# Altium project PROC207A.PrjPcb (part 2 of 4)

## Sheet PROC207A_Chip_Power.SchDoc: xWRL6888_POWER
size 431 x 279 mm; Date: Not shown in title block; ApprovedBy: Not shown in title block; CheckedBy: Not shown in title block; Author: Not shown in title block; CompanyName: Not shown in title block; DrawnBy: Mistral; Engineer: Not shown in title block; Organization: Not shown in title block; Address1: Not shown in title block; Address2: Not shown in title block; Address3: Not shown in title block; Address4: Not shown in title block; DocumentNumber: 2; Revision: Use project parameter SCH_Rev; SheetNumber: 7; SheetTotal: 18; PageSetup: Record=PageOptions¦CenterHorizontal=True¦CenterVertical=True¦PrintScale=1.00¦XCorrection=1.00¦YCorrection=1.00¦PrintKind=0¦BorderSize=5000000¦LeftOffset=0¦BottomOffset=0¦Orientation=2¦PaperLength=1000¦PaperWidth=1000¦Scale=100¦PaperSource=15¦PrintQuality=600¦MediaType=1¦DitherType=10¦PaperKind=Letter¦PrintScaleMode=1

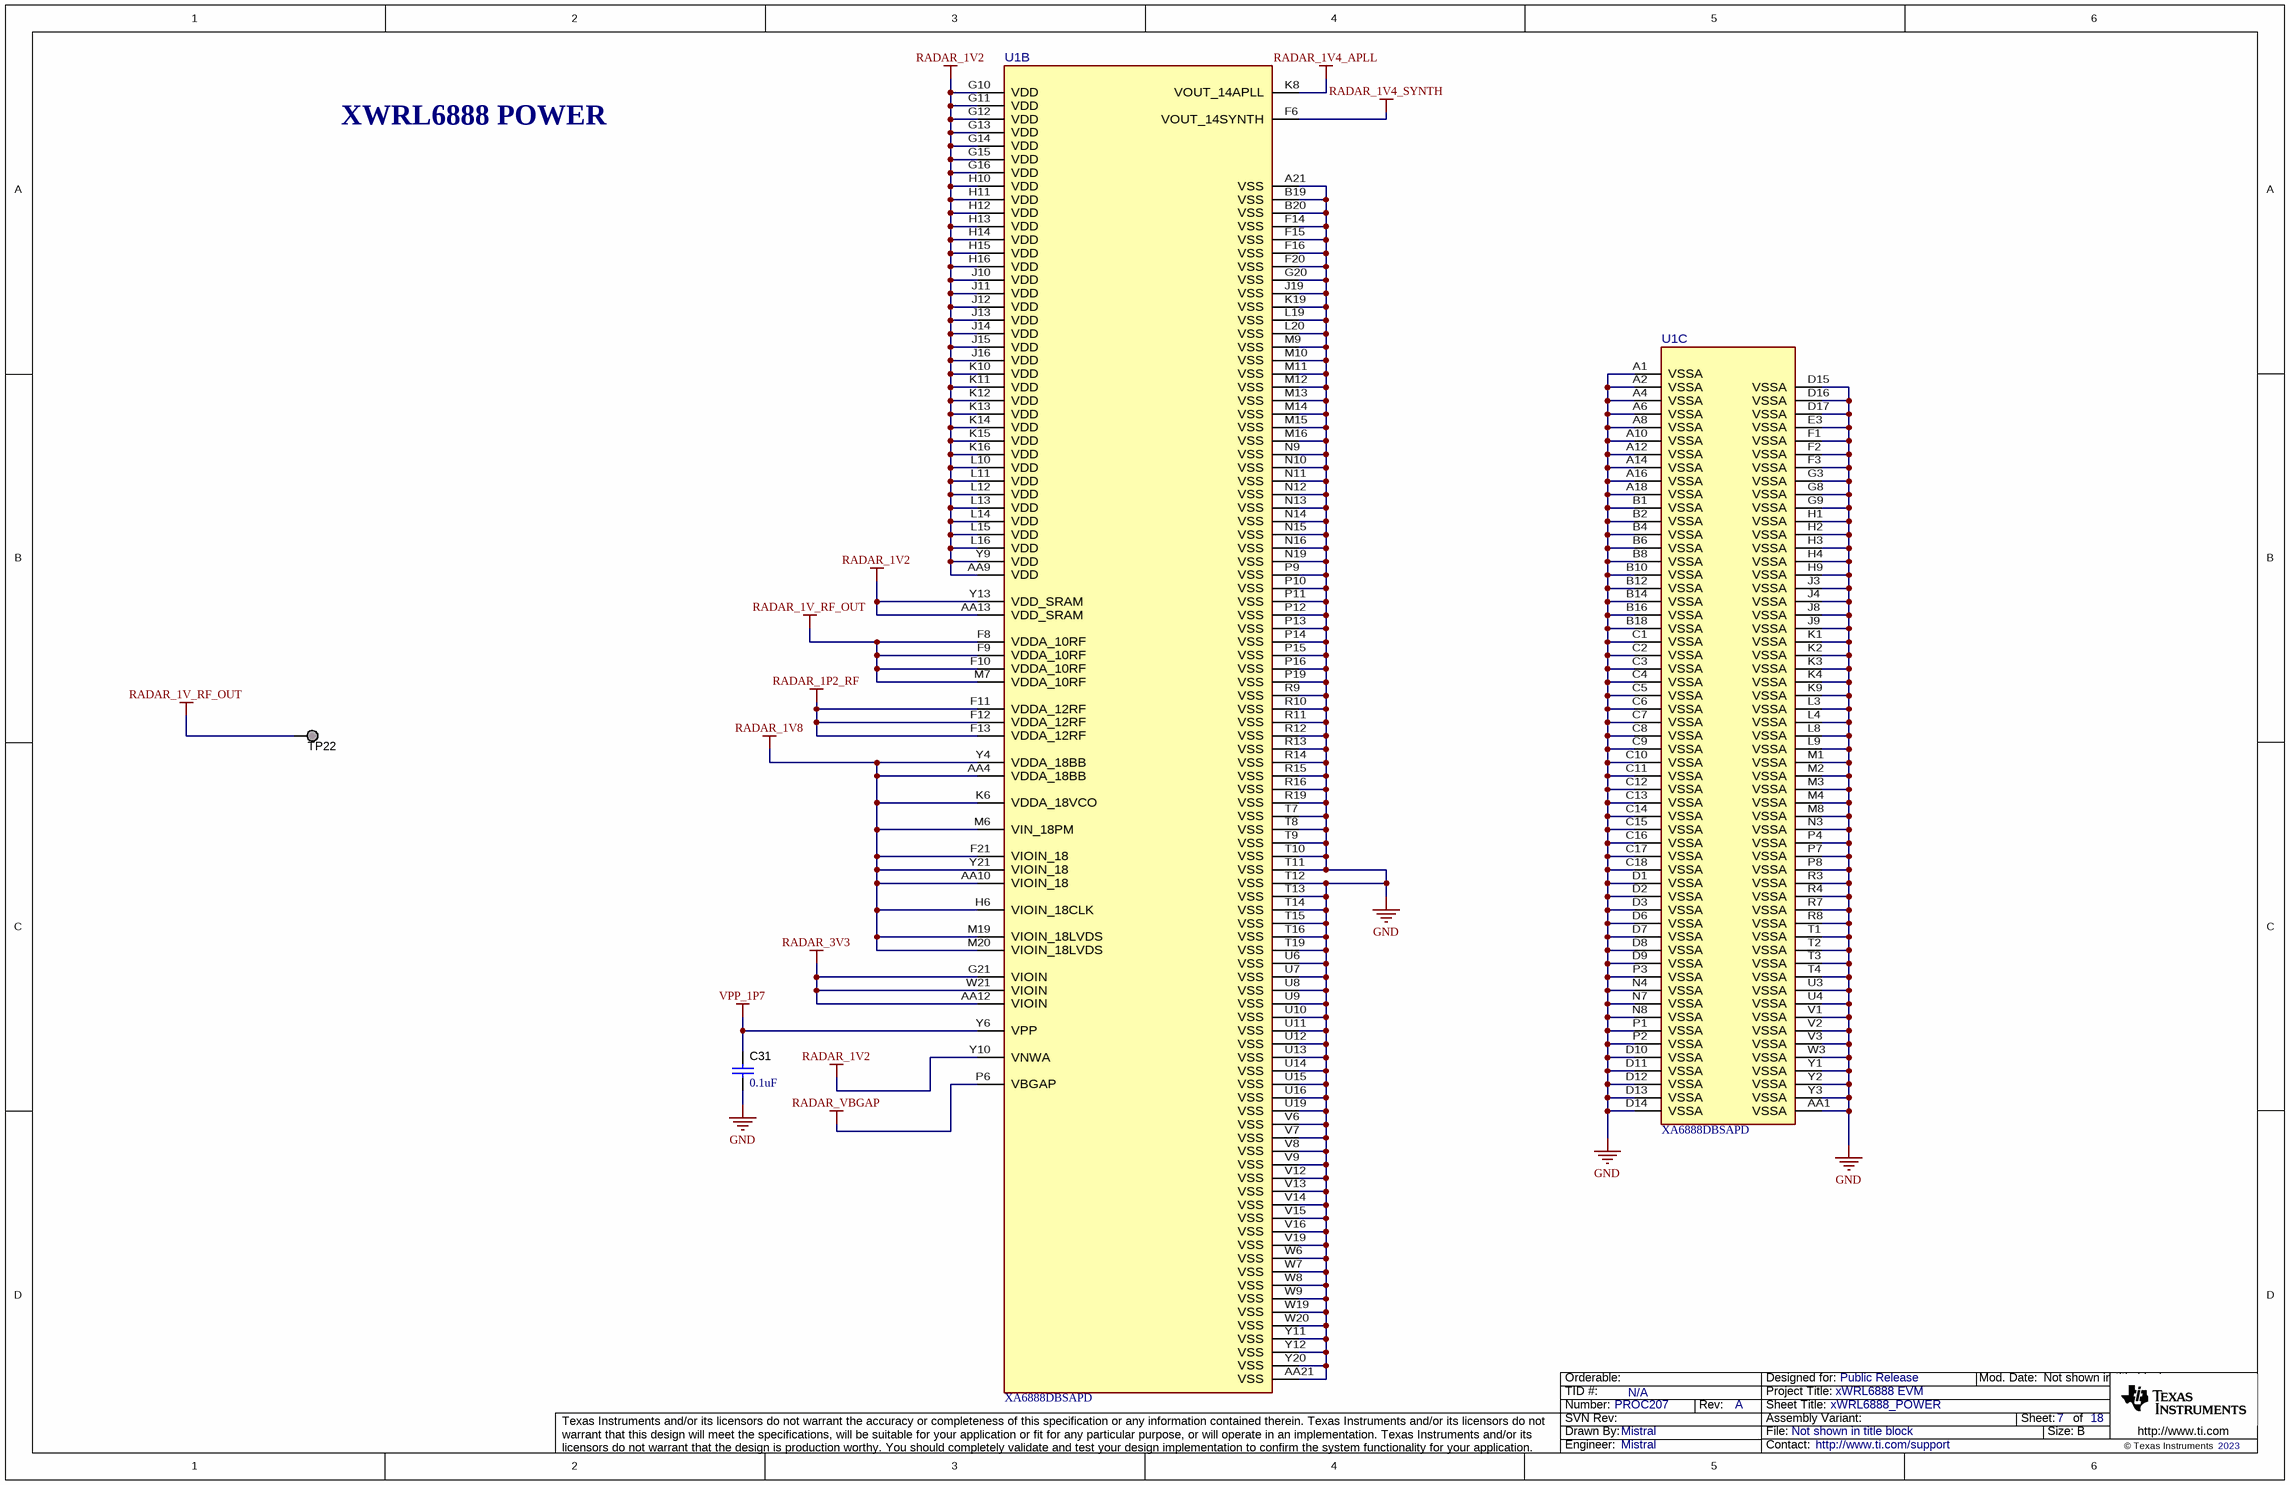
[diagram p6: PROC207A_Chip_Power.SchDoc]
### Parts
C31  ValueDisplayed: 0.1uF  [0402]  (hidden comment: GCM155R71H104KE02D)
TP22  TESTPOINT  [TP_VIA_060RND040]  (value not drawn)  (no BOM)
U1  XA6888DBSAPD  [0-MFG]  (parts B,C of 3)

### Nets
GND: C31.2 U1.A1(VSSA) U1.A2(VSSA) U1.A4(VSSA) U1.A6(VSSA) U1.A8(VSSA) U1.A10(VSSA) U1.A12(VSSA) U1.A14(VSSA) U1.A16(VSSA) U1.A18(VSSA) U1.A21(VSS) U1.AA1(VSSA) U1.AA21(VSS) U1.B1(VSSA) U1.B2(VSSA) U1.B4(VSSA) U1.B6(VSSA) U1.B8(VSSA) U1.B10(VSSA) U1.B12(VSSA) U1.B14(VSSA) U1.B16(VSSA) U1.B18(VSSA) U1.B19(VSS) U1.B20(VSS) U1.C1(VSSA) U1.C2(VSSA) U1.C3(VSSA) U1.C4(VSSA) U1.C5(VSSA) U1.C6(VSSA) U1.C7(VSSA) U1.C8(VSSA) U1.C9(VSSA) U1.C10(VSSA) U1.C11(VSSA) U1.C12(VSSA) U1.C13(VSSA) U1.C14(VSSA) U1.C15(VSSA) U1.C16(VSSA) U1.C17(VSSA) U1.C18(VSSA) U1.D1(VSSA) U1.D2(VSSA) U1.D3(VSSA) U1.D6(VSSA) U1.D7(VSSA) U1.D8(VSSA) U1.D9(VSSA) U1.D10(VSSA) U1.D11(VSSA) U1.D12(VSSA) U1.D13(VSSA) U1.D14(VSSA) U1.D15(VSSA) U1.D16(VSSA) U1.D17(VSSA) U1.E3(VSSA) U1.F1(VSSA) U1.F2(VSSA) U1.F3(VSSA) U1.F14(VSS) U1.F15(VSS) U1.F16(VSS) U1.F20(VSS) U1.G3(VSSA) U1.G8(VSSA) U1.G9(VSSA) U1.G20(VSS) U1.H1(VSSA) U1.H2(VSSA) U1.H3(VSSA) U1.H4(VSSA) U1.H9(VSSA) U1.J3(VSSA) U1.J4(VSSA) U1.J8(VSSA) U1.J9(VSSA) U1.J19(VSS) U1.K1(VSSA) U1.K2(VSSA) U1.K3(VSSA) U1.K4(VSSA) U1.K9(VSSA) U1.K19(VSS) U1.L3(VSSA) U1.L4(VSSA) U1.L8(VSSA) U1.L9(VSSA) U1.L19(VSS) U1.L20(VSS) U1.M1(VSSA) U1.M2(VSSA) U1.M3(VSSA) U1.M4(VSSA) U1.M8(VSSA) U1.M9(VSS) U1.M10(VSS) U1.M11(VSS) U1.M12(VSS) U1.M13(VSS) U1.M14(VSS) U1.M15(VSS) U1.M16(VSS) U1.N3(VSSA) U1.N4(VSSA) U1.N7(VSSA) U1.N8(VSSA) U1.N9(VSS) U1.N10(VSS) U1.N11(VSS) U1.N12(VSS) U1.N13(VSS) U1.N14(VSS) U1.N15(VSS) U1.N16(VSS) U1.N19(VSS) U1.P1(VSSA) U1.P2(VSSA) U1.P3(VSSA) U1.P4(VSSA) U1.P7(VSSA) U1.P8(VSSA) U1.P9(VSS) U1.P10(VSS) U1.P11(VSS) U1.P12(VSS) U1.P13(VSS) U1.P14(VSS) U1.P15(VSS) U1.P16(VSS) U1.P19(VSS) U1.R3(VSSA) U1.R4(VSSA) U1.R7(VSSA) U1.R8(VSSA) U1.R9(VSS) U1.R10(VSS) U1.R11(VSS) U1.R12(VSS) U1.R13(VSS) U1.R14(VSS) U1.R15(VSS) U1.R16(VSS) U1.R19(VSS) U1.T1(VSSA) U1.T2(VSSA) U1.T3(VSSA) U1.T4(VSSA) U1.T7(VSS) U1.T8(VSS) U1.T9(VSS) U1.T10(VSS) U1.T11(VSS) U1.T12(VSS) U1.T13(VSS) U1.T14(VSS) U1.T15(VSS) U1.T16(VSS) U1.T19(VSS) U1.U3(VSSA) U1.U4(VSSA) U1.U6(VSS) U1.U7(VSS) U1.U8(VSS) U1.U9(VSS) U1.U10(VSS) U1.U11(VSS) U1.U12(VSS) U1.U13(VSS) U1.U14(VSS) U1.U15(VSS) U1.U16(VSS) U1.U19(VSS) U1.V1(VSSA) U1.V2(VSSA) U1.V3(VSSA) U1.V6(VSS) U1.V7(VSS) U1.V8(VSS) U1.V9(VSS) U1.V12(VSS) U1.V13(VSS) U1.V14(VSS) U1.V15(VSS) U1.V16(VSS) U1.V19(VSS) U1.W3(VSSA) U1.W6(VSS) U1.W7(VSS) U1.W8(VSS) U1.W9(VSS) U1.W19(VSS) U1.W20(VSS) U1.Y1(VSSA) U1.Y2(VSSA) U1.Y3(VSSA) U1.Y11(VSS) U1.Y12(VSS) U1.Y20(VSS)
RADAR_1P2_RF: U1.F11(VDDA_12RF) U1.F12(VDDA_12RF) U1.F13(VDDA_12RF)
RADAR_1V2: U1.AA9(VDD) U1.AA13(VDD_SRAM) U1.G10(VDD) U1.G11(VDD) U1.G12(VDD) U1.G13(VDD) U1.G14(VDD) U1.G15(VDD) U1.G16(VDD) U1.H10(VDD) U1.H11(VDD) U1.H12(VDD) U1.H13(VDD) U1.H14(VDD) U1.H15(VDD) U1.H16(VDD) U1.J10(VDD) U1.J11(VDD) U1.J12(VDD) U1.J13(VDD) U1.J14(VDD) U1.J15(VDD) U1.J16(VDD) U1.K10(VDD) U1.K11(VDD) U1.K12(VDD) U1.K13(VDD) U1.K14(VDD) U1.K15(VDD) U1.K16(VDD) U1.L10(VDD) U1.L11(VDD) U1.L12(VDD) U1.L13(VDD) U1.L14(VDD) U1.L15(VDD) U1.L16(VDD) U1.Y9(VDD) U1.Y10(VNWA) U1.Y13(VDD_SRAM)
RADAR_1V4_APLL: U1.K8(VOUT_14APLL)
RADAR_1V4_SYNTH: U1.F6(VOUT_14SYNTH)
RADAR_1V8: U1.AA4(VDDA_18BB) U1.AA10(VIOIN_18) U1.F21(VIOIN_18) U1.H6(VIOIN_18CLK) U1.K6(VDDA_18VCO) U1.M6(VIN_18PM) U1.M19(VIOIN_18LVDS) U1.M20(VIOIN_18LVDS) U1.Y4(VDDA_18BB) U1.Y21(VIOIN_18)
RADAR_1V_RF_OUT: TP22.1 U1.F8(VDDA_10RF) U1.F9(VDDA_10RF) U1.F10(VDDA_10RF) U1.M7(VDDA_10RF)
RADAR_3V3: U1.AA12(VIOIN) U1.G21(VIOIN) U1.W21(VIOIN)
RADAR_VBGAP: U1.P6(VBGAP)
VPP_1P7: C31.1 U1.Y6(VPP)

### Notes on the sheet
- XWRL6888 POWER

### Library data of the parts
C31 = CMP-0006356-2: CAP, CERM, 0.1 uF, 50 V, +/- 10%, X7R, AEC-Q200 Grade 1, 0402; Manufacturer: MuRata; TaMin_C: -55°C; Polarized: N; SizeAreaWB_mm2: 3; Value1: Unknown; U/M: EA; Value: 0.1uF; TaMax_C: 125°C; SizeZ_mm: 0.6; SizeX_mm: 1; SizeY_mm: 0.5; Value2: 50V; AEC Qualified: Y; Cap_F: 100nF; AEC Category: Q200
TP22 = CMP-0078143-3: TEST POINT.  No entry in BOM.
U1 = CMP-0122984-4: Manufacturer: Texas Instruments; SizeZ_mm: 1.044mm; AEC Qualified: Unknown; Standoff Height: 0.155mm; AEC Category: Q200; CompType: IC

## Sheet PROC207A_Decoupling_caps- QSPI Flash.SchDoc: DECOUPLING_CAPS_QSPI_FLASH
size 431 x 279 mm; Date: Not shown in title block; ApprovedBy: Not shown in title block; CheckedBy: Not shown in title block; Author: Not shown in title block; CompanyName: Not shown in title block; DrawnBy: Mistral; Engineer: Not shown in title block; Organization: Not shown in title block; Address1: Not shown in title block; Address2: Not shown in title block; Address3: Not shown in title block; Address4: Not shown in title block; DocumentNumber: 2; Revision: Use project parameter SCH_Rev; SheetNumber: 8; SheetTotal: 18; PageSetup: Record=PageOptions¦CenterHorizontal=True¦CenterVertical=True¦PrintScale=1.00¦XCorrection=1.00¦YCorrection=1.00¦PrintKind=0¦BorderSize=5000000¦LeftOffset=0¦BottomOffset=0¦Orientation=2¦PaperLength=1000¦PaperWidth=1000¦Scale=100¦PaperSource=15¦PrintQuality=600¦MediaType=1¦DitherType=10¦PaperKind=Letter¦PrintScaleMode=1

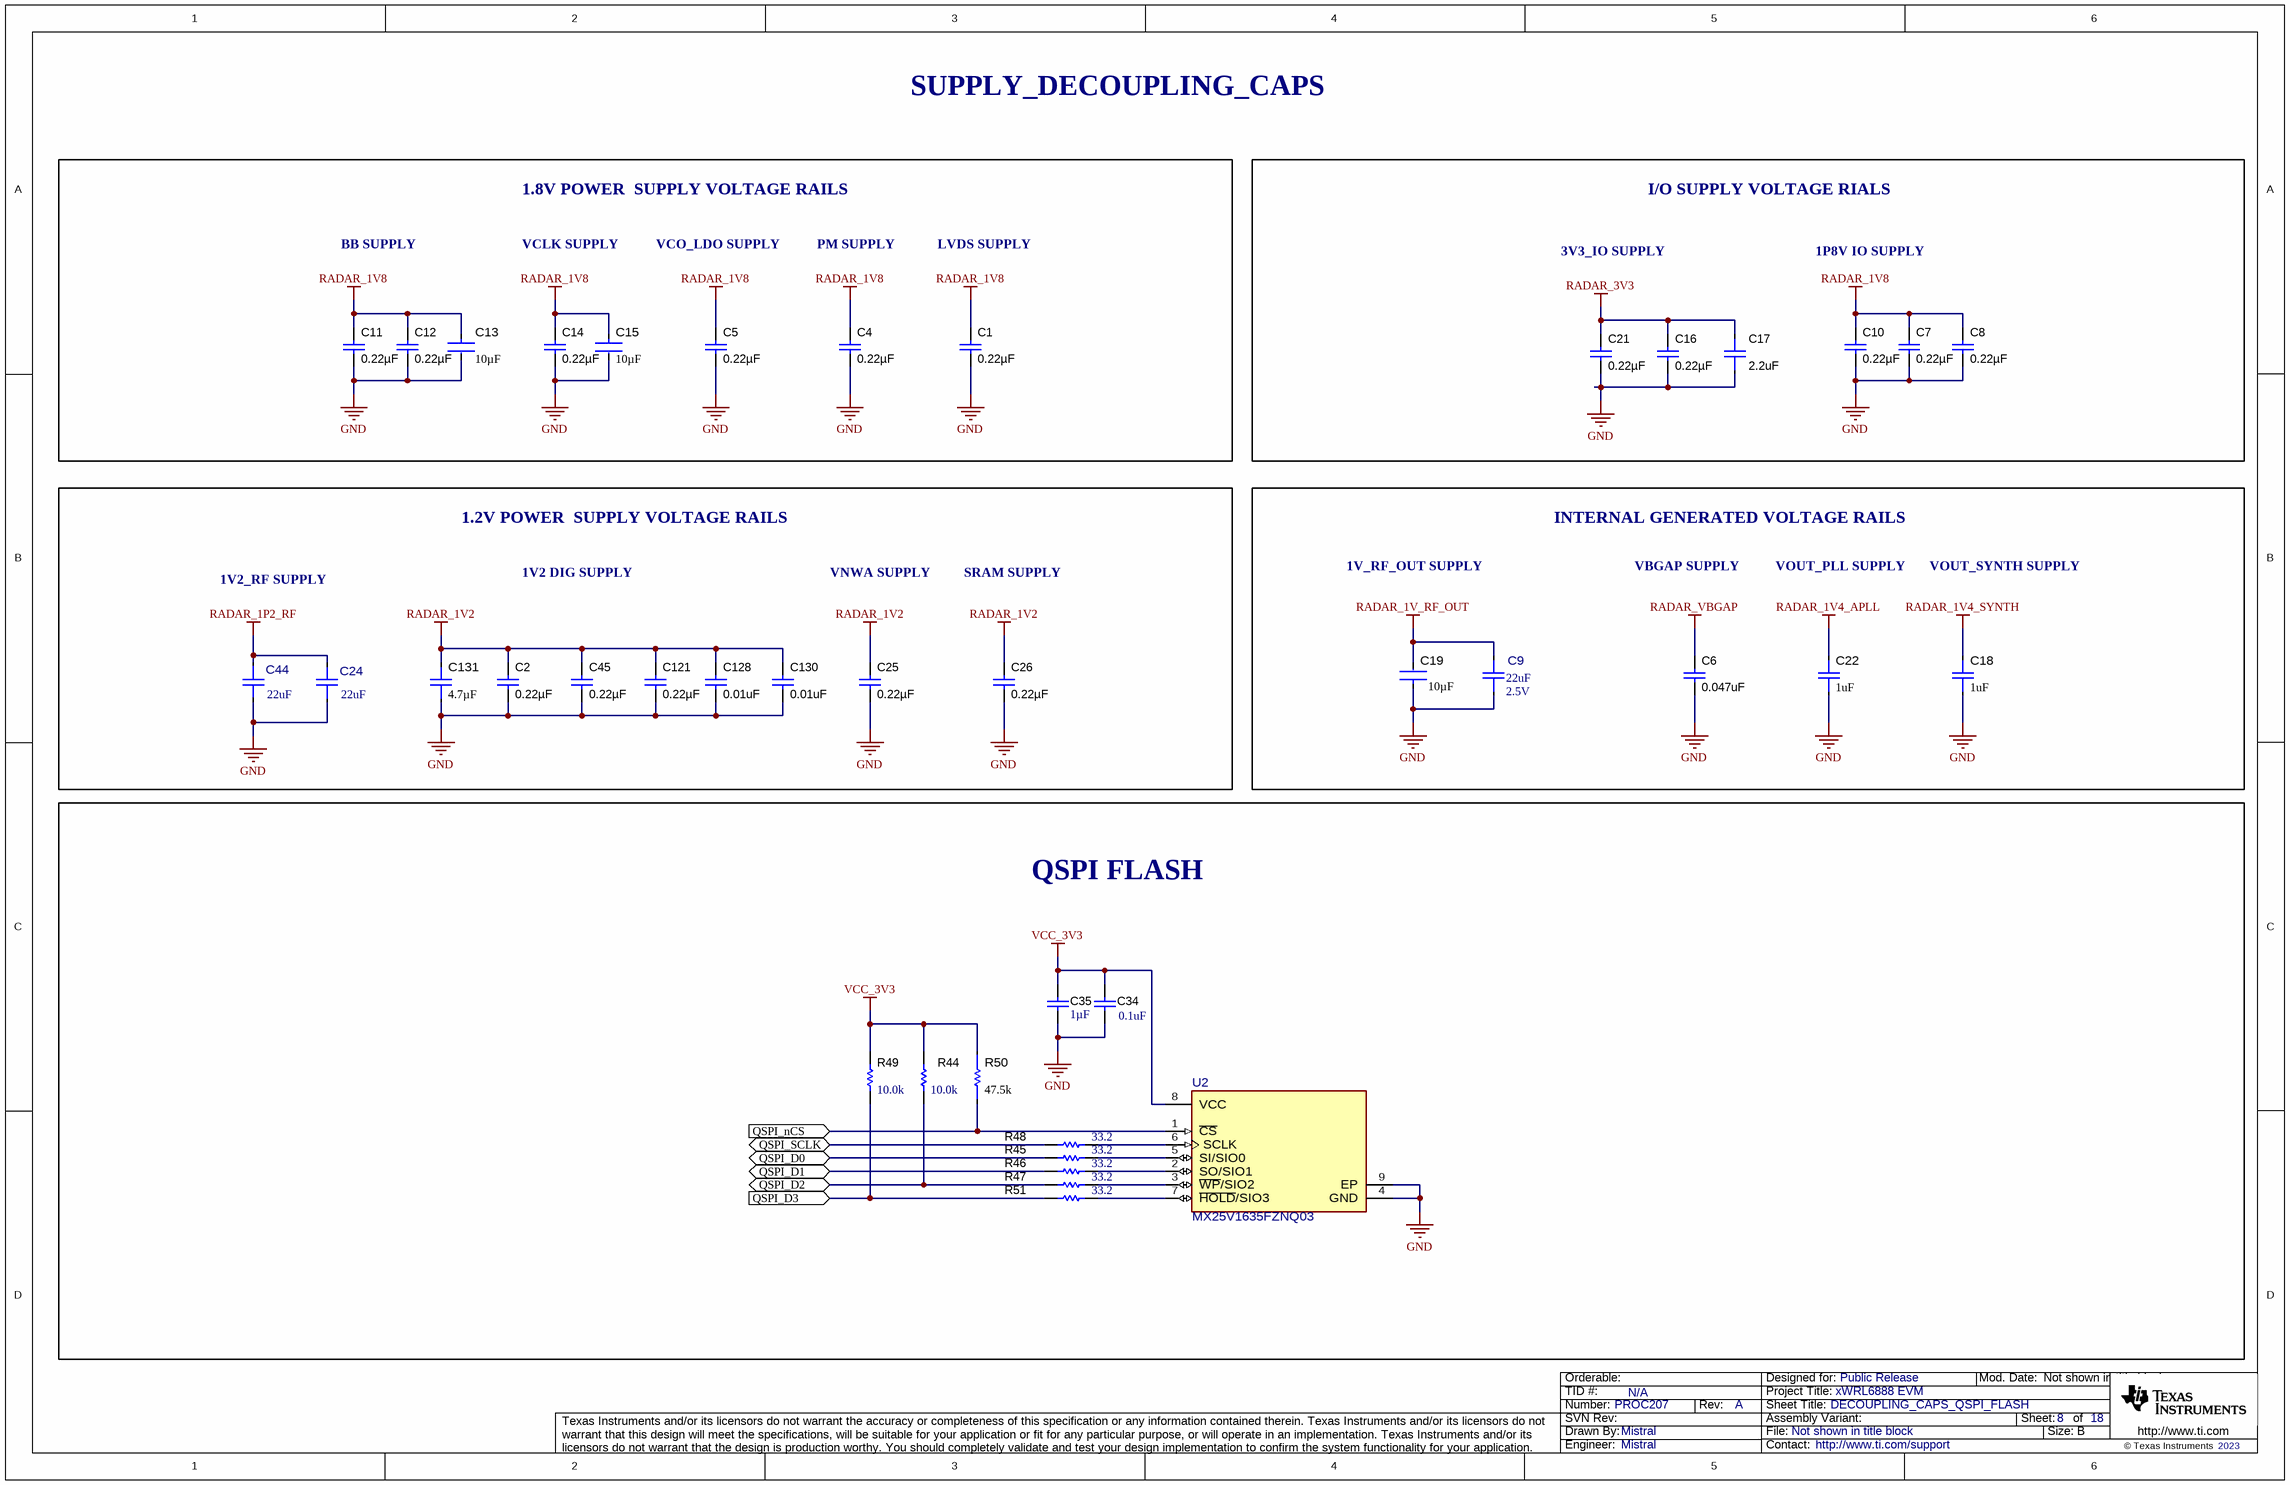
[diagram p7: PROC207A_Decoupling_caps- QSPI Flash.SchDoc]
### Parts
C1  ValueDisplayed: 0.22µF  [0402L]  (hidden comment: GCM155R71C224KE02D)
C2  ValueDisplayed: 0.22µF  [0402L]  (hidden comment: GCM155R71C224KE02D)
C4  ValueDisplayed: 0.22µF  [0402L]  (hidden comment: GCM155R71C224KE02D)
C5  ValueDisplayed: 0.22µF  [0402L]  (hidden comment: GCM155R71C224KE02D)
C6  ValueDisplayed: 0.047uF  [0402L]  (hidden comment: CGA2B3X7R1H473K050BB)
C7  ValueDisplayed: 0.22µF  [0402L]  (hidden comment: GCM155R71C224KE02D)
C8  ValueDisplayed: 0.22µF  [0402L]  (hidden comment: GCM155R71C224KE02D)
C9  ValueDisplayed: 22uF  VDC_V: 2.5V  [FP-GCM188D70E226ME36D_0603-MFG]  (hidden comment: GCM188D70E226ME36D)
C10  ValueDisplayed: 0.22µF  [0402L]  (hidden comment: GCM155R71C224KE02D)
C11  ValueDisplayed: 0.22µF  [0402L]  (hidden comment: GCM155R71C224KE02D)
C12  ValueDisplayed: 0.22µF  [0402L]  (hidden comment: GCM155R71C224KE02D)
C13  Cap_F: 10µF  [FP-GCM188D70J106ME36D_0603-MFG]  (hidden comment: GCM188D70J106ME36D)
C14  ValueDisplayed: 0.22µF  [0402L]  (hidden comment: GCM155R71C224KE02D)
C15  Cap_F: 10µF  [FP-GCM188D70J106ME36D_0603-MFG]  (hidden comment: GCM188D70J106ME36D)
C16  ValueDisplayed: 0.22µF  [0402L]  (hidden comment: GCM155R71C224KE02D)
C17  ValueDisplayed: 2.2uF  [FP-GRT155C71A225KE13D_0402-MFG]  (hidden comment: GRT155C71A225KE13D)
C18  ValueDisplayed: 1uF  [FP-GRT155R70J105KE01D_0402-MFG]  (hidden comment: GRT155R70J105KE01D)
C19  Cap_F: 10µF  [FP-GCM188D70J106ME36D_0603-MFG]  (hidden comment: GCM188D70J106ME36D)
C21  ValueDisplayed: 0.22µF  [0402L]  (hidden comment: GCM155R71C224KE02D)
C22  ValueDisplayed: 1uF  [FP-GRT155R70J105KE01D_0402-MFG]  (hidden comment: GRT155R70J105KE01D)
C24  ValueDisplayed: 22uF  [FP-GCM188D70E226ME36D_0603-MFG]  (hidden comment: GCM188D70E226ME36D)
C25  ValueDisplayed: 0.22µF  [0402L]  (hidden comment: GCM155R71C224KE02D)
C26  ValueDisplayed: 0.22µF  [0402L]  (hidden comment: GCM155R71C224KE02D)
C34  ValueDisplayed: 0.1uF  [0402]  (hidden comment: GCM155R71H104KE02D)
C35  Cap_F: 1µF  [0603]  (hidden comment: CL10B105KA8NNNC)
C44  ValueDisplayed: 22uF  [FP-GCM188D70E226ME36D_0603-MFG]  (hidden comment: GCM188D70E226ME36D)
C45  ValueDisplayed: 0.22µF  [0402L]  (hidden comment: GCM155R71C224KE02D)
C121  ValueDisplayed: 0.22µF  [0402L]  (hidden comment: GCM155R71C224KE02D)
C128  ValueDisplayed: 0.01uF  [0402L]  (hidden comment: GCM155R71E103KA37D)
C130  ValueDisplayed: 0.01uF  [0402L]  (hidden comment: GCM155R71E103KA37D)
C131  Cap_F: 4.7µF  [FP-GCJ21BR71C475KA01L_0805-MFG]  (hidden comment: GCJ21BR71C475KA01L)
R44  value 10.0k  [0402]  (hidden comment: CRCW040210K0FKED)
R45  value 33.2  [0402]  (hidden comment: CRCW040233R2FKED)
R46  value 33.2  [0402]  (hidden comment: CRCW040233R2FKED)
R47  value 33.2  [0402]  (hidden comment: CRCW040233R2FKED)
R48  value 33.2  [0402]  (hidden comment: CRCW040233R2FKED)
R49  value 10.0k  [0402]  (hidden comment: CRCW040210K0FKED)
R50  value 47.5k  [FP-RC0402FR-1047K5L_0402-MFG]  (hidden comment: RC0402FR-1047K5L)
R51  value 33.2  [0402]  (hidden comment: CRCW040233R2FKED)
U2  MX25V1635FZNQ03  [FP-MX25V1635FZNQ03_WSON8-MFG]

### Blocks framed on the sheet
1.8V POWER  SUPPLY VOLTAGE RAILS: C1 C4 C5 C11-C15
I/O SUPPLY VOLTAGE RIALS: C7 C8 C10 C16 C17 C21
1.2V POWER  SUPPLY VOLTAGE RAILS: C2 C24-C26 C44 C45 C121 C128 C130 C131
INTERNAL GENERATED VOLTAGE RAILS: C6 C9 C18 C19 C22
QSPI FLASH: C34 C35 R44-R51 U2

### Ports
QSPI_D0 (bidir), QSPI_D1 (bidir), QSPI_D2 (bidir), QSPI_D3 (in), QSPI_nCS (in), QSPI_SCLK (bidir)

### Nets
GND: C1.1 C2.1 C4.1 C5.1 C6.2 C7.1 C8.1 C9.1 C10.1 C11.1 C12.1 C13.2 C14.1 C15.2 C16.1 C17.1 C18.1 C19.1 C21.1 C22.1 C24.1 C25.1 C26.1 C34.2 C35.1 C44.2 C45.1 C121.1 C128.2 C130.2 C131.1 U2.4(GND) U2.9(EP)
RADAR_1P2_RF: C24.2 C44.1
RADAR_1V2: C2.2 C25.2 C26.2 C45.2 C121.2 C128.1 C130.1 C131.2
RADAR_1V4_APLL: C22.2
RADAR_1V4_SYNTH: C18.2
RADAR_1V8: C1.2 C4.2 C5.2 C7.2 C8.2 C10.2 C11.2 C12.2 C13.1 C14.2 C15.1
RADAR_1V_RF_OUT: C9.2 C19.2
RADAR_3V3: C16.2 C17.2 C21.2
RADAR_VBGAP: C6.1
VCC_3V3: C34.1 C35.2 R44.2 R49.2 R50.1 U2.8(VCC)
QSPI_D0: R45.2 ; port QSPI_D0
QSPI_D1: R46.1 ; port QSPI_D1
QSPI_D2: R44.1 R47.1 ; port QSPI_D2
QSPI_D3: R49.1 R51.2 ; port QSPI_D3
QSPI_nCS: R50.2 U2.1(~{CS}) ; port QSPI_nCS
QSPI_SCLK: R48.2 ; port QSPI_SCLK
NetR45_1: R45.1 U2.5(SI/SIO0)
NetR46_2: R46.2 U2.2(SO/SIO1)
NetR47_2: R47.2 U2.3(~{WP}/SIO2)
NetR48_1: R48.1 U2.6(SCLK)
NetR51_1: R51.1 U2.7(~{HOLD}/SIO3)

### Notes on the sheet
- SUPPLY_DECOUPLING_CAPS
- BB SUPPLY
- VCLK SUPPLY
- VCO_LDO SUPPLY
- PM SUPPLY
- LVDS SUPPLY
- 3V3_IO SUPPLY
- 1P8V IO SUPPLY
- 1V_RF_OUT SUPPLY
- VBGAP SUPPLY
- VOUT_PLL SUPPLY
- VOUT_SYNTH SUPPLY
- 1V2_RF SUPPLY
- 1V2 DIG SUPPLY
- VNWA SUPPLY
- SRAM SUPPLY

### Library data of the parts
C1 C2 C4 C5 C7 C8 C10-C12 C14 C16 C21 C25 C26 C45 C121 = CMP-0078265-1: CAP, CERM, 0.22 µF, 16 V,+/- 10%, X7R, AEC-Q200 Grade 1, 0402; Manufacturer: MuRata; TaMin_C: -55°C; Polarized: N; SizeAreaWB_mm2: 3; U/M: EA; Value: 0.22uF; TaMax_C: 125°C; SizeZ_mm: 0.6; SizeX_mm: 1; SizeY_mm: 0.5; Cap_Case: 0402; Value2: 16V; CompType: Capacitor; AEC Qualified: Y; Cap_F: 220nF; AEC Category: Q200
C6 = CMP-0006330-2: CAP, CERM, 0.047 uF, 50 V, +/- 10%, X7R, AEC-Q200 Grade 1, 0402; Manufacturer: TDK; Polarized: N; U/M: EA; Cap_F: 47nF; ESR_ohm: 0.06407; Value1: 0.06407 ohm; VDC_V: 50V; IRMS_A: 646.122mA; TaMin_C: -55°C; TaMax_C: 125°C; Cap_Case: 0402; SizeArea_mm2: 0.5; SizeAreaWB_mm2: 3; SizeX_mm: 1; SizeZ_mm: 0.6; AEC Category: Q200; AEC Qualified: Y
C9 C24 C44 = CMP-0048366-1: 22 µF ±20% 2.5V Ceramic Capacitor X7T 0603 (1608 Metric); Manufacturer: Murata; AEC Grade: Grade 1; AEC Qualified: Yes; Cap_F: 22µF; SizeZ_mm: 1mm; TempCo: +22/-33%; Value: 22µF
C13 C15 C19 = CMP-0086534-1: Chip Multilayer Ceramic Capacitors for Automotive; Manufacturer: Murata; Tolerance_%: 20%; SizeZ_mm: 1mm; TempCo: -33+22%; Symbol Name: SYM-GCM188D70J106ME36D; VDC_V: 6.3V; AEC Grade: Grade 1; AEC Qualified: Yes
C17 = CMP-0094968-1: Multi-Layer Ceramic Capacitor 2.2uF 10V X7S ±10% 0402 Paper T/R; Manufacturer: Murata; AEC Grade: Grade 1; Cap_F: 2.2µF; SizeZ_mm: 0.7mm; Value: 2.2µF; AEC Qualified: Yes; TempCo: 22%
C18 C22 = CMP-0088425-1: 1µF ±10% 6.3V Ceramic Capacitor X7R 0402 (1005 Metric); Manufacturer: Murata; AEC Grade: Grade 1; SizeZ_mm: 0.55mm; AEC Qualified: Yes; TempCo: 15%
C34 = CMP-0006356-2: as C31 on sheet PROC207A_Chip_Power
C35 = CMP-0086540-3: CAP, 1uF, 25V, ±10%, X7R, 0603; Manufacturer: Samsung; SizeZ_mm: 0.9mm; AEC Qualified: No; TempCo: 15%; Symbol Name: SYM-CL10B105KA8NNNC
C128 C130 = CMP-0006352-2: CAP, CERM, 0.01 uF, 25 V, +/- 10%, X7R, 0402; Manufacturer: MuRata; TaMin_C: -55°C; Polarized: N; SizeAreaWB_mm2: 3; Value1: Unknown; U/M: EA; Value: 0.01uF; TaMax_C: 125°C; SizeZ_mm: 0.6; SizeX_mm: 1; SizeY_mm: 0.5; Cap_Case: 0402; Value2: 25V; CompType: Capacitor; Cap_F: 10nF; AEC Category: Q200
C131 = CMP-0094778-1: Multilayer Ceramic Capacitors MLCC - SMD/SMT 0805 4.7uF 10%, 16VDC,  X7R 15%; Manufacturer: Murata; AEC Qualified: Yes; Value: 4.7µF; AEC Grade: Grade 1; SizeZ_mm: 1.45mm; VDC_V: 16V
R44 R49 = CMP-0025958-3: RES, 10.0 k, 1%, 0.063 W, AEC-Q200 Grade 0, 0402; Manufacturer: Vishay-Dale; AEC Qualified: Y; Power_W: 63mW; Res_ohm: 10k; SizeZ_mm: 0.6; TempCo: 100 ppm/C; VDC_V: 50V; AEC Category: Q200; AEC Grade: 0; EIA_Code: E96; SizeArea_mm2: 0.5; SizeX_mm: 1; Value2: 0.063W; Value_Code: 10k0
R45-R48 R51 = CMP-0026299-2: RES, 33.2, 1%, 0.063 W, AEC-Q200 Grade 0, 0402; Manufacturer: Vishay-Dale; AEC Qualified: Y; Power_W: 63mW; SizeZ_mm: 0.6; TempCo: 100 ppm/C; VDC_V: 50V; AEC Category: Q200; AEC Grade: 0; EIA_Code: E96; SizeArea_mm2: 0.5; SizeX_mm: 1; Value2: 0.063W; Value_Code: 33R2
R50 = CMP-0120015-1: General Purpose Chip Resistor Thick Film 0402 47.5kOhm 1% Paper T/R; Manufacturer: YAGEO; AEC Qualified: No; Power_W: 63mW; SizeZ_mm: 0.4mm; TempCo: 100ppm/°C; VDC_V: 50V
U2 = CMP-0093403-2: NOR Flash 16Mbit 16M x 1/8M x 2/4M x 4 Serial-SPI 3.3V 8-Pin WSON; Manufacturer: Macronix; TaMax_C: +85°C; AEC Qualified: No; Interface: SPI; Max Supply Voltage: 3.6V; TaMin_C: -40°C; Min Supply Voltage: 2.3V; Memory Type: FLASH,NOR; SizeZ_mm: 0.8mm; Memory Size: 16Mbits; Frequency_Fixed: 80MHz

## Sheet PROC207A_Temp_Current_sensors_EPROM.SchDoc: TEMP_CURRENT_SENSORS_EEPROM
size 431 x 279 mm; Date: Not shown in title block; ApprovedBy: Not shown in title block; CheckedBy: Not shown in title block; Author: Not shown in title block; CompanyName: Not shown in title block; DrawnBy: Mistral; Engineer: Not shown in title block; Organization: Not shown in title block; Address1: Not shown in title block; Address2: Not shown in title block; Address3: Not shown in title block; Address4: Not shown in title block; DocumentNumber: 8; Revision: Use project parameter SCH_Rev; SheetNumber: 9; SheetTotal: 18; PageSetup: Record=PageOptions¦CenterHorizontal=True¦CenterVertical=True¦PrintScale=1.00¦XCorrection=1.00¦YCorrection=1.00¦PrintKind=0¦BorderSize=5000000¦LeftOffset=0¦BottomOffset=0¦Orientation=2¦PaperLength=1000¦PaperWidth=1000¦Scale=100¦PaperSource=15¦PrintQuality=600¦MediaType=1¦DitherType=10¦PaperKind=Letter¦PrintScaleMode=1

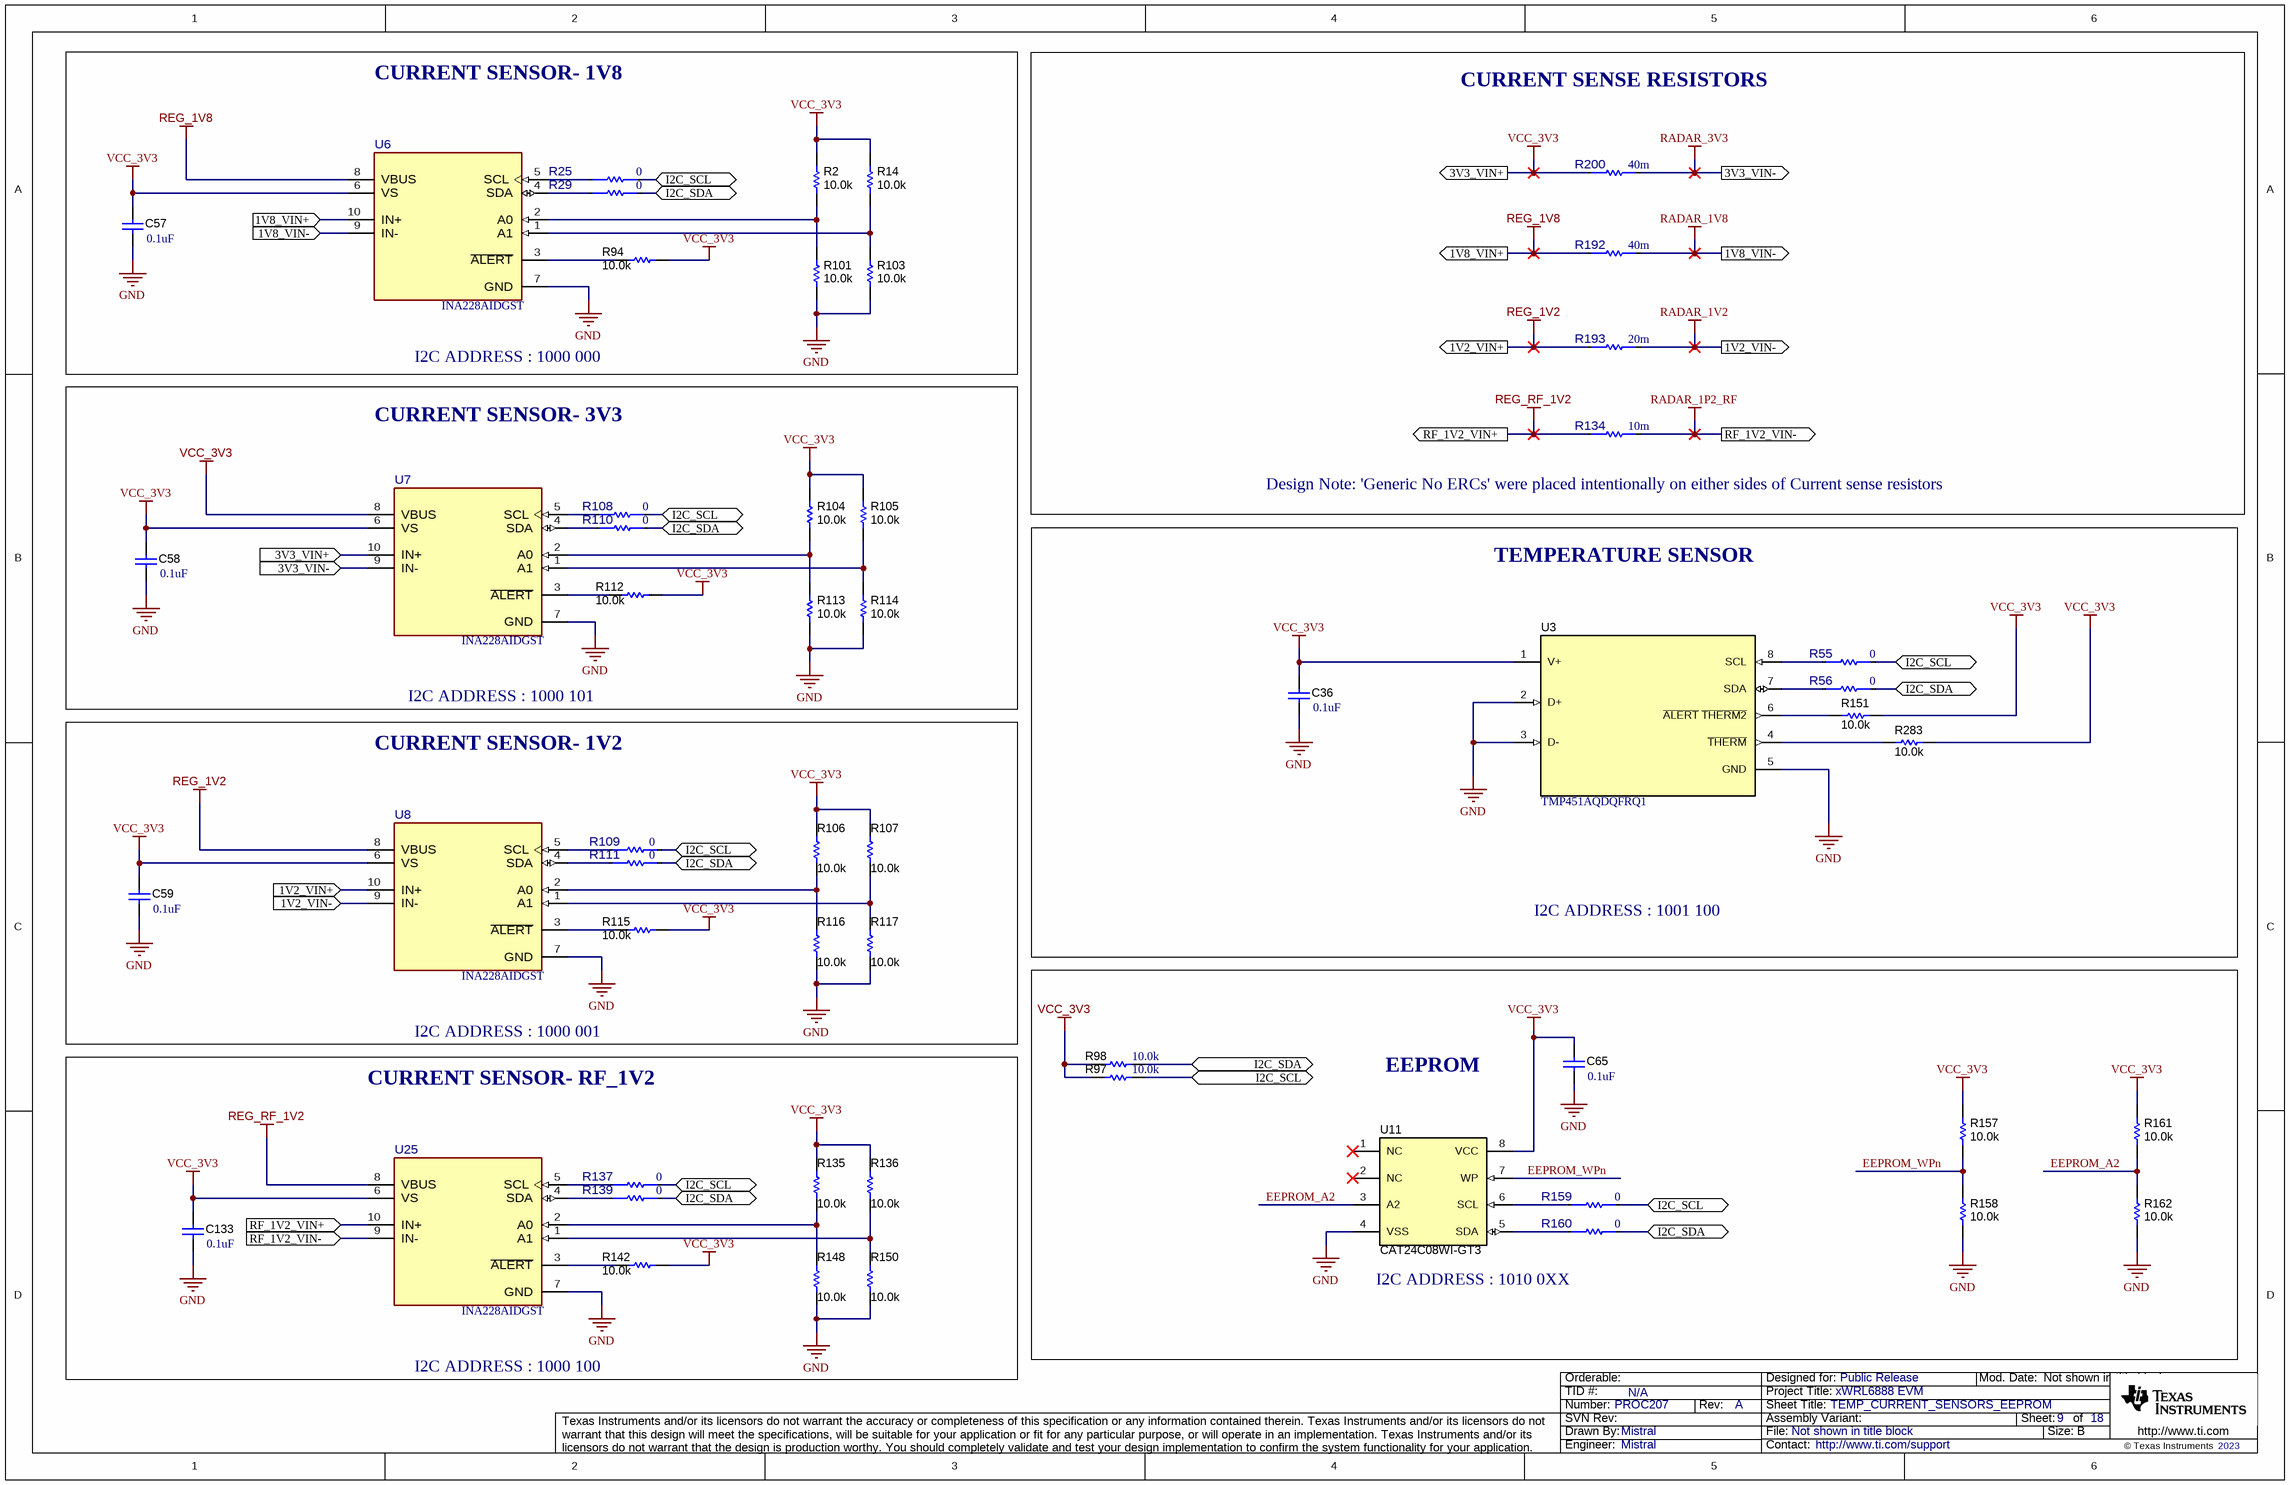
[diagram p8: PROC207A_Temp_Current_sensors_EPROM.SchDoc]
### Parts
C36  ValueDisplayed: 0.1uF  [0402]  (hidden comment: GCM155R71H104KE02D)
C57  ValueDisplayed: 0.1uF  [0402]  (hidden comment: GCM155R71H104KE02D)
C58  ValueDisplayed: 0.1uF  [0402]  (hidden comment: GCM155R71H104KE02D)
C59  ValueDisplayed: 0.1uF  [0402]  (hidden comment: GCM155R71H104KE02D)
C65  ValueDisplayed: 0.1uF  [0402]  (hidden comment: GCM155R71H104KE02D)
C133  ValueDisplayed: 0.1uF  [0402]  (hidden comment: GCM155R71H104KE02D)
R2  ValueDisplayed: 10.0k  [0402L]  (hidden comment: CRCW040210K0FKED)
R14  ValueDisplayed: 10.0k  [0402L]  (hidden comment: CRCW040210K0FKED)
R25  value 0  [FP-ERJ-2GE0R00X_0402-MFG]  (hidden comment: ERJ-2GE0R00X)
R29  value 0  [FP-ERJ-2GE0R00X_0402-MFG]  (hidden comment: ERJ-2GE0R00X)
R55  value 0  [FP-ERJ-2GE0R00X_0402-MFG]  (hidden comment: ERJ-2GE0R00X)
R56  value 0  [FP-ERJ-2GE0R00X_0402-MFG]  (hidden comment: ERJ-2GE0R00X)
R94  ValueDisplayed: 10.0k  [0402L]  (hidden comment: CRCW040210K0FKED)
R97  ValueDisplayed: 10.0k  [0402L]  (hidden comment: CRCW040210K0FKED)
R98  ValueDisplayed: 10.0k  [0402L]  (hidden comment: CRCW040210K0FKED)
R101  ValueDisplayed: 10.0k  [0402L]  (hidden comment: CRCW040210K0FKED)
R103  ValueDisplayed: 10.0k  [0402L]  (hidden comment: CRCW040210K0FKED)
R104  ValueDisplayed: 10.0k  [0402L]  (hidden comment: CRCW040210K0FKED)
R105  ValueDisplayed: 10.0k  [0402L]  (hidden comment: CRCW040210K0FKED)
R106  ValueDisplayed: 10.0k  [0402L]  (hidden comment: CRCW040210K0FKED)
R107  ValueDisplayed: 10.0k  [0402L]  (hidden comment: CRCW040210K0FKED)
R108  value 0  [FP-ERJ-2GE0R00X_0402-MFG]  (hidden comment: ERJ-2GE0R00X)
R109  value 0  [FP-ERJ-2GE0R00X_0402-MFG]  (hidden comment: ERJ-2GE0R00X)
R110  value 0  [FP-ERJ-2GE0R00X_0402-MFG]  (hidden comment: ERJ-2GE0R00X)
R111  value 0  [FP-ERJ-2GE0R00X_0402-MFG]  (hidden comment: ERJ-2GE0R00X)
R112  ValueDisplayed: 10.0k  [0402L]  (hidden comment: CRCW040210K0FKED)
R113  ValueDisplayed: 10.0k  [0402L]  (hidden comment: CRCW040210K0FKED)
R114  ValueDisplayed: 10.0k  [0402L]  (hidden comment: CRCW040210K0FKED)
R115  ValueDisplayed: 10.0k  [0402L]  (hidden comment: CRCW040210K0FKED)
R116  ValueDisplayed: 10.0k  [0402L]  (hidden comment: CRCW040210K0FKED)
R117  ValueDisplayed: 10.0k  [0402L]  (hidden comment: CRCW040210K0FKED)
R134  value 10m  [FP-WSL1206R0100FEB_1206-MFG]  (hidden comment: WSL1206R0100FEB)
R135  ValueDisplayed: 10.0k  [0402L]  (hidden comment: CRCW040210K0FKED)
R136  ValueDisplayed: 10.0k  [0402L]  (hidden comment: CRCW040210K0FKED)
R137  value 0  [FP-ERJ-2GE0R00X_0402-MFG]  (hidden comment: ERJ-2GE0R00X)
R139  value 0  [FP-ERJ-2GE0R00X_0402-MFG]  (hidden comment: ERJ-2GE0R00X)
R142  ValueDisplayed: 10.0k  [0402L]  (hidden comment: CRCW040210K0FKED)
R148  ValueDisplayed: 10.0k  [0402L]  (hidden comment: CRCW040210K0FKED)
R150  ValueDisplayed: 10.0k  [0402L]  (hidden comment: CRCW040210K0FKED)
R151  ValueDisplayed: 10.0k  [0402L]  (hidden comment: CRCW040210K0FKED)
R157  ValueDisplayed: 10.0k  [0402L]  (hidden comment: CRCW040210K0FKED)
R158  ValueDisplayed: 10.0k  [0402L]  (hidden comment: CRCW040210K0FKED)
R159  value 0  [FP-ERJ-2GE0R00X_0402-MFG]  (hidden comment: ERJ-2GE0R00X)
R160  value 0  [FP-ERJ-2GE0R00X_0402-MFG]  (hidden comment: ERJ-2GE0R00X)
R161  ValueDisplayed: 10.0k  [0402L]  (hidden comment: CRCW040210K0FKED)
R162  ValueDisplayed: 10.0k  [0402L]  (hidden comment: CRCW040210K0FKED)
R192  value 40m  [FP-WSL1206R0400FEB_1206-MFG]  (hidden comment: WSL1206R0400FEB)
R193  value 20m  [FP-WSL1206R0200FEB_1206-MFG]  (hidden comment: WSL1206R0200FEB)
R200  value 40m  [FP-WSL1206R0400FEB_1206-MFG]  (hidden comment: WSL1206R0400FEB)
R283  ValueDisplayed: 10.0k  [0402L]  (hidden comment: CRCW040210K0FKED)
U3  TMP451AQDQFRQ1  [DQF0008A]
U6  INA228AIDGST  [DGS0010A-MFG]
U7  INA228AIDGST  [DGS0010A-MFG]
U8  INA228AIDGST  [DGS0010A-MFG]
U11  CAT24C08WI-GT3  [SOIC-8]
U25  INA228AIDGST  [DGS0010A-MFG]

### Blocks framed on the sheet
CURRENT SENSOR- 1V8: C57 R2 R14 R25 R29 R94 R101 R103 U6
CURRENT SENSE RESISTORS: R134 R192 R193 R200
CURRENT SENSOR- 3V3: C58 R104 R105 R108 R110 R112-R114 U7
TEMPERATURE SENSOR: C36 R55 R56 R151 R283 U3
CURRENT SENSOR- 1V2: C59 R106 R107 R109 R111 R115-R117 U8
EEPROM: C65 R97 R98 R157-R162 U11
CURRENT SENSOR- RF_1V2: C133 R135-R137 R139 R142 R148 R150 U25

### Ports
1V2_VIN+ (in), 1V2_VIN+ (out), 1V2_VIN- (in), 1V2_VIN- (out), 1V8_VIN+ (in), 1V8_VIN+ (out), 1V8_VIN- (in), 1V8_VIN- (out), 3V3_VIN+ (in), 3V3_VIN+ (out), 3V3_VIN- (in), 3V3_VIN- (out), I2C_SCL (bidir), I2C_SDA (bidir), RF_1V2_VIN+ (in), RF_1V2_VIN+ (out), RF_1V2_VIN- (in), RF_1V2_VIN- (out)

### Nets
GND: C36.2 C57.2 C58.2 C59.2 C65.2 C133.2 R101.1 R103.1 R113.1 R114.1 R116.1 R117.1 R148.1 R150.1 R158.1 R162.1 U3.2(D+) U3.3(D-) U3.5(GND) U6.7(GND) U7.7(GND) U8.7(GND) U11.4(VSS) U25.7(GND)
RADAR_1P2_RF: R134.2 U25.9(IN-) ; port RF_1V2_VIN-
RADAR_1V2: R193.2 U8.9(IN-) ; port 1V2_VIN-
RADAR_1V8: R192.2 U6.9(IN-) ; port 1V8_VIN-
RADAR_3V3: R200.2 U7.9(IN-) ; port 3V3_VIN-
REG_1V2: R193.1 U8.8(VBUS) U8.10(IN+) ; port 1V2_VIN+
REG_1V8: R192.1 U6.8(VBUS) U6.10(IN+) ; port 1V8_VIN+
REG_RF_1V2: R134.1 U25.8(VBUS) U25.10(IN+) ; port RF_1V2_VIN+
VCC_3V3: C36.1 C57.1 C58.1 C59.1 C65.1 C133.1 R2.2 R14.2 R94.1 R97.2 R98.2 R104.2 R105.2 R106.2 R107.2 R112.1 R115.1 R135.2 R136.2 R142.1 R151.1 R157.2 R161.2 R200.1 R283.1 U3.1(V+) U6.6(VS) U7.6(VS) U7.8(VBUS) U7.10(IN+) U8.6(VS) U11.8(VCC) U25.6(VS) ; port 3V3_VIN+
EEPROM_A2: R161.1 R162.2 U11.3(A2)
EEPROM_WPn: R157.1 R158.2 U11.7(WP)
I2C_SCL: R25.2 R55.2 R97.1 R108.2 R109.2 R137.2 R159.2 ; port I2C_SCL
I2C_SDA: R29.2 R56.2 R98.1 R110.2 R111.2 R139.2 R160.2 ; port I2C_SDA
NetR2_1: R2.1 R101.2 U6.2(A0)
NetR14_1: R14.1 R103.2 U6.1(A1)
NetR25_1: R25.1 U6.5(SCL)
NetR29_1: R29.1 U6.4(SDA)
NetR55_1: R55.1 U3.8(SCL)
NetR56_1: R56.1 U3.7(SDA)
NetR94_2: R94.2 U6.3(~{ALERT})
NetR104_1: R104.1 R113.2 U7.2(A0)
NetR105_1: R105.1 R114.2 U7.1(A1)
NetR106_1: R106.1 R116.2 U8.2(A0)
NetR107_1: R107.1 R117.2 U8.1(A1)
NetR108_1: R108.1 U7.5(SCL)
NetR109_1: R109.1 U8.5(SCL)
NetR110_1: R110.1 U7.4(SDA)
NetR111_1: R111.1 U8.4(SDA)
NetR112_2: R112.2 U7.3(~{ALERT})
NetR115_2: R115.2 U8.3(~{ALERT})
NetR135_1: R135.1 R148.2 U25.2(A0)
NetR136_1: R136.1 R150.2 U25.1(A1)
NetR137_1: R137.1 U25.5(SCL)
NetR139_1: R139.1 U25.4(SDA)
NetR142_2: R142.2 U25.3(~{ALERT})
NetR151_2: R151.2 U3.6(~{ALERT}_~{THERM2})
NetR159_1: R159.1 U11.6(SCL)
NetR160_1: R160.1 U11.5(SDA)
NetR283_2: R283.2 U3.4(~{THERM})

Not connected (* = marked no-connect by the designer): U11 1(NC)* 2(NC)*

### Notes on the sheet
- I2C ADDRESS : 1000 000
- (near R134) Design Note: 'Generic No ERCs' were placed intentionally on either sides of Current sense resistors
- I2C ADDRESS : 1000 101
- I2C ADDRESS : 1001 100
- I2C ADDRESS : 1000 001
- I2C ADDRESS : 1010 0XX
- I2C ADDRESS : 1000 100

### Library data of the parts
C36 C57-C59 C65 C133 = CMP-0006356-2: as C31 on sheet PROC207A_Chip_Power
R2 R14 R94 R97 R98 R101 R103-R107 R112-R117 R135 R136 R142 R148 R150 R151 R157 R158 R161 R162 R283 = CMP-0025958-3: RES, 10.0 k, 1%, 0.063 W, AEC-Q200 Grade 0, 0402; Manufacturer: Vishay-Dale; Power_W: 63mW; TempCo: 100 ppm/C; Value_Code: 10k0; Value: 10.0k; EIA_Code: E96; Res_ohm: 10k; SizeX_mm: 1; SizeY_mm: 0.5; SizeZ_mm: 0.6; Value2: 0.063W; AEC Qualified: Y; VDC_V: 50V; AEC Category: Q200; AEC Grade: 0
R25 R29 R55 R56 R108-R111 R137 R139 R159 R160 = CMP-0002710-1: 0 Ohms Jumper Chip Resistor 0402 (1005 Metric) Automotive AEC-Q200 Thick Film; Manufacturer: Panasonic; SizeZ_mm: 0.4mm; AEC Qualified: Yes; AEC Grade: Grade 0; Power: 100mW
R134 = CMP-0121430-1: 10 mOhms ±1% 0.25W, 1/4W Chip Resistor Automotive AEC-Q200, Current Sense, Moisture Resistant, Pulse Withstanding Metal Element; Manufacturer: Vishay Dale; AEC Grade: Grade 0; AEC Qualified: Yes; Power_W: 250mW; SizeZ_mm: 0.889mm; TempCo: 75ppm/°C; Category 5A00970A6D5C81C7: Uncategorized; Category 5C6A91606D4187Ad: Resistors; Category 7542B8484461Ae85: Passive Components; Category Cd01000Bfc2916C6: Single Components; Voltage: 50mV
R192 R200 = CMP-0098431-1: 40 mOhms ±1% 0.25W, 1/4W Chip Resistor Automotive AEC-Q200, Current Sense, Moisture Resistant, Pulse Withstanding Metal Element; Manufacturer: Vishay; AEC Grade: Grade 0; AEC Qualified: Yes; Power_W: 250mW; SizeZ_mm: 0.889mm; TempCo: 75ppm/°C
R193 = CMP-0098430-1: Res Metal Strip 1206 0.02 Ohm 1% 1/4W ±75ppm/°C Molded SMD SMD T/R; Manufacturer: Vishay Dale; AEC Grade: Grade 0; AEC Qualified: Yes; Power_W: 250mW; SizeZ_mm: 0.889mm; Category 5C6A91606D4187Ad: Resistors; Category 7542B8484461Ae85: Passive Components; Category Cd01000Bfc2916C6: Single Components
U3 = CMP-0074317-1: Automotive Grade, 1.7V Remote and Local Temp Sensor with N-Factor, Filtering and Series-R Correction, DQF0008A (WSON-8); Alternate Manufacturer: Texas Instruments; SizeAreaWB_mm2: 9.0; U/M: EA; SizeZ_mm: 0.8; SizeX_mm: 2.0; SizeArea_mm2: 4.0; CompType: IC
U6-U8 U25 = CMP-0098432-1: Current Sense Amplifier 1 Circuit 10-VSSOP; Manufacturer: Texas Instruments; SizeZ_mm: 1.1mm; AEC Qualified: No; Input Bias Current: 0.01uA; Input Offset Voltage: 1mV; Max Supply Voltage: 5.5V; Min Supply Voltage: 2.7V; Nominal Supply Current: 640uA; Number Of Channels: 1; Standoff Height: 0.05mm; TaMax_C: +125°C; TaMin_C: -40°C; TJmax_C: +150°C
U11 = CMP-0005309-2: IC, EEPROM, 8KBIT, 400KHZ, 8SOIC; Manufacturer: ON Semiconductor; SizeAreaWB_mm2: 55.131; SizeZ_mm: 1.75; SizeX_mm: 5.99; SizeY_mm: 4.9; SizeArea_mm2: 29.351

## Sheet PROC207A_Analog_Mux_SOP_Ctrl.SchDoc: ANALOG_MUX_SOP_CTRL
size 431 x 279 mm; Date: Not shown in title block; ApprovedBy: Not shown in title block; CheckedBy: Not shown in title block; Author: Not shown in title block; CompanyName: Not shown in title block; DrawnBy: Mistral; Engineer: Not shown in title block; Organization: Not shown in title block; Address1: Not shown in title block; Address2: Not shown in title block; Address3: Not shown in title block; Address4: Not shown in title block; DocumentNumber: 9; Revision: Use project parameter SCH_Rev; SheetNumber: 9; SheetTotal: 17; PageSetup: Record=PageOptions¦CenterHorizontal=True¦CenterVertical=True¦PrintScale=1.00¦XCorrection=1.00¦YCorrection=1.00¦PrintKind=0¦BorderSize=5000000¦LeftOffset=0¦BottomOffset=0¦Orientation=2¦PaperLength=1000¦PaperWidth=1000¦Scale=100¦PaperSource=15¦PrintQuality=600¦MediaType=1¦DitherType=10¦PaperKind=Letter¦PrintScaleMode=1

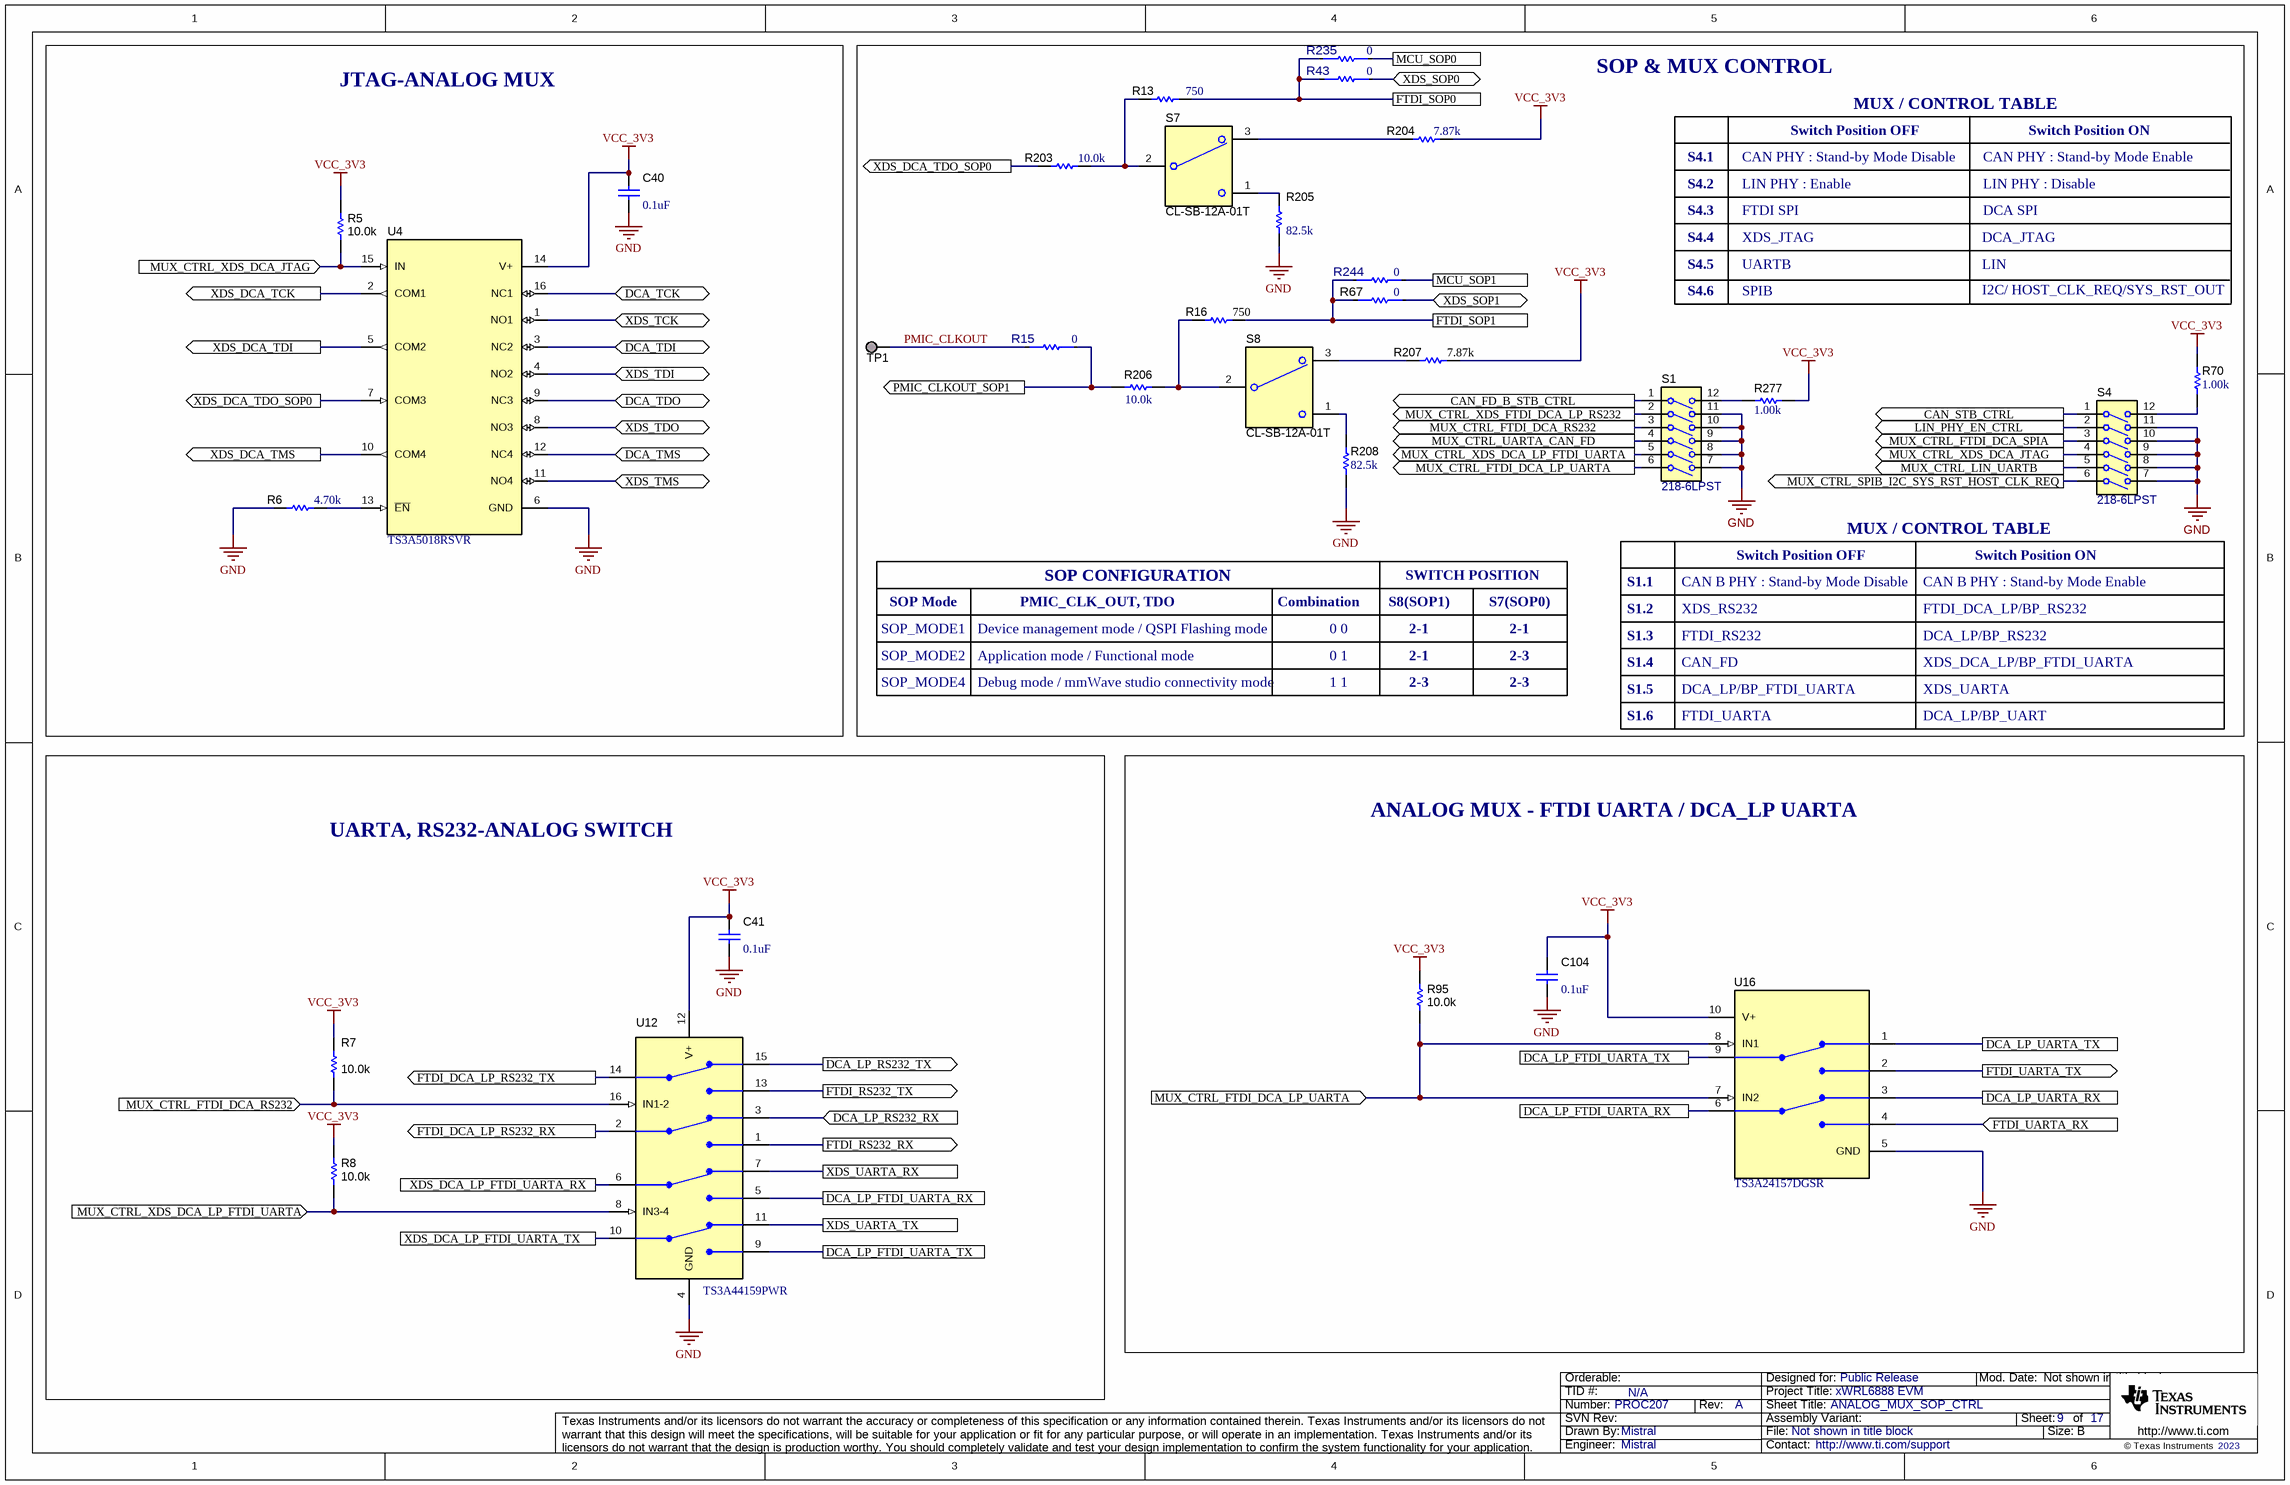
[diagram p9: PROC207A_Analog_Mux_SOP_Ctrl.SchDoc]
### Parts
C40  ValueDisplayed: 0.1uF  [0402]  (hidden comment: GCM155R71H104KE02D)
C41  ValueDisplayed: 0.1uF  [0402]  (hidden comment: GCM155R71H104KE02D)
C104  ValueDisplayed: 0.1uF  [0402]  (hidden comment: GCM155R71H104KE02D)
R5  ValueDisplayed: 10.0k  [0402L]  (hidden comment: CRCW040210K0FKED)
R6  ValueDisplayed: 4.70k  [0402]  (hidden comment: RC0402FR-074K7L)
R7  ValueDisplayed: 10.0k  [0402L]  (hidden comment: CRCW040210K0FKED)
R8  ValueDisplayed: 10.0k  [0402L]  (hidden comment: CRCW040210K0FKED)
R13  ValueDisplayed: 750  [0402L]  (hidden comment: CRCW0402750RFKED)
R15  value 0  [FP-ERJ-2GE0R00X_0402-MFG]  (hidden comment: ERJ-2GE0R00X)
R16  ValueDisplayed: 750  [0402L]  (hidden comment: CRCW0402750RFKED)
R43  value 0  [FP-ERJ-2GE0R00X_0402-MFG]  (hidden comment: ERJ-2GE0R00X)
R67  value 0  [FP-ERJ-2GE0R00X_0402-MFG]  (hidden comment: ERJ-2GE0R00X)
R70  ValueDisplayed: 1.00k  [0402]  (hidden comment: ERJ-2RKF1001X)
R95  ValueDisplayed: 10.0k  [0402L]  (hidden comment: CRCW040210K0FKED)
R203  ValueDisplayed: 10.0k  [0402L]  (hidden comment: CRCW040210K0FKED)
R204  ValueDisplayed: 7.87k  [0402L]  (hidden comment: CRCW04027K87FKED)
R205  ValueDisplayed: 82.5k  [0402L]  (hidden comment: CRCW040282K5FKED)
R206  ValueDisplayed: 10.0k  [0402L]  (hidden comment: CRCW040210K0FKED)
R207  ValueDisplayed: 7.87k  [0402L]  (hidden comment: CRCW04027K87FKED)
R208  ValueDisplayed: 82.5k  [0402L]  (hidden comment: CRCW040282K5FKED)
R235  value 0  [FP-ERJ-2GE0R00X_0402-MFG]  (hidden comment: ERJ-2GE0R00X)
R244  value 0  [FP-ERJ-2GE0R00X_0402-MFG]  (hidden comment: ERJ-2GE0R00X)
R277  ValueDisplayed: 1.00k  [0402]  (hidden comment: ERJ-2RKF1001X)
S1  218-6LPST  [SW_218-6LPST]
S4  218-6LPST  [SW_218-6LPST]
S7  CL-SB-12A-01T  [SW_CL-SB-12A-01]
S8  CL-SB-12A-01T  [SW_CL-SB-12A-01]
TP1  TESTPOINT  [TP_25MIL-SMT]  (value not drawn)  (no BOM)
U4  TS3A5018RSVR  [RSV0016A]
U12  TS3A44159PWR  [PW0016A_N]
U16  TS3A24157DGSR  [DGS0010A_N]

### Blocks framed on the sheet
JTAG-ANALOG MUX: C40 R5 R6 U4
SOP & MUX CONTROL: R13 R15 R16 R43 R67 R70 R203-R208 R235 R244 R277 S1 S4 S7 S8 TP1
UARTA, RS232-ANALOG SWITCH: C41 R7 R8 U12
ANALOG MUX - FTDI UARTA / DCA_LP UARTA: C104 R95 U16

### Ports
CAN_FD_B_STB_CTRL (out), CAN_STB_CTRL (out), DCA_LP_FTDI_UARTA_RX, DCA_LP_FTDI_UARTA_TX, DCA_LP_RS232_RX (in), DCA_LP_RS232_TX (out), DCA_LP_UARTA_RX, DCA_LP_UARTA_TX, DCA_TCK (bidir), DCA_TDI (bidir), DCA_TDO (bidir), DCA_TMS (bidir), FTDI_DCA_LP_RS232_RX (out), FTDI_DCA_LP_RS232_TX (out), FTDI_RS232_RX (out), FTDI_RS232_TX (out), FTDI_SOP0, FTDI_SOP1, FTDI_UARTA_RX (in), FTDI_UARTA_TX (out), LIN_PHY_EN_CTRL (out), MCU_SOP0, MCU_SOP1, MUX_CTRL_FTDI_DCA_LP_UARTA (in), MUX_CTRL_FTDI_DCA_LP_UARTA (out), MUX_CTRL_FTDI_DCA_RS232 (in), MUX_CTRL_FTDI_DCA_RS232 (out), MUX_CTRL_FTDI_DCA_SPIA (out), MUX_CTRL_LIN_UARTB (out), MUX_CTRL_SPIB_I2C_SYS_RST_HOST_CLK_REQ (out), MUX_CTRL_UARTA_CAN_FD (out), MUX_CTRL_XDS_DCA_JTAG (in), MUX_CTRL_XDS_DCA_JTAG (out), MUX_CTRL_XDS_DCA_LP_FTDI_UARTA (in), MUX_CTRL_XDS_DCA_LP_FTDI_UARTA (out), MUX_CTRL_XDS_FTDI_DCA_LP_RS232 (out), PMIC_CLKOUT_SOP1 (out), XDS_DCA_LP_FTDI_UARTA_RX, XDS_DCA_LP_FTDI_UARTA_TX, XDS_DCA_TCK (out), XDS_DCA_TDI (out), XDS_DCA_TDO_SOP0 (out), XDS_DCA_TMS (out), XDS_SOP0 (bidir), XDS_SOP1 (bidir), XDS_TCK (bidir), XDS_TDI (bidir), XDS_TDO (bidir), XDS_TMS (bidir), XDS_UARTA_RX, XDS_UARTA_TX

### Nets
GND: C40.2 C41.2 C104.2 R6.1 R205.1 R208.1 S1.7(6A) S1.8(5A) S1.9(4A) S1.10(3A) S1.11(2A) S4.7(6A) S4.8(5A) S4.9(4A) S4.10(3A) S4.11(2A) U4.6(GND) U12.4(GND) U16.5(GND)
VCC_3V3: C40.1 C41.1 C104.1 R5.2 R7.2 R8.2 R70.2 R95.2 R204.2 R207.2 R277.2 U4.14(V+) U12.12(V+) U16.10(V+)
CAN_FD_B_STB_CTRL: S1.1 ; port CAN_FD_B_STB_CTRL
CAN_STB_CTRL: S4.1 ; port CAN_STB_CTRL
DCA_LP_FTDI_UARTA_RX: U12.5(NO3) U16.6(COM2) ; port DCA_LP_FTDI_UARTA_RX
DCA_LP_FTDI_UARTA_TX: U12.9(NO4) U16.9(COM1) ; port DCA_LP_FTDI_UARTA_TX
DCA_LP_RS232_RX: U12.3(NC2) ; port DCA_LP_RS232_RX
DCA_LP_RS232_TX: U12.15(NC1) ; port DCA_LP_RS232_TX
DCA_LP_UARTA_RX: U16.3(NC2) ; port DCA_LP_UARTA_RX
DCA_LP_UARTA_TX: U16.1(NC1) ; port DCA_LP_UARTA_TX
DCA_TCK: U4.16(NC1) ; port DCA_TCK
DCA_TDI: U4.3(NC2) ; port DCA_TDI
DCA_TDO: U4.9(NC3) ; port DCA_TDO
DCA_TMS: U4.12(NC4) ; port DCA_TMS
FTDI_DCA_LP_RS232_RX: U12.2(COM2) ; port FTDI_DCA_LP_RS232_RX
FTDI_DCA_LP_RS232_TX: U12.14(COM1) ; port FTDI_DCA_LP_RS232_TX
FTDI_RS232_RX: U12.1(NO2) ; port FTDI_RS232_RX
FTDI_RS232_TX: U12.13(NO1) ; port FTDI_RS232_TX
FTDI_SOP0: R13.1 R43.2 R235.1 ; port FTDI_SOP0
FTDI_SOP1: R16.1 R67.2 R244.1 ; port FTDI_SOP1
FTDI_UARTA_RX: U16.4(NO2) ; port FTDI_UARTA_RX
FTDI_UARTA_TX: U16.2(NO1) ; port FTDI_UARTA_TX
LIN_PHY_EN_CTRL: S4.2 ; port LIN_PHY_EN_CTRL
MCU_SOP0: R235.2 ; port MCU_SOP0
MCU_SOP1: R244.2 ; port MCU_SOP1
MUX_CTRL_FTDI_DCA_LP_UARTA: R95.1 S1.6 U16.7(IN2) U16.8(IN1) ; port MUX_CTRL_FTDI_DCA_LP_UARTA
MUX_CTRL_FTDI_DCA_RS232: R7.1 S1.3 U12.16(IN1-2) ; port MUX_CTRL_FTDI_DCA_RS232
MUX_CTRL_FTDI_DCA_SPIA: S4.3 ; port MUX_CTRL_FTDI_DCA_SPIA
MUX_CTRL_LIN_UARTB: S4.5 ; port MUX_CTRL_LIN_UARTB
MUX_CTRL_SPIB_I2C_SYS_RST_HOST_CLK_REQ: S4.6 ; port MUX_CTRL_SPIB_I2C_SYS_RST_HOST_CLK_REQ
MUX_CTRL_UARTA_CAN_FD: S1.4 ; port MUX_CTRL_UARTA_CAN_FD
MUX_CTRL_XDS_DCA_JTAG: R5.1 S4.4 U4.15(IN) ; port MUX_CTRL_XDS_DCA_JTAG
MUX_CTRL_XDS_DCA_LP_FTDI_UARTA: R8.1 S1.5 U12.8(IN3-4) ; port MUX_CTRL_XDS_DCA_LP_FTDI_UARTA
MUX_CTRL_XDS_FTDI_DCA_LP_RS232: S1.2 ; port MUX_CTRL_XDS_FTDI_DCA_LP_RS232
PMIC_CLKOUT: R15.2 TP1.1
PMIC_CLKOUT_SOP1: R15.1 R206.1 ; port PMIC_CLKOUT_SOP1
XDS_DCA_LP_FTDI_UARTA_RX: U12.6(COM3) ; port XDS_DCA_LP_FTDI_UARTA_RX
XDS_DCA_LP_FTDI_UARTA_TX: U12.10(COM4) ; port XDS_DCA_LP_FTDI_UARTA_TX
XDS_DCA_TCK: U4.2(COM1) ; port XDS_DCA_TCK
XDS_DCA_TDI: U4.5(COM2) ; port XDS_DCA_TDI
XDS_DCA_TDO_SOP0: R203.1 U4.7(COM3) ; port XDS_DCA_TDO_SOP0
XDS_DCA_TMS: U4.10(COM4) ; port XDS_DCA_TMS
XDS_SOP0: R43.1 ; port XDS_SOP0
XDS_SOP1: R67.1 ; port XDS_SOP1
XDS_TCK: U4.1(NO1) ; port XDS_TCK
XDS_TDI: U4.4(NO2) ; port XDS_TDI
XDS_TDO: U4.8(NO3) ; port XDS_TDO
XDS_TMS: U4.11(NO4) ; port XDS_TMS
XDS_UARTA_RX: U12.7(NC3) ; port XDS_UARTA_RX
XDS_UARTA_TX: U12.11(NC4) ; port XDS_UARTA_TX
NetR6_2: R6.2 U4.13(~{EN})
NetR13_2: R13.2 R203.2 S7.2(COM)
NetR16_2: R16.2 R206.2 S8.2(COM)
NetR70_1: R70.1 S4.12(1A)
NetR204_1: R204.1 S7.3
NetR205_2: R205.2 S7.1
NetR207_1: R207.1 S8.3
NetR208_2: R208.2 S8.1
NetR277_1: R277.1 S1.12(1A)

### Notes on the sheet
- MUX / CONTROL TABLE
- S4.1
- CAN PHY : Stand-by Mode Disable
- Switch Position OFF
- CAN PHY : Stand-by Mode Enable
- Switch Position ON
- S4.2
- S4.3
- S4.4
- LIN PHY : Enable
- FTDI SPI
- XDS_JTAG
- DCA_JTAG
- LIN PHY : Disable
- DCA SPI
- S4.5
- S4.6
- UARTB
- SPIB
- LIN
- I2C/ HOST_CLK_REQ/SYS_RST_OUT
- SOP CONFIGURATION
- SWITCH POSITION
- SOP_MODE1
- SOP Mode
- Device management mode / QSPI Flashing mode
- PMIC_CLK_OUT, TDO
- Combination
- 0 0
- S8(SOP1)
- 2-1
- S7(SOP0)
- S1.3
- S1.2
- S1.1
- FTDI_RS232
- XDS_RS232
- CAN B PHY : Stand-by Mode Disable
- DCA_LP/BP_RS232
- FTDI_DCA_LP/BP_RS232
- CAN B PHY : Stand-by Mode Enable
- SOP_MODE2
- SOP_MODE4
- Application mode / Functional mode
- Debug mode / mmWave studio connectivity mode
- 0 1
- 1 1
- 2-3
- S1.4
- S1.5
- DCA_LP/BP_FTDI_UARTA
- CAN_FD
- XDS_UARTA
- XDS_DCA_LP/BP_FTDI_UARTA
- S1.6
- FTDI_UARTA
- DCA_LP/BP_UART

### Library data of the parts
C40 C41 C104 = CMP-0006356-2: CAP, CERM, 0.1 uF, 50 V, +/- 10%, X7R, AEC-Q200 Grade 1, 0402; Manufacturer: MuRata; TaMin_C: -55°C; Polarized: N; SizeAreaWB_mm2: 3; U/M: EA; Value: 0.1uF; TaMax_C: 125°C; SizeZ_mm: 0.6; SizeX_mm: 1; SizeY_mm: 0.5; Value2: 50V; AEC Qualified: Y; Cap_F: 100nF; AEC Category: Q200; Value1: Unknown
R5 R7 R8 R95 R203 R206 = CMP-0025958-3: as R2 on sheet PROC207A_Temp_Current_sensors_EPROM
R6 = CMP-0026739-1: RES, 4.70 k, 1%, 0.0625 W, 0402; Manufacturer: Yageo America; Power_W: 62.5mW; TempCo: 100 ppm/C; Value_Code: 4k70; Value: 4.70k; Res_ohm: 4.7k; SizeX_mm: 1; SizeY_mm: 0.5; SizeZ_mm: 0.6; AEC Qualified: N; VDC_V: 50V; AEC Category: Q200; U/M: EA
R13 R16 = CMP-0026542-2: RES, 750, 1%, 0.063 W, AEC-Q200 Grade 0, 0402; Manufacturer: Vishay-Dale; Power_W: 63mW; TempCo: 100 ppm/C; Value_Code: 750R; Value: 750; EIA_Code: E96; SizeX_mm: 1; SizeY_mm: 0.5; SizeZ_mm: 0.6; Value2: 0.063W; AEC Qualified: Y; VDC_V: 50V; AEC Grade: 0; AEC Category: Q200
R15 R43 R67 R235 R244 = CMP-0002710-1: as R25 on sheet PROC207A_Temp_Current_sensors_EPROM
R70 R277 = CMP-0026657-1: RES, 1.00 k, 1%, 0.1 W, 0402; Manufacturer: Panasonic; Power_W: 100mW; TempCo: 100 ppm/C; Value_Code: 1k00; Value: 1.00k; EIA_Code: E96; Res_ohm: 1k; SizeX_mm: 1; SizeY_mm: 0.5; SizeZ_mm: 0.6; Value2: 0.1W; VDC_V: 50V; AEC Category: Q200; U/M: EA
R204 R207 = CMP-0026557-2: RES, 7.87 k, 1%, 0.063 W, AEC-Q200 Grade 0, 0402; Manufacturer: Vishay-Dale; Power_W: 63mW; TempCo: 100 ppm/C; Value_Code: 7k87; Value: 7.87k; EIA_Code: E96; SizeX_mm: 1; SizeY_mm: 0.5; SizeZ_mm: 0.6; Value2: 0.063W; AEC Qualified: Y; VDC_V: 50V; AEC Grade: 0; AEC Category: Q200
R205 R208 = CMP-0026574-2: RES, 82.5 k, 1%, 0.063 W, AEC-Q200 Grade 0, 0402; Manufacturer: Vishay-Dale; Power_W: 63mW; TempCo: 100 ppm/C; Value_Code: 82k5; Value: 82.5k; EIA_Code: E96; SizeX_mm: 1; SizeY_mm: 0.5; SizeZ_mm: 0.6; Value2: 0.063W; AEC Qualified: Y; VDC_V: 50V; AEC Grade: 0; AEC Category: Q200
S1 S4 = CMP-0002304-1: Switch, SPST, Slide, Off-On, 6 Pos, 0.025A, 24V, SMD; Manufacturer: CTS Electrocomponents; CurrentRating_mA: 25A; PositionCount: 6; SizeX_mm: 8.44; SizeY_mm: 8.79; SizeZ_mm: 2.65; SizeArea_mm2: 74.1876; SizeAreaWB_mm2: 112.6476
S7 S8 = CMP-0002183-2: Switch, Slide, SPDT, 0.2A, J Lead, SMD; Manufacturer: Copal Electronics; CurrentRating_mA: 200A; SwitchFunction: On-On; VDC_V: 12V; PositionCount: 2
TP1 = CMP-0078143-3: TEST POINT.  No entry in BOM.
U4 = CMP-0067415-1: 10-Ohm Quad SPDT Analog Switch, RSV0016A (UQFN-16); Alternate Manufacturer: Texas Instruments; SizeAreaWB_mm2: 10.08; U/M: EA; SizeZ_mm: 0.55; SizeX_mm: 1.8; SizeY_mm: 2.6; SizeArea_mm2: 4.68; CompType: IC
U12 = CMP-0067412-1: 0.45-Ohm Quad SPDT Analog Switch Quad-Channel 2:1 Multiplexer/Demultiplexer with Two Controls, PW0016A (TSSOP-16); Alternate Manufacturer: Texas Instruments; SizeAreaWB_mm2: 58.8; U/M: EA; SizeZ_mm: 1.2; SizeX_mm: 6.4; SizeY_mm: 5.0; SizeArea_mm2: 32.0; CompType: IC
U16 = CMP-0067410-1: 0.65 Ohm Dual SPDT Analog Switch Dual-Channel 2:1 Multiplexer/Demultiplexer, DGS0010A (VSSOP-10); Alternate Manufacturer: Texas Instruments; SizeAreaWB_mm2: 23.6; U/M: EA; SizeZ_mm: 1.1; SizeX_mm: 4.9; SizeY_mm: 3.0; SizeArea_mm2: 14.7; CompType: IC

## Sheet PROC207A_Analog_MUX_SPI.SchDoc: Analog Mux SPI and UART B
size 431 x 279 mm; Date: Not shown in title block; ApprovedBy: Not shown in title block; CheckedBy: Not shown in title block; Author: Not shown in title block; CompanyName: Not shown in title block; DrawnBy: Mistral; Engineer: Not shown in title block; Organization: Not shown in title block; Address1: Not shown in title block; Address2: Not shown in title block; Address3: Not shown in title block; Address4: Not shown in title block; DocumentNumber: 3; Revision: Use project parameter SCH_Rev; SheetNumber: 10; SheetTotal: 17; PageSetup: Record=PageOptions¦CenterHorizontal=True¦CenterVertical=True¦PrintScale=1.00¦XCorrection=1.00¦YCorrection=1.00¦PrintKind=0¦BorderSize=5000000¦LeftOffset=0¦BottomOffset=0¦Orientation=2¦PaperLength=1000¦PaperWidth=1000¦Scale=100¦PaperSource=15¦PrintQuality=600¦MediaType=1¦DitherType=10¦PaperKind=Letter¦PrintScaleMode=1

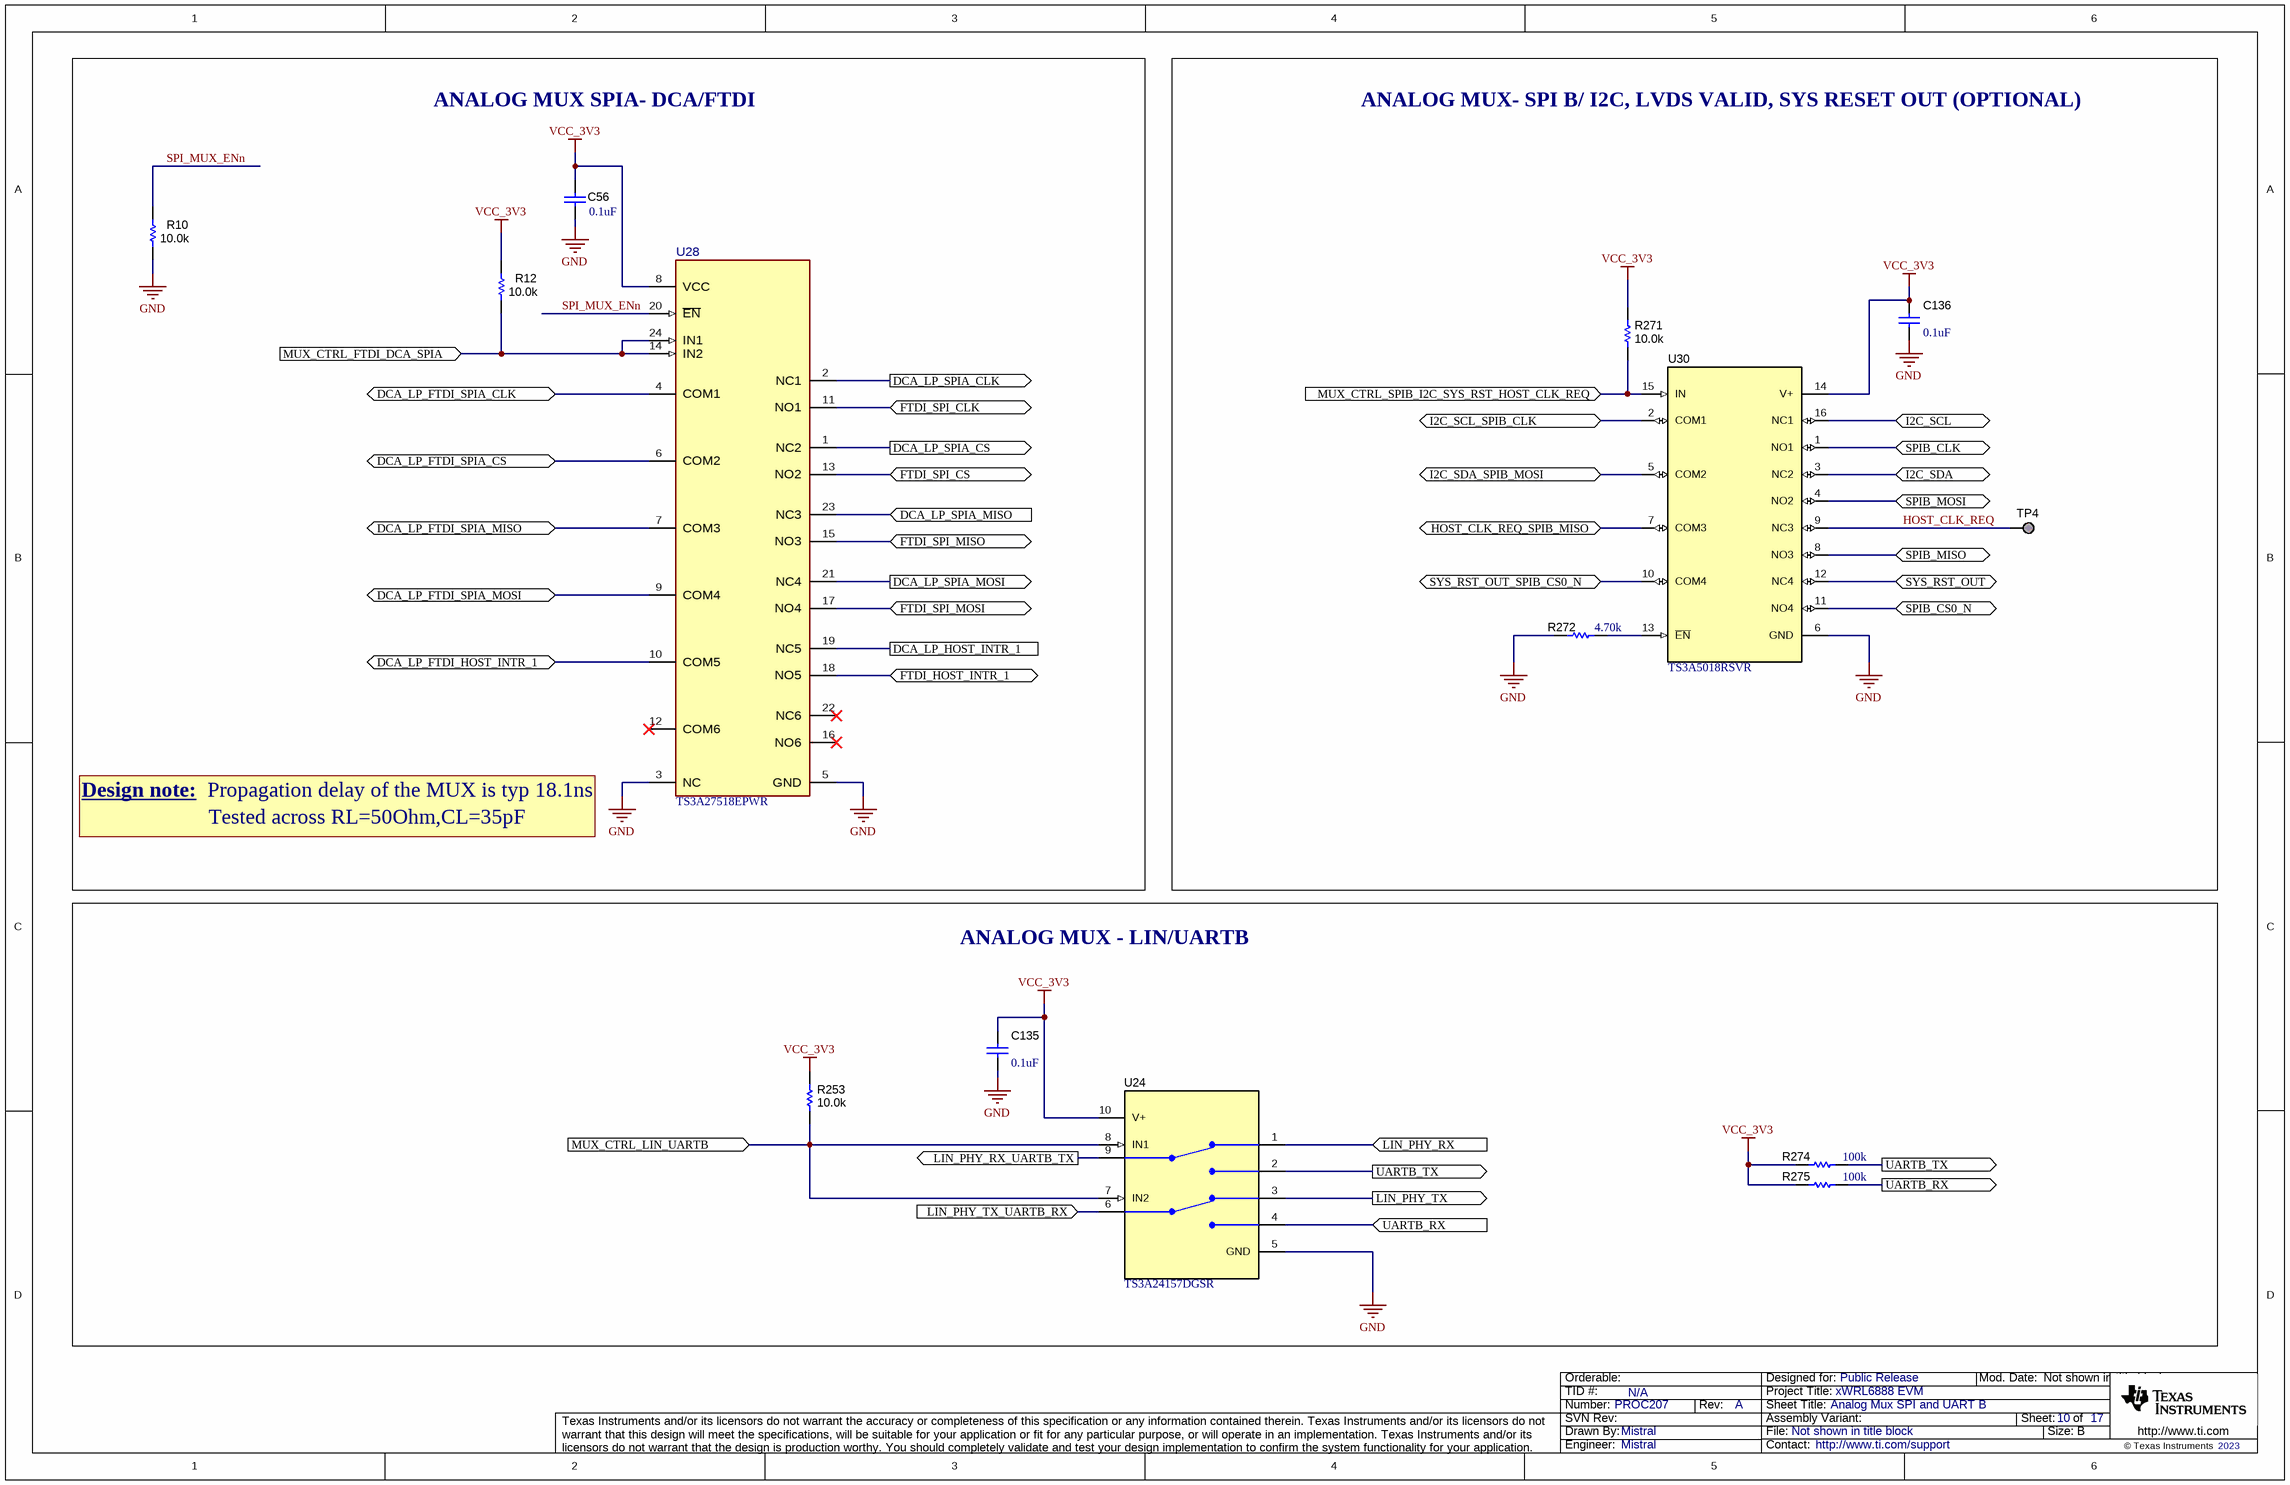
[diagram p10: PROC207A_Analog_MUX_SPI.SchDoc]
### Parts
C56  ValueDisplayed: 0.1uF  [0402]  (hidden comment: GCM155R71H104KE02D)
C135  ValueDisplayed: 0.1uF  [0402]  (hidden comment: GCM155R71H104KE02D)
C136  ValueDisplayed: 0.1uF  [0402]  (hidden comment: GCM155R71H104KE02D)
R10  ValueDisplayed: 10.0k  [0402L]  (hidden comment: CRCW040210K0FKED)
R12  ValueDisplayed: 10.0k  [0402L]  (hidden comment: CRCW040210K0FKED)
R253  ValueDisplayed: 10.0k  [0402L]  (hidden comment: CRCW040210K0FKED)
R271  ValueDisplayed: 10.0k  [0402L]  (hidden comment: CRCW040210K0FKED)
R272  ValueDisplayed: 4.70k  [0402]  (hidden comment: RC0402FR-074K7L)
R274  ValueDisplayed: 100k  [0402L]  (hidden comment: CRCW0402100KFKED)
R275  ValueDisplayed: 100k  [0402L]  (hidden comment: CRCW0402100KFKED)
TP4  TESTPOINT  [TP_25MIL-SMT]  (value not drawn)  (no BOM)
U24  TS3A24157DGSR  [DGS0010A_N]
U28  TS3A27518EPWR  [PW0024A-MFG]
U30  TS3A5018RSVR  [RSV0016A]

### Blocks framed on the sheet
ANALOG MUX- SPI B/ I2C, LVDS VALID, SYS RESET OUT (OPTIONAL): C136 R271 R272 TP4 U30
ANALOG MUX - LIN/UARTB: C135 R253 R274 R275 U24

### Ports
DCA_LP_FTDI_HOST_INTR_1 (bidir), DCA_LP_FTDI_SPIA_CLK (bidir), DCA_LP_FTDI_SPIA_CS (bidir), DCA_LP_FTDI_SPIA_MISO (bidir), DCA_LP_FTDI_SPIA_MOSI (bidir), DCA_LP_HOST_INTR_1, DCA_LP_SPIA_CLK (out), DCA_LP_SPIA_CS (out), DCA_LP_SPIA_MISO (in), DCA_LP_SPIA_MOSI (out), FTDI_HOST_INTR_1 (bidir), FTDI_SPI_CLK (bidir), FTDI_SPI_CS (bidir), FTDI_SPI_MISO (bidir), FTDI_SPI_MOSI (bidir), HOST_CLK_REQ_SPIB_MISO (bidir), I2C_SCL (bidir), I2C_SCL_SPIB_CLK (bidir), I2C_SDA (bidir), I2C_SDA_SPIB_MOSI (bidir), LIN_PHY_RX (in), LIN_PHY_RX_UARTB_TX (out), LIN_PHY_TX (out), LIN_PHY_TX_UARTB_RX (in), MUX_CTRL_FTDI_DCA_SPIA (in), MUX_CTRL_LIN_UARTB (in), MUX_CTRL_SPIB_I2C_SYS_RST_HOST_CLK_REQ (in), SPIB_CLK (bidir), SPIB_CS0_N (bidir), SPIB_MISO (bidir), SPIB_MOSI (bidir), SYS_RST_OUT (bidir), SYS_RST_OUT_SPIB_CS0_N (bidir), UARTB_RX (in), UARTB_RX (out), UARTB_TX (out)

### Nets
GND: C56.2 C135.2 C136.2 R10.2 R272.1 U24.5(GND) U28.3(NC) U28.5(GND) U30.6(GND)
VCC_3V3: C56.1 C135.1 C136.1 R12.1 R253.2 R271.2 R274.2 R275.2 U24.10(V+) U28.8(VCC) U30.14(V+)
DCA_LP_FTDI_HOST_INTR_1: U28.10(COM5) ; port DCA_LP_FTDI_HOST_INTR_1
DCA_LP_FTDI_SPIA_CLK: U28.4(COM1) ; port DCA_LP_FTDI_SPIA_CLK
DCA_LP_FTDI_SPIA_CS: U28.6(COM2) ; port DCA_LP_FTDI_SPIA_CS
DCA_LP_FTDI_SPIA_MISO: U28.7(COM3) ; port DCA_LP_FTDI_SPIA_MISO
DCA_LP_FTDI_SPIA_MOSI: U28.9(COM4) ; port DCA_LP_FTDI_SPIA_MOSI
DCA_LP_HOST_INTR_1: U28.19(NC5) ; port DCA_LP_HOST_INTR_1
DCA_LP_SPIA_CLK: U28.2(NC1) ; port DCA_LP_SPIA_CLK
DCA_LP_SPIA_CS: U28.1(NC2) ; port DCA_LP_SPIA_CS
DCA_LP_SPIA_MISO: U28.23(NC3) ; port DCA_LP_SPIA_MISO
DCA_LP_SPIA_MOSI: U28.21(NC4) ; port DCA_LP_SPIA_MOSI
FTDI_HOST_INTR_1: U28.18(NO5) ; port FTDI_HOST_INTR_1
FTDI_SPI_CLK: U28.11(NO1) ; port FTDI_SPI_CLK
FTDI_SPI_CS: U28.13(NO2) ; port FTDI_SPI_CS
FTDI_SPI_MISO: U28.15(NO3) ; port FTDI_SPI_MISO
FTDI_SPI_MOSI: U28.17(NO4) ; port FTDI_SPI_MOSI
HOST_CLK_REQ: TP4.1 U30.9(NC3)
HOST_CLK_REQ_SPIB_MISO: U30.7(COM3) ; port HOST_CLK_REQ_SPIB_MISO
I2C_SCL: U30.16(NC1) ; port I2C_SCL
I2C_SCL_SPIB_CLK: U30.2(COM1) ; port I2C_SCL_SPIB_CLK
I2C_SDA: U30.3(NC2) ; port I2C_SDA
I2C_SDA_SPIB_MOSI: U30.5(COM2) ; port I2C_SDA_SPIB_MOSI
LIN_PHY_RX: U24.1(NC1) ; port LIN_PHY_RX
LIN_PHY_RX_UARTB_TX: U24.9(COM1) ; port LIN_PHY_RX_UARTB_TX
LIN_PHY_TX: U24.3(NC2) ; port LIN_PHY_TX
LIN_PHY_TX_UARTB_RX: U24.6(COM2) ; port LIN_PHY_TX_UARTB_RX
MUX_CTRL_FTDI_DCA_SPIA: R12.2 U28.14(IN2) U28.24(IN1) ; port MUX_CTRL_FTDI_DCA_SPIA
MUX_CTRL_LIN_UARTB: R253.1 U24.7(IN2) U24.8(IN1) ; port MUX_CTRL_LIN_UARTB
MUX_CTRL_SPIB_I2C_SYS_RST_HOST_CLK_REQ: R271.1 U30.15(IN) ; port MUX_CTRL_SPIB_I2C_SYS_RST_HOST_CLK_REQ
SPI_MUX_ENn: R10.1 U28.20(~{EN})
SPIB_CLK: U30.1(NO1) ; port SPIB_CLK
SPIB_CS0_N: U30.11(NO4) ; port SPIB_CS0_N
SPIB_MISO: U30.8(NO3) ; port SPIB_MISO
SPIB_MOSI: U30.4(NO2) ; port SPIB_MOSI
SYS_RST_OUT: U30.12(NC4) ; port SYS_RST_OUT
SYS_RST_OUT_SPIB_CS0_N: U30.10(COM4) ; port SYS_RST_OUT_SPIB_CS0_N
UARTB_RX: R275.1 U24.4(NO2) ; port UARTB_RX
UARTB_TX: R274.1 U24.2(NO1) ; port UARTB_TX
NetR272_2: R272.2 U30.13(~{EN})

Not connected (* = marked no-connect by the designer): U28 12(COM6)* 16(NO6)* 22(NC6)*

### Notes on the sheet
- ANALOG MUX SPIA- DCA/FTDI
- Design note:
- Tested across RL=50Ohm,CL=35pF
- (near U28) Propagation delay of the MUX is typ 18.1ns

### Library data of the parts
C56 = CMP-0006356-2: as C31 on sheet PROC207A_Chip_Power
C135 C136 = CMP-0006356-2: as C40 on sheet PROC207A_Analog_Mux_SOP_Ctrl
R10 R12 R253 R271 = CMP-0025958-3: as R2 on sheet PROC207A_Temp_Current_sensors_EPROM
R272 = CMP-0026739-1: as R6 on sheet PROC207A_Analog_Mux_SOP_Ctrl
R274 R275 = CMP-0025950-3: RES, 100 k, 1%, 0.063 W, AEC-Q200 Grade 0, 0402; Manufacturer: Vishay-Dale; Power_W: 63mW; TempCo: 100 ppm/C; Value: 100k; EIA_Code: E96; SizeX_mm: 1; SizeY_mm: 0.5; SizeZ_mm: 0.6; Value2: 0.063W; AEC Qualified: Y; VDC_V: 50V; AEC Category: Q200; AEC Grade: 0
TP4 = CMP-0078143-3: TEST POINT.  No entry in BOM.
U24 = CMP-0067410-1: as U16 on sheet PROC207A_Analog_Mux_SOP_Ctrl
U28 = CMP-0092155-1: 3.3-V, 2:1 (SPDT), 6-channel analog multiplexer with 1.8-V compatible control inputs 24-TSSOP -40 to 85; Manufacturer: Texas Instruments; Max Supply Voltage: 3.6V; -3Db Bandwith: 240MHz; Standoff Height: 0.05mm; Category 9E37533Dafe045F0: Logic, Standard; SizeZ_mm: 1.2mm; On State Resistance: 4.4Ω; Category Aef863F29A99753F: Switches; AEC Qualified: No; Category 9E07530Daf1645C0: Semiconductors and Actives; Min Supply Voltage: 1.65V; Nominal Supply Current: 0.01-0.04uA; PositionCount: 6
U30 = CMP-0067415-1: as U4 on sheet PROC207A_Analog_Mux_SOP_Ctrl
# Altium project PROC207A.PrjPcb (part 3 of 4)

## Sheet PROC207A_XDS110_Interface.SchDoc: XDS110_INTERFACE
size 431 x 279 mm; Date: Not shown in title block; ApprovedBy: Not shown in title block; CheckedBy: Not shown in title block; Author: Not shown in title block; CompanyName: Not shown in title block; DrawnBy: Mistral; Engineer: Not shown in title block; Organization: Not shown in title block; Address1: Not shown in title block; Address2: Not shown in title block; Address3: Not shown in title block; Address4: Not shown in title block; DocumentNumber: 12; Revision: Use project parameter SCH_Rev; SheetNumber: 12; SheetTotal: 18; PageSetup: Record=PageOptions¦CenterHorizontal=True¦CenterVertical=True¦PrintScale=1.00¦XCorrection=1.00¦YCorrection=1.00¦PrintKind=0¦BorderSize=5000000¦LeftOffset=0¦BottomOffset=0¦Orientation=2¦PaperLength=1000¦PaperWidth=1000¦Scale=100¦PaperSource=15¦PrintQuality=600¦MediaType=1¦DitherType=10¦PaperKind=Letter¦PrintScaleMode=1

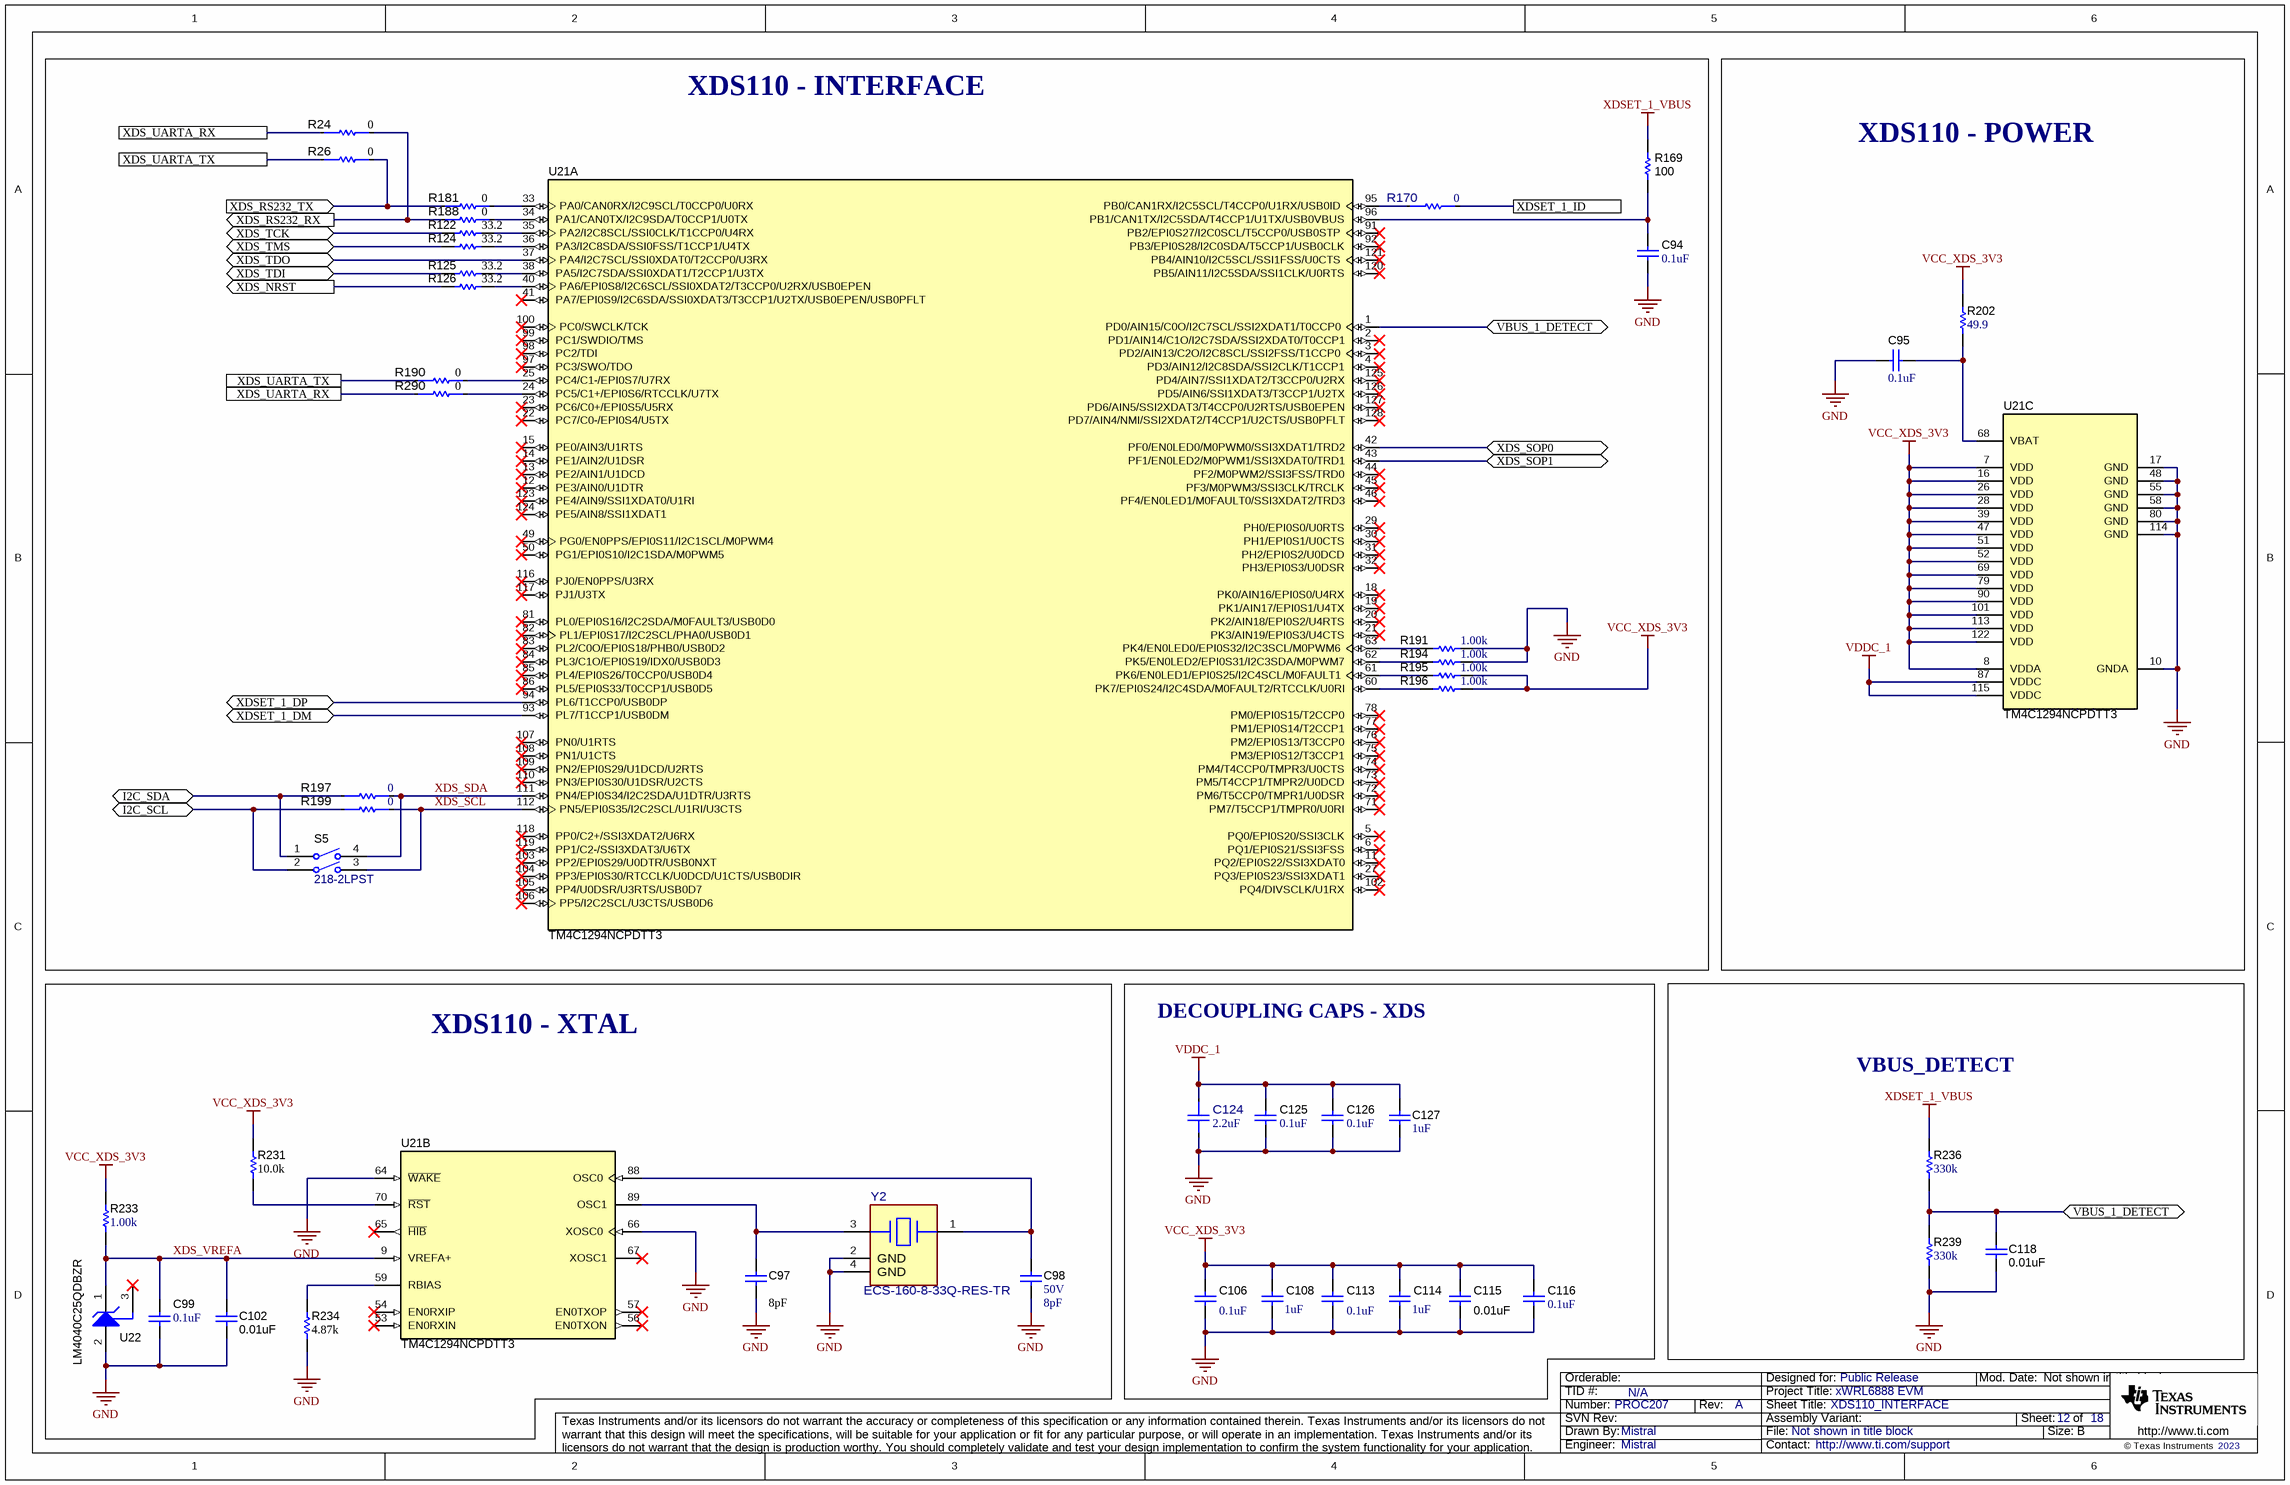
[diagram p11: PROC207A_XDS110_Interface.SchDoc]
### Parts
C94  ValueDisplayed: 0.1uF  [0402]  (hidden comment: GCM155R71H104KE02D)
C95  ValueDisplayed: 0.1uF  [0402]  (hidden comment: GCM155R71H104KE02D)
C97  ValueDisplayed: 8pF  [0402L]  (hidden comment: CC0402DRNPO9BN8R0)
C98  VDC_V: 50V  ValueDisplayed: 8pF  [0402L]  (hidden comment: CC0402DRNPO9BN8R0)
C99  ValueDisplayed: 0.1uF  [0402]  (hidden comment: GCM155R71H104KE02D)
C102  ValueDisplayed: 0.01uF  [0402L]  (hidden comment: GCM155R71E103KA37D)
C106  ValueDisplayed: 0.1uF  [0402]  (hidden comment: GCM155R71H104KE02D)
C108  ValueDisplayed: 1uF  [0402_070]  (hidden comment: GCM155C71A105KE38D)
C113  ValueDisplayed: 0.1uF  [0402]  (hidden comment: GCM155R71H104KE02D)
C114  ValueDisplayed: 1uF  [0402_070]  (hidden comment: GCM155C71A105KE38D)
C115  ValueDisplayed: 0.01uF  [0402L]  (hidden comment: GCM155R71E103KA37D)
C116  ValueDisplayed: 0.1uF  [0402]  (hidden comment: GCM155R71H104KE02D)
C118  ValueDisplayed: 0.01uF  [0402L]  (hidden comment: GCM155R71E103KA37D)
C124  ValueDisplayed: 2.2uF  [FP-GRT155C71A225KE13D_0402-MFG]  (hidden comment: GRT155C71A225KE13D)
C125  ValueDisplayed: 0.1uF  [0402]  (hidden comment: GCM155R71H104KE02D)
C126  ValueDisplayed: 0.1uF  [0402]  (hidden comment: GCM155R71H104KE02D)
C127  ValueDisplayed: 1uF  [0402_070]  (hidden comment: GCM155C71A105KE38D)
R24  value 0  [FP-ERJ-2GE0R00X_0402-MFG]  (hidden comment: ERJ-2GE0R00X)
R26  value 0  [FP-ERJ-2GE0R00X_0402-MFG]  (hidden comment: ERJ-2GE0R00X)
R122  ValueDisplayed: 33.2  [0402]  (hidden comment: CRCW040233R2FKED)
R124  ValueDisplayed: 33.2  [0402]  (hidden comment: CRCW040233R2FKED)
R125  ValueDisplayed: 33.2  [0402]  (hidden comment: CRCW040233R2FKED)
R126  ValueDisplayed: 33.2  [0402]  (hidden comment: CRCW040233R2FKED)
R169  ValueDisplayed: 100  [0402L]  (hidden comment: ERJ-2GEJ101X)
R170  value 0  [FP-ERJ-2GE0R00X_0402-MFG]  (hidden comment: ERJ-2GE0R00X)
R181  value 0  [FP-ERJ-2GE0R00X_0402-MFG]  (hidden comment: ERJ-2GE0R00X)
R188  value 0  [FP-ERJ-2GE0R00X_0402-MFG]  (hidden comment: ERJ-2GE0R00X)
R190  value 0  [FP-ERJ-2GE0R00X_0402-MFG]  (hidden comment: ERJ-2GE0R00X)
R191  ValueDisplayed: 1.00k  [0402]  (hidden comment: ERJ-2RKF1001X)
R194  ValueDisplayed: 1.00k  [0402]  (hidden comment: ERJ-2RKF1001X)
R195  ValueDisplayed: 1.00k  [0402]  (hidden comment: ERJ-2RKF1001X)
R196  ValueDisplayed: 1.00k  [0402]  (hidden comment: ERJ-2RKF1001X)
R197  value 0  [FP-ERJ-2GE0R00X_0402-MFG]  (hidden comment: ERJ-2GE0R00X)
R199  value 0  [FP-ERJ-2GE0R00X_0402-MFG]  (hidden comment: ERJ-2GE0R00X)
R202  ValueDisplayed: 49.9  [0402L]  (hidden comment: CRCW040249R9FKED)
R231  ValueDisplayed: 10.0k  [0402L]  (hidden comment: CRCW040210K0FKED)
R233  ValueDisplayed: 1.00k  [0402]  (hidden comment: ERJ-2RKF1001X)
R234  ValueDisplayed: 4.87k  [0402L]  (hidden comment: CRCW04024K87FKED)
R236  ValueDisplayed: 330k  [0402L]  (hidden comment: CRCW0402330KFKED)
R239  ValueDisplayed: 330k  [0402L]  (hidden comment: CRCW0402330KFKED)
R290  value 0  [FP-ERJ-2GE0R00X_0402-MFG]  (hidden comment: ERJ-2GE0R00X)
S5  218-2LPST  [SW_218-2LP]
U21  TM4C1294NCPDTT3  [PDT0128A]  (parts A,B,C of 3)
U22  LM4040C25QDBZR  [DBZ0003A_N]
Y2  ECS-160-8-33Q-RES-TR  [FP-ECS-160-8-33Q-RES-TR_SMT4_3MM2_2MM5-MFG]

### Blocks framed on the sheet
XDS110 - INTERFACE: C94 R24 R26 R122 R124-R126 R169 R170 R181 R188 R190 R191 R194-R197 R199 R290 S5 U21
XDS110 - POWER: C95 R202 U21
XDS110 - XTAL: C97-C99 C102 R231 R233 R234 U21 U22 Y2
DECOUPLING CAPS - XDS: C106 C108 C113-C116 C124-C127
VBUS_DETECT: C118 R236 R239

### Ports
I2C_SCL (bidir), I2C_SDA (bidir), VBUS_1_DETECT (bidir), XDS_NRST (out), XDS_RS232_RX (out), XDS_RS232_TX (in), XDS_SOP0 (bidir), XDS_SOP1 (bidir), XDS_TCK (bidir), XDS_TDI (bidir), XDS_TDO (bidir), XDS_TMS (bidir), XDS_UARTA_RX, XDS_UARTA_TX, XDSET_1_DM (bidir), XDSET_1_DP (bidir), XDSET_1_ID

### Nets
GND: C94.2 C95.1 C97.1 C98.1 C99.1 C102.1 C106.1 C108.2 C113.1 C114.2 C115.2 C116.1 C118.1 C124.2 C125.1 C126.1 C127.2 R191.2 R194.2 R234.1 R239.1 U21.10(GNDA) U21.17(GND) U21.48(GND) U21.55(GND) U21.58(GND) U21.64(~{WAKE}) U21.66(XOSC0) U21.80(GND) U21.114(GND) U22.2(ANODE) Y2.2(GND) Y2.4(GND)
VCC_XDS_3V3: C106.2 C108.1 C113.2 C114.1 C115.1 C116.2 R195.2 R196.2 R202.1 R231.2 R233.2 U21.7(VDD) U21.8(VDDA) U21.16(VDD) U21.26(VDD) U21.28(VDD) U21.39(VDD) U21.47(VDD) U21.51(VDD) U21.52(VDD) U21.69(VDD) U21.79(VDD) U21.90(VDD) U21.101(VDD) U21.113(VDD) U21.122(VDD)
VDDC_1: C124.1 C125.2 C126.2 C127.1 U21.87(VDDC) U21.115(VDDC)
XDSET_1_VBUS: R169.2 R236.2
I2C_SCL: R199.1 S5.2 ; port I2C_SCL
I2C_SDA: R197.1 S5.1 ; port I2C_SDA
VBUS_1_DETECT: C118.2 R236.1 R239.2 U21.1(PD0/AIN15/C0O/I2C7SCL/SSI2XDAT1/T0CCP0) ; port VBUS_1_DETECT
XDS_NRST: R126.2 ; port XDS_NRST
XDS_RS232_RX: R24.2 R188.1 ; port XDS_RS232_RX
XDS_RS232_TX: R26.2 R181.1 ; port XDS_RS232_TX
XDS_SCL: R199.2 S5.3 U21.112(PN5/EPI0S35/I2C2SCL/U1RI/U3CTS)
XDS_SDA: R197.2 S5.4 U21.111(PN4/EPI0S34/I2C2SDA/U1DTR/U3RTS)
XDS_SOP0: U21.42(PF0/EN0LED0/M0PWM0/SSI3XDAT1/TRD2) ; port XDS_SOP0
XDS_SOP1: U21.43(PF1/EN0LED2/M0PWM1/SSI3XDAT0/TRD1) ; port XDS_SOP1
XDS_TCK: R122.2 ; port XDS_TCK
XDS_TDI: R125.2 ; port XDS_TDI
XDS_TDO: U21.37(PA4/I2C7SCL/SSI0XDAT0/T2CCP0/U3RX) ; port XDS_TDO
XDS_TMS: R124.2 ; port XDS_TMS
XDS_UARTA_RX: R24.1 R290.1 ; port XDS_UARTA_RX
XDS_UARTA_TX: R26.1 R190.1 ; port XDS_UARTA_TX
XDS_VREFA: C99.2 C102.2 R233.1 U21.9(VREFA+) U22.1(CATHODE)
XDSET_1_DM: U21.93(PL7/T1CCP1/USB0DM) ; port XDSET_1_DM
XDSET_1_DP: U21.94(PL6/T1CCP0/USB0DP) ; port XDSET_1_DP
XDSET_1_ID: R170.2 ; port XDSET_1_ID
NetC94_1: C94.1 R169.1 U21.96(PB1/CAN1TX/I2C5SDA/T4CCP1/U1TX/USB0VBUS)
NetC95_2: C95.2 R202.2 U21.68(VBAT)
NetC97_2: C97.2 U21.89(OSC1) Y2.3(OUT/IN)
NetC98_2: C98.2 U21.88(OSC0) Y2.1(IN/OUT)
NetR122_1: R122.1 U21.35(PA2/I2C8SCL/SSI0CLK/T1CCP0/U4RX)
NetR124_1: R124.1 U21.36(PA3/I2C8SDA/SSI0FSS/T1CCP1/U4TX)
NetR125_1: R125.1 U21.38(PA5/I2C7SDA/SSI0XDAT1/T2CCP1/U3TX)
NetR126_1: R126.1 U21.40(PA6/EPI0S8/I2C6SCL/SSI0XDAT2/T3CCP0/U2RX/USB0EPEN)
NetR170_1: R170.1 U21.95(PB0/CAN1RX/I2C5SCL/T4CCP0/U1RX/USB0ID)
NetR181_2: R181.2 U21.33(PA0/CAN0RX/I2C9SCL/T0CCP0/U0RX)
NetR188_2: R188.2 U21.34(PA1/CAN0TX/I2C9SDA/T0CCP1/U0TX)
NetR190_2: R190.2 U21.25(PC4/C1-/EPI0S7/U7RX)
NetR191_1: R191.1 U21.63(PK4/EN0LED0/EPI0S32/I2C3SCL/M0PWM6)
NetR194_1: R194.1 U21.62(PK5/EN0LED2/EPI0S31/I2C3SDA/M0PWM7)
NetR195_1: R195.1 U21.61(PK6/EN0LED1/EPI0S25/I2C4SCL/M0FAULT1)
NetR196_1: R196.1 U21.60(PK7/EPI0S24/I2C4SDA/M0FAULT2/RTCCLK/U0RI)
NetR231_1: R231.1 U21.70(~{RST})
NetR234_2: R234.2 U21.59(RBIAS)
NetR290_2: R290.2 U21.24(PC5/C1+/EPI0S6/RTCCLK/U7TX)

Not connected (* = marked no-connect by the designer): U21 2(PD1/AIN14/C1O/I2C7SDA/SSI2XDAT0/T0CCP1)* 3(PD2/AIN13/C2O/I2C8SCL/SSI2FSS/T1CCP0)* 4(PD3/AIN12/I2C8SDA/SSI2CLK/T1CCP1)* 5(PQ0/EPI0S20/SSI3CLK)* 6(PQ1/EPI0S21/SSI3FSS)* 11(PQ2/EPI0S22/SSI3XDAT0)* 12(PE3/AIN0/U1DTR)* 13(PE2/AIN1/U1DCD)* 14(PE1/AIN2/U1DSR)* 15(PE0/AIN3/U1RTS)* 18(PK0/AIN16/EPI0S0/U4RX)* 19(PK1/AIN17/EPI0S1/U4TX)* 20(PK2/AIN18/EPI0S2/U4RTS)* 21(PK3/AIN19/EPI0S3/U4CTS)* 22(PC7/C0-/EPI0S4/U5TX)* 23(PC6/C0+/EPI0S5/U5RX)* 27(PQ3/EPI0S23/SSI3XDAT1)* 29(PH0/EPI0S0/U0RTS)* 30(PH1/EPI0S1/U0CTS)* 31(PH2/EPI0S2/U0DCD)* 32(PH3/EPI0S3/U0DSR)* 41(PA7/EPI0S9/I2C6SDA/SSI0XDAT3/T3CCP1/U2TX/USB0EPEN/USB0PFLT)* 44(PF2/M0PWM2/SSI3FSS/TRD0)* 45(PF3/M0PWM3/SSI3CLK/TRCLK)* 46(PF4/EN0LED1/M0FAULT0/SSI3XDAT2/TRD3)* 49(PG0/EN0PPS/EPI0S11/I2C1SCL/M0PWM4)* 50(PG1/EPI0S10/I2C1SDA/M0PWM5)* 53(EN0RXIN)* 54(EN0RXIP)* 56(EN0TXON)* 57(EN0TXOP)* 65(~{HIB})* 67(XOSC1)* 71(PM7/T5CCP1/TMPR0/U0RI)* 72(PM6/T5CCP0/TMPR1/U0DSR)* 73(PM5/T4CCP1/TMPR2/U0DCD)* 74(PM4/T4CCP0/TMPR3/U0CTS)* 75(PM3/EPI0S12/T3CCP1)* 76(PM2/EPI0S13/T3CCP0)* 77(PM1/EPI0S14/T2CCP1)* 78(PM0/EPI0S15/T2CCP0)* 81(PL0/EPI0S16/I2C2SDA/M0FAULT3/USB0D0)* 82(PL1/EPI0S17/I2C2SCL/PHA0/USB0D1)* 83(PL2/C0O/EPI0S18/PHB0/USB0D2)* 84(PL3/C1O/EPI0S19/IDX0/USB0D3)* 85(PL4/EPI0S26/T0CCP0/USB0D4)* 86(PL5/EPI0S33/T0CCP1/USB0D5)* 91(PB2/EPI0S27/I2C0SCL/T5CCP0/USB0STP)* 92(PB3/EPI0S28/I2C0SDA/T5CCP1/USB0CLK)* 97(PC3/SWO/TDO)* 98(PC2/TDI)* 99(PC1/SWDIO/TMS)* 100(PC0/SWCLK/TCK)* 102(PQ4/DIVSCLK/U1RX)* 103(PP2/EPI0S29/U0DTR/USB0NXT)* 104(PP3/EPI0S30/RTCCLK/U0DCD/U1CTS/USB0DIR)* 105(PP4/U0DSR/U3RTS/USB0D7)* 106(PP5/I2C2SCL/U3CTS/USB0D6)* 107(PN0/U1RTS)* 108(PN1/U1CTS)* 109(PN2/EPI0S29/U1DCD/U2RTS)* 110(PN3/EPI0S30/U1DSR/U2CTS)* 116(PJ0/EN0PPS/U3RX)* 117(PJ1/U3TX)* 118(PP0/C2+/SSI3XDAT2/U6RX)* 119(PP1/C2-/SSI3XDAT3/U6TX)* 120(PB5/AIN11/I2C5SDA/SSI1CLK/U0RTS)* 121(PB4/AIN10/I2C5SCL/SSI1FSS/U0CTS)* 123(PE4/AIN9/SSI1XDAT0/U1RI)* 124(PE5/AIN8/SSI1XDAT1)* 125(PD4/AIN7/SSI1XDAT2/T3CCP0/U2RX)* 126(PD5/AIN6/SSI1XDAT3/T3CCP1/U2TX)* 127(PD6/AIN5/SSI2XDAT3/T4CCP0/U2RTS/USB0EPEN)* 128(PD7/AIN4/NMI/SSI2XDAT2/T4CCP1/U2CTS/USB0PFLT)*; U22 3(NC)*

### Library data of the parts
C94 C95 C99 C106 C113 C116 C125 C126 = CMP-0006356-2: CAP, CERM, 0.1 uF, 50 V, +/- 10%, X7R, AEC-Q200 Grade 1, 0402; Manufacturer: MuRata; TaMin_C: -55°C; Polarized: N; SizeAreaWB_mm2: 3; U/M: EA; Value: 0.1uF; TaMax_C: 125°C; SizeZ_mm: 0.6; SizeX_mm: 1; SizeY_mm: 0.5; Value2: 50V; AEC Qualified: Y; Cap_F: 100nF; AEC Category: Q200; Value1: Unknown
C97 = CMP-0860185-1: CAP, CERM, 8 pF, 50 V,+/- 6.25%, C0G/NP0, 0402; Manufacturer: Yageo; Cap_Case: 0402; Polarized: N; TaMax_C: 125°C; Value2: 50V; SizeY_mm: 0.5; SizeX_mm: 1; Value: 8pF; AEC Category: Q200; U/M: EA; SizeAreaWB_mm2: 3; TaMin_C: -55°C; SizeZ_mm: 0.6
C98 = CMP-0860185-1: CAP, CERM, 8 pF, 50 V,+/- 6.25%, C0G/NP0, 0402; Manufacturer: Yageo; Cap_Case: 0402; Polarized: N; TaMax_C: 125°C; SizeY_mm: 0.5; SizeX_mm: 1; Value: 8pF; AEC Category: Q200; U/M: EA; SizeAreaWB_mm2: 3; TaMin_C: -55°C; SizeZ_mm: 0.6
C102 C115 C118 = CMP-0006352-2: CAP, CERM, 0.01 uF, 25 V, +/- 10%, X7R, 0402; Manufacturer: MuRata; TaMin_C: -55°C; Polarized: N; SizeAreaWB_mm2: 3; Value1: Unknown; U/M: EA; Value: 0.01uF; TaMax_C: 125°C; SizeZ_mm: 0.6; SizeX_mm: 1; SizeY_mm: 0.5; Cap_Case: 0402; Value2: 25V; CompType: Capacitor; Cap_F: 10nF; AEC Category: Q200
C108 C114 C127 = CMP-0006349-2: CAP, CERM, 1 uF, 10 V, +/- 10%, X7S, AEC-Q200 Grade 1, 0402; Manufacturer: MuRata; Polarized: N; Value: 1uF; U/M: EA; Cap_F: 1µF; Value1: Unknown; VDC_V: 10V; TaMin_C: -55°C; TaMax_C: 125°C; Cap_Case: 0402; SizeArea_mm2: 0.5; SizeAreaWB_mm2: 3; SizeX_mm: 1; SizeZ_mm: 0.7; AEC Category: Q200; AEC Qualified: Y
C124 = CMP-0094968-1: Multi-Layer Ceramic Capacitor 2.2uF 10V X7S ±10% 0402 Paper T/R; Manufacturer: Murata; TempCo: 22%; Value: 2.2µF; SizeZ_mm: 0.7mm; AEC Qualified: Yes; AEC Grade: Grade 1
R24 R26 R170 R181 R188 R190 R197 R199 R290 = CMP-0002710-1: 0 Ohms Jumper Chip Resistor 0402 (1005 Metric) Automotive AEC-Q200 Thick Film; Manufacturer: Panasonic; SizeZ_mm: 0.4mm; AEC Qualified: Yes; AEC Grade: Grade 0; Power: 100mW
R122 R124-R126 = CMP-0026299-2: RES, 33.2, 1%, 0.063 W, AEC-Q200 Grade 0, 0402; Manufacturer: Vishay-Dale; Power_W: 63mW; TempCo: 100 ppm/C; Value_Code: 33R2; Value: 33.2; EIA_Code: E96; SizeX_mm: 1; SizeY_mm: 0.5; SizeZ_mm: 0.6; Value2: 0.063W; AEC Qualified: Y; AEC Grade: 0; AEC Category: Q200; VDC_V: 50V
R169 = CMP-0026993-2: RES, 100, 5%, 0.1 W, AEC-Q200 Grade 0, 0402; Manufacturer: Panasonic; Power_W: 100mW; TempCo: 200 ppm/C; Value_Code: 100R; U/M: EA; Value: 100; EIA_Code: E24; SizeX_mm: 1; SizeY_mm: 0.5; SizeZ_mm: 0.6; Value2: 0.1W; AEC Qualified: Y; AEC Grade: 0; AEC Category: Q200
R191 R194-R196 R233 = CMP-0026657-1: RES, 1.00 k, 1%, 0.1 W, 0402; Manufacturer: Panasonic; Power_W: 100mW; TempCo: 100 ppm/C; Value_Code: 1k00; Value: 1.00k; EIA_Code: E96; Res_ohm: 1k; SizeX_mm: 1; SizeY_mm: 0.5; SizeZ_mm: 0.6; Value2: 0.1W; VDC_V: 50V; AEC Category: Q200; U/M: EA
R202 = CMP-0026404-2: RES, 49.9, 1%, 0.063 W, AEC-Q200 Grade 0, 0402; Manufacturer: Vishay-Dale; Power_W: 63mW; TempCo: 100 ppm/C; Value_Code: 49R9; Value: 49.9; EIA_Code: E96; SizeX_mm: 1; SizeY_mm: 0.5; SizeZ_mm: 0.6; Value2: 0.063W; AEC Qualified: Y; VDC_V: 50V; AEC Category: Q200; AEC Grade: 0
R231 = CMP-0025958-3: RES, 10.0 k, 1%, 0.063 W, AEC-Q200 Grade 0, 0402; Manufacturer: Vishay-Dale; Power_W: 63mW; TempCo: 100 ppm/C; Value_Code: 10k0; Value: 10.0k; EIA_Code: E96; Res_ohm: 10k; SizeX_mm: 1; SizeY_mm: 0.5; SizeZ_mm: 0.6; Value2: 0.063W; AEC Qualified: Y; VDC_V: 50V; AEC Category: Q200; AEC Grade: 0
R234 = CMP-0026413-2: RES, 4.87 k, 1%, 0.063 W, AEC-Q200 Grade 0, 0402; Manufacturer: Vishay-Dale; Power_W: 63mW; TempCo: 100 ppm/C; Value_Code: 4k87; Value: 4.87k; EIA_Code: E96; SizeX_mm: 1; SizeY_mm: 0.5; SizeZ_mm: 0.6; Value2: 0.063W; AEC Qualified: Y; VDC_V: 50V; AEC Category: Q200; AEC Grade: 0
R236 R239 = CMP-0078210-2: RES, 330 k, 1%, 0.063 W, AEC-Q200 Grade 0, 0402; Manufacturer: Vishay-Dale; SizeArea_mm2: 0.5; AEC Qualified: Y; AEC Category: Q200; Value: 330k; SizeZ_mm: 0.6; TempCo: 100 ppm/C; AEC Grade: 0; Power_W: 63mW; VDC_V: 50V; Value2: 0.063W; SizeX_mm: 1
S5 = CMP-0002230-1: Switch, SPST, 2 Pos, 25mA, 24VDC, SMD; Manufacturer: CTS Electrocomponents; CurrentRating_mA: 25A; PositionCount: 2; VDC_V: 24V; SwitchFunction: Off-On
U21 = CMP-0029856-2: Tiva C Series Microcontroller, 1024 KB Flash, 256 KB SRAM, 12 Bit, 20 Channels, -40 to 105 degC, 128-Pin TQFP (PDT), Green (RoHS & no Sb/Br), Tray; Manufacturer: Texas Instruments; ADC Channels: 20; CPU: ARM Cortex-M4; Flash: 1024 KB; ADC Resolution: 12 Bits; Max Speed: 120 MHz; SRAM: 256 KB; SizeAreaWB_mm2: 324.0; SizeArea_mm2: 256.0; SizeX_mm: 16.0; SizeZ_mm: 1.2; CompType: IC
U22 = CMP-0033001-1: Precision Micropower Shunt Voltage Reference, 0.5% accuracy, 2.5 V, 15 ppm / degC, 15 mA, -40 to 125 degC, 3-pin SOT-23 (DBZ), Green (RoHS & no Sb/Br); Manufacturer: Texas Instruments; Initial Accuracy @ 25/deg C(%): 0.5; Temp Coeff(Typ)(ppm/ degree C): 15; Temp Coeff(Max)(ppm/ degree C): 100; Rating: Catalog; Min Iz for Regulation(uA): 75; VO(V): 2.5
Y2 = CMP-0095014-1: 16 MHz ±15ppm Crystal 8pF 80 Ohms 4-SMD, No Lead; Manufacturer: ECS; Frequency Stability: 50ppm; SizeZ_mm: 0.8mm; Frequency_Fixed: 16MHz; AEC Qualified: Yes; Esr: 80; AEC Grade: Grade 1

## Sheet PROC207A_MUX_CAN_FD.SchDoc: ANALOG MUX AND CAN FD_B
size 431 x 279 mm; Date: Not shown in title block; ApprovedBy: Not shown in title block; CheckedBy: Not shown in title block; Author: Not shown in title block; CompanyName: Not shown in title block; DrawnBy: Mistral; Engineer: Not shown in title block; Organization: Not shown in title block; Address1: Not shown in title block; Address2: Not shown in title block; Address3: Not shown in title block; Address4: Not shown in title block; DocumentNumber: 10; Revision: Use project parameter SCH_Rev; SheetNumber: 12; SheetTotal: 17; PageSetup: Record=PageOptions¦CenterHorizontal=True¦CenterVertical=True¦PrintScale=1.00¦XCorrection=1.00¦YCorrection=1.00¦PrintKind=0¦BorderSize=5000000¦LeftOffset=0¦BottomOffset=0¦Orientation=2¦PaperLength=1000¦PaperWidth=1000¦Scale=100¦PaperSource=15¦PrintQuality=600¦MediaType=1¦DitherType=10¦PaperKind=Letter¦PrintScaleMode=1

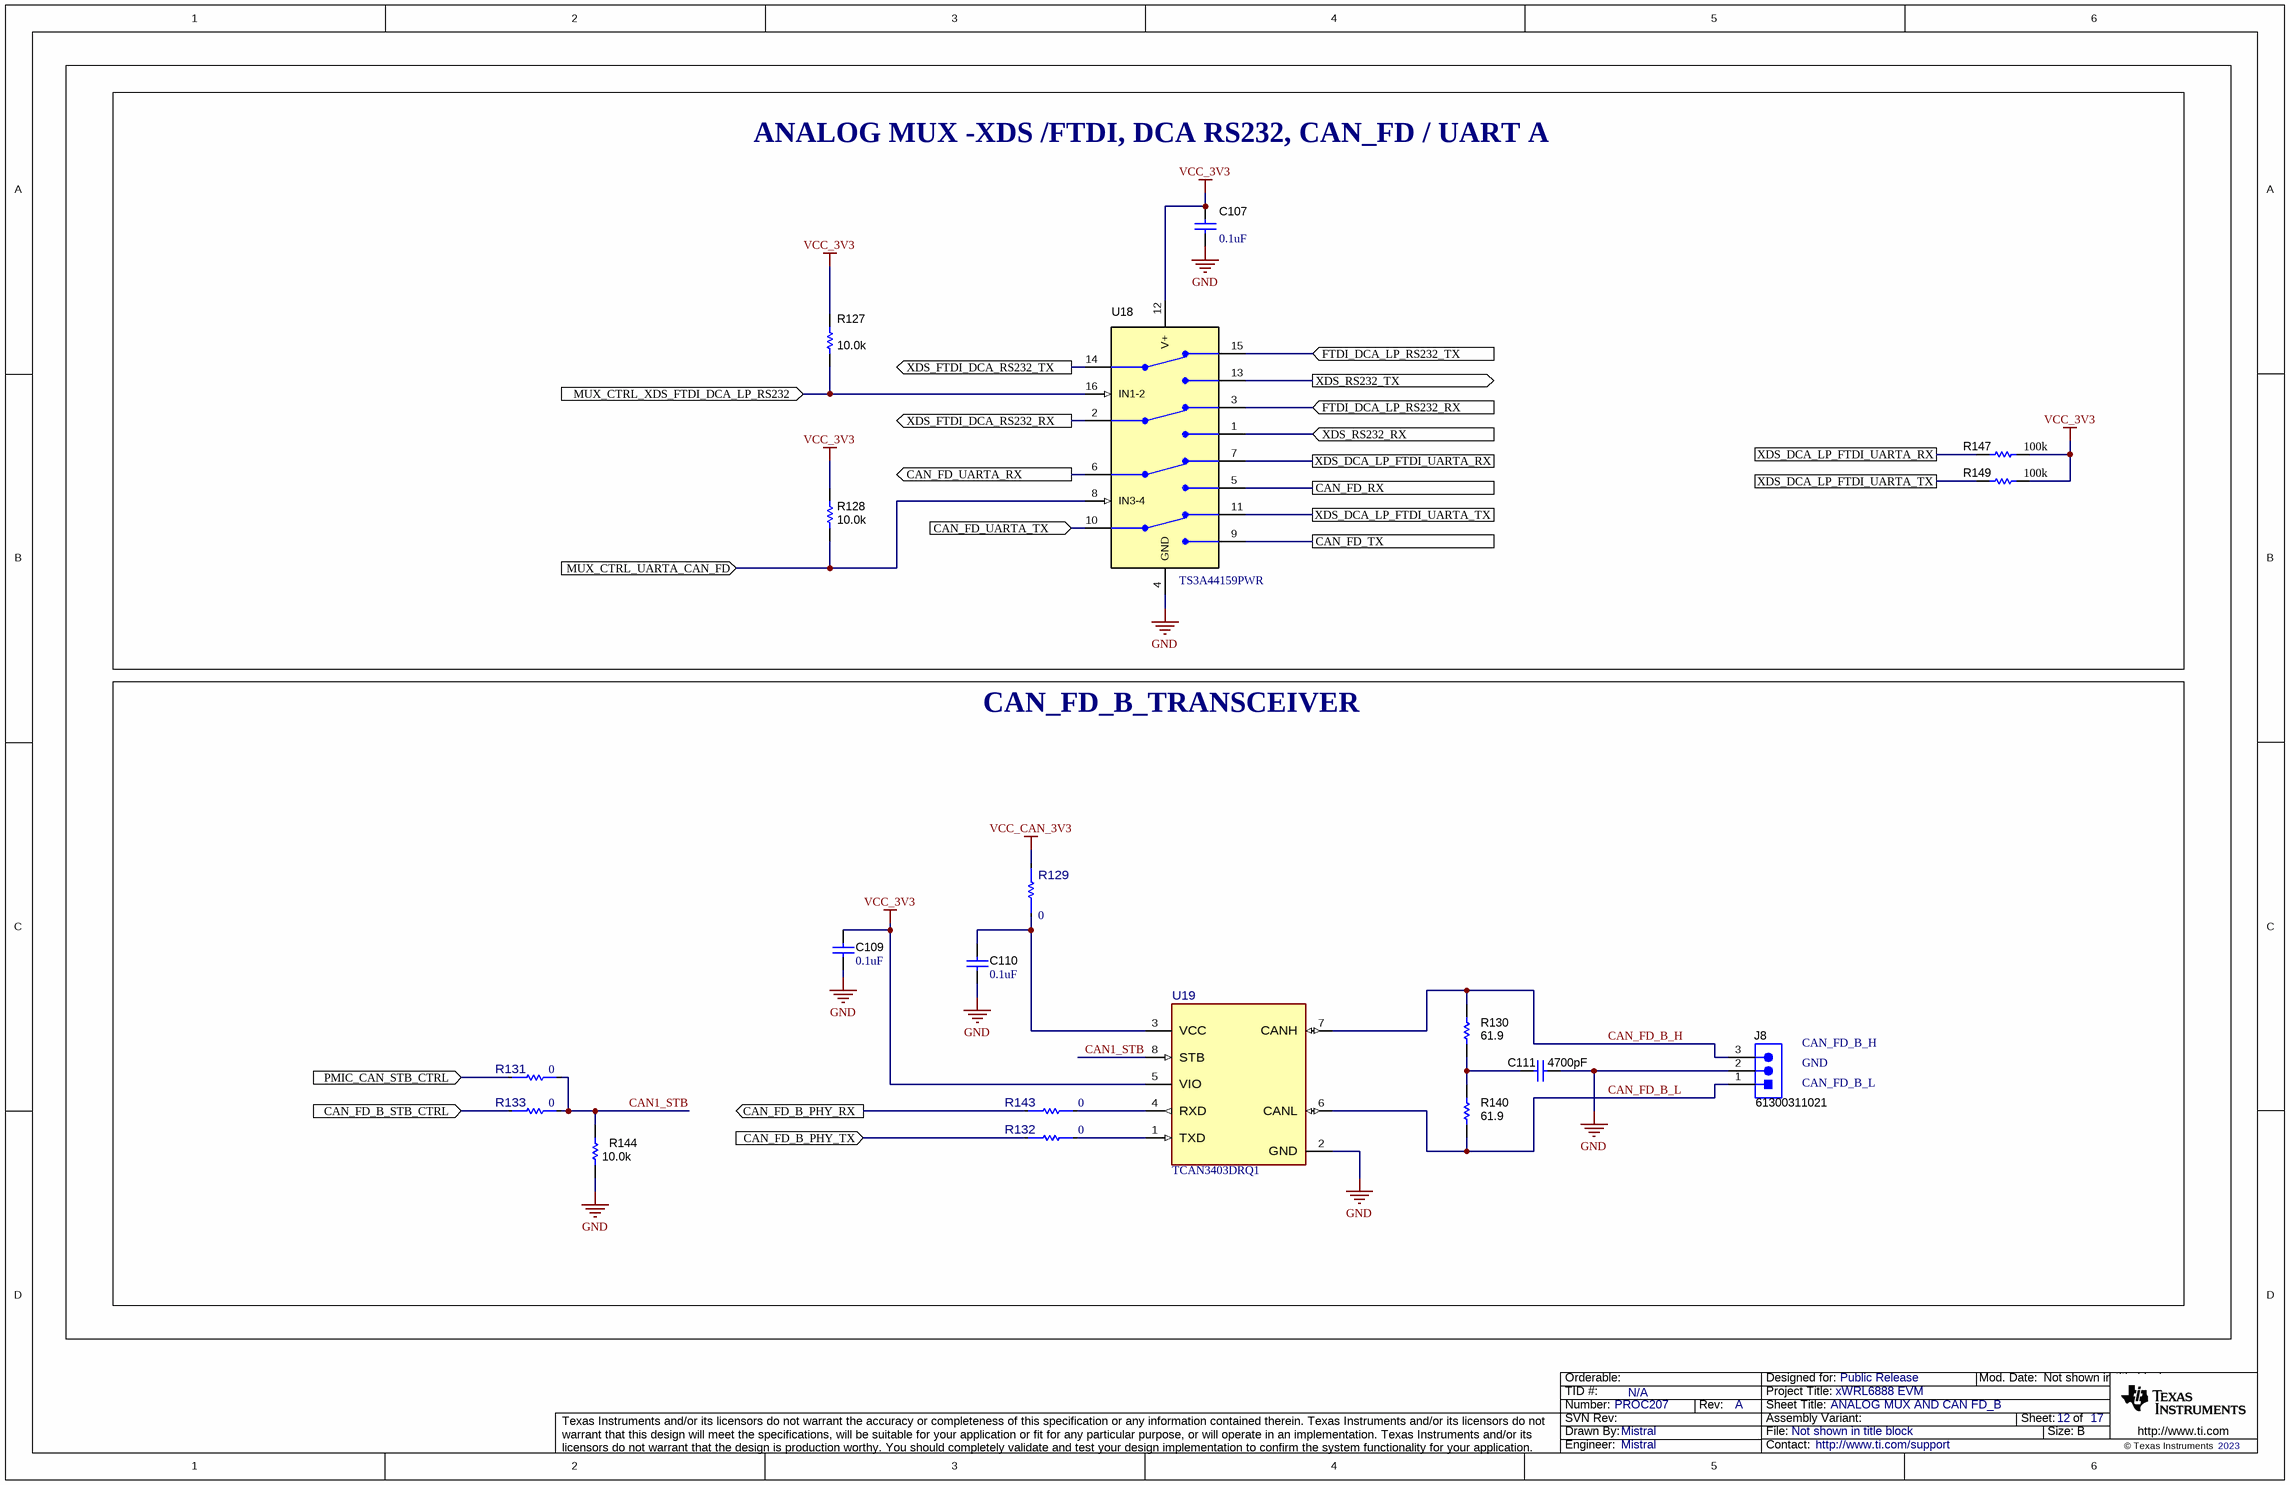
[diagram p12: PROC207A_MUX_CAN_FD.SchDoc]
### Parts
C107  ValueDisplayed: 0.1uF  [0402]  (hidden comment: GCM155R71H104KE02D)
C109  ValueDisplayed: 0.1uF  [0402]  (hidden comment: GCM155R71H104KE02D)
C110  ValueDisplayed: 0.1uF  [0402]  (hidden comment: GCM155R71H104KE02D)
C111  ValueDisplayed: 4700pF  [0402L]  (hidden comment: GCM155R71H472KA37D)
J8  61300311021  [Wurth_61300311021]
R127  ValueDisplayed: 10.0k  [0402L]  (hidden comment: CRCW040210K0FKED)
R128  ValueDisplayed: 10.0k  [0402L]  (hidden comment: CRCW040210K0FKED)
R129  value 0  [FP-ERJ-2GE0R00X_0402-MFG]  (hidden comment: ERJ-2GE0R00X)
R130  ValueDisplayed: 61.9  [0402L]  (hidden comment: CRCW040261R9FKED)
R131  value 0  [FP-ERJ-2GE0R00X_0402-MFG]  (hidden comment: ERJ-2GE0R00X)
R132  value 0  [FP-ERJ-2GE0R00X_0402-MFG]  (hidden comment: ERJ-2GE0R00X)
R133  value 0  [FP-ERJ-2GE0R00X_0402-MFG]  (hidden comment: ERJ-2GE0R00X)
R140  ValueDisplayed: 61.9  [0402L]  (hidden comment: CRCW040261R9FKED)
R143  value 0  [FP-ERJ-2GE0R00X_0402-MFG]  (hidden comment: ERJ-2GE0R00X)
R144  ValueDisplayed: 10.0k  [0402L]  (hidden comment: CRCW040210K0FKED)
R147  ValueDisplayed: 100k  [0402L]  (hidden comment: CRCW0402100KFKED)
R149  ValueDisplayed: 100k  [0402L]  (hidden comment: CRCW0402100KFKED)
U18  TS3A44159PWR  [PW0016A_N]
U19  TCAN3403DRQ1  [D0008B-MFG]

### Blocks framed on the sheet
ANALOG MUX -XDS /FTDI, DCA RS232, CAN_FD / UART A: C107 R127 R128 R147 R149 U18
CAN_FD_B_TRANSCEIVER: C109-C111 J8 R129-R133 R140 R143 R144 U19

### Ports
CAN_FD_B_PHY_RX (out), CAN_FD_B_PHY_TX (in), CAN_FD_B_STB_CTRL (in), CAN_FD_RX, CAN_FD_TX, CAN_FD_UARTA_RX (out), CAN_FD_UARTA_TX (in), FTDI_DCA_LP_RS232_RX (in), FTDI_DCA_LP_RS232_TX (in), MUX_CTRL_UARTA_CAN_FD (in), MUX_CTRL_XDS_FTDI_DCA_LP_RS232 (in), PMIC_CAN_STB_CTRL (in), XDS_DCA_LP_FTDI_UARTA_RX, XDS_DCA_LP_FTDI_UARTA_TX, XDS_FTDI_DCA_RS232_RX (out), XDS_FTDI_DCA_RS232_TX (out), XDS_RS232_RX (in), XDS_RS232_TX (out)

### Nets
GND: C107.2 C109.1 C110.1 C111.1 J8.2 R144.1 U18.4(GND) U19.2(GND)
VCC_3V3: C107.1 C109.2 R127.2 R128.2 R147.1 R149.1 U18.12(V+) U19.5(VIO)
VCC_CAN_3V3: R129.2
CAN1_STB: R131.2 R133.2 R144.2 U19.8(STB)
CAN_FD_B_H: J8.3 R130.2 U19.7(CANH)
CAN_FD_B_L: J8.1 R140.1 U19.6(CANL)
CAN_FD_B_PHY_RX: R143.1 ; port CAN_FD_B_PHY_RX
CAN_FD_B_PHY_TX: R132.1 ; port CAN_FD_B_PHY_TX
CAN_FD_B_STB_CTRL: R133.1 ; port CAN_FD_B_STB_CTRL
CAN_FD_RX: U18.5(NO3) ; port CAN_FD_RX
CAN_FD_TX: U18.9(NO4) ; port CAN_FD_TX
CAN_FD_UARTA_RX: U18.6(COM3) ; port CAN_FD_UARTA_RX
CAN_FD_UARTA_TX: U18.10(COM4) ; port CAN_FD_UARTA_TX
FTDI_DCA_LP_RS232_RX: U18.3(NC2) ; port FTDI_DCA_LP_RS232_RX
FTDI_DCA_LP_RS232_TX: U18.15(NC1) ; port FTDI_DCA_LP_RS232_TX
MUX_CTRL_UARTA_CAN_FD: R128.1 U18.8(IN3-4) ; port MUX_CTRL_UARTA_CAN_FD
MUX_CTRL_XDS_FTDI_DCA_LP_RS232: R127.1 U18.16(IN1-2) ; port MUX_CTRL_XDS_FTDI_DCA_LP_RS232
PMIC_CAN_STB_CTRL: R131.1 ; port PMIC_CAN_STB_CTRL
XDS_DCA_LP_FTDI_UARTA_RX: R147.2 U18.7(NC3) ; port XDS_DCA_LP_FTDI_UARTA_RX
XDS_DCA_LP_FTDI_UARTA_TX: R149.2 U18.11(NC4) ; port XDS_DCA_LP_FTDI_UARTA_TX
XDS_FTDI_DCA_RS232_RX: U18.2(COM2) ; port XDS_FTDI_DCA_RS232_RX
XDS_FTDI_DCA_RS232_TX: U18.14(COM1) ; port XDS_FTDI_DCA_RS232_TX
XDS_RS232_RX: U18.1(NO2) ; port XDS_RS232_RX
XDS_RS232_TX: U18.13(NO1) ; port XDS_RS232_TX
NetC110_2: C110.2 R129.1 U19.3(VCC)
NetC111_2: C111.2 R130.1 R140.2
NetR132_2: R132.2 U19.1(TXD)
NetR143_2: R143.2 U19.4(RXD)

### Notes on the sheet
- (near J8) CAN_FD_B_H
- (near J8) GND
- (near J8) CAN_FD_B_L

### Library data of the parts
C107 C109 C110 = CMP-0006356-2: as C94 on sheet PROC207A_XDS110_Interface
C111 = CMP-0006361-2: CAP, CERM, 4700 pF, 50 V, +/- 10%, X7R, AEC-Q200 Grade 1, 0402; Manufacturer: MuRata; TaMin_C: -55°C; Polarized: N; SizeAreaWB_mm2: 3; Value1: Unknown; U/M: EA; Value: 4700pF; TaMax_C: 125°C; SizeZ_mm: 0.6; SizeX_mm: 1; SizeY_mm: 0.5; Cap_Case: 0402; Value2: 50V; AEC Qualified: Y; Cap_F: 4.7nF; AEC Category: Q200
J8 = CMP-0054795-1: Header, 2.54 mm, 3x1, Gold, R/A, TH; Manufacturer: Wurth Elektronik; CNHeader: TRUE; Shrouded: N; Gender: Male; Row_Count: 1; Pitch_mm: 2.54; CT: FALSE
R127 R128 R144 = CMP-0025958-3: as R231 on sheet PROC207A_XDS110_Interface
R129 R131-R133 R143 = CMP-0002710-1: as R24 on sheet PROC207A_XDS110_Interface
R130 R140 = CMP-0026491-2: RES, 61.9, 1%, 0.063 W, AEC-Q200 Grade 0, 0402; Manufacturer: Vishay-Dale; Power_W: 63mW; TempCo: 100 ppm/C; Value_Code: 61R9; Value: 61.9; EIA_Code: E96; SizeX_mm: 1; SizeY_mm: 0.5; SizeZ_mm: 0.6; Value2: 0.063W; AEC Qualified: Y; VDC_V: 50V; AEC Category: Q200; AEC Grade: 0
R147 R149 = CMP-0025950-3: RES, 100 k, 1%, 0.063 W, AEC-Q200 Grade 0, 0402; Manufacturer: Vishay-Dale; Power_W: 63mW; TempCo: 100 ppm/C; Value: 100k; EIA_Code: E96; SizeX_mm: 1; SizeY_mm: 0.5; SizeZ_mm: 0.6; Value2: 0.063W; AEC Qualified: Y; VDC_V: 50V; AEC Category: Q200; AEC Grade: 0
U18 = CMP-0067412-1: 0.45-Ohm Quad SPDT Analog Switch Quad-Channel 2:1 Multiplexer/Demultiplexer with Two Controls, PW0016A (TSSOP-16); Alternate Manufacturer: Texas Instruments; SizeAreaWB_mm2: 58.8; U/M: EA; SizeZ_mm: 1.2; SizeX_mm: 6.4; SizeY_mm: 5.0; SizeArea_mm2: 32.0; CompType: IC
U19 = CMP-0121020-1: Dual, Simultaneous-Sampling, 16-Bit, 5 MSPS SAR ADCs; Manufacturer: Texas Instruments; SizeZ_mm: 1.75mm; AEC Qualified: Yes; AEC Grade: Grade 1; Interface: CAN; Max Supply Voltage: 3.6V; Min Supply Voltage: 1.7V; Standoff Height: 0.11mm

## Sheet PROC207A_CAN_LIN_PHY_Interface.SchDoc: CAN_LIN_PHY_INTERFACE
size 431 x 279 mm; Date: Not shown in title block; ApprovedBy: Not shown in title block; CheckedBy: Not shown in title block; Author: Not shown in title block; CompanyName: Not shown in title block; DrawnBy: Mistral; Engineer: Not shown in title block; Organization: Not shown in title block; Address1: Not shown in title block; Address2: Not shown in title block; Address3: Not shown in title block; Address4: Not shown in title block; DocumentNumber: 13; Revision: Use project parameter SCH_Rev; SheetNumber: 14; SheetTotal: 18; PageSetup: Record=PageOptions¦CenterHorizontal=True¦CenterVertical=True¦PrintScale=1.00¦XCorrection=1.00¦YCorrection=1.00¦PrintKind=0¦BorderSize=5000000¦LeftOffset=0¦BottomOffset=0¦Orientation=2¦PaperLength=1000¦PaperWidth=1000¦Scale=100¦PaperSource=15¦PrintQuality=600¦MediaType=1¦DitherType=10¦PaperKind=Letter¦PrintScaleMode=1

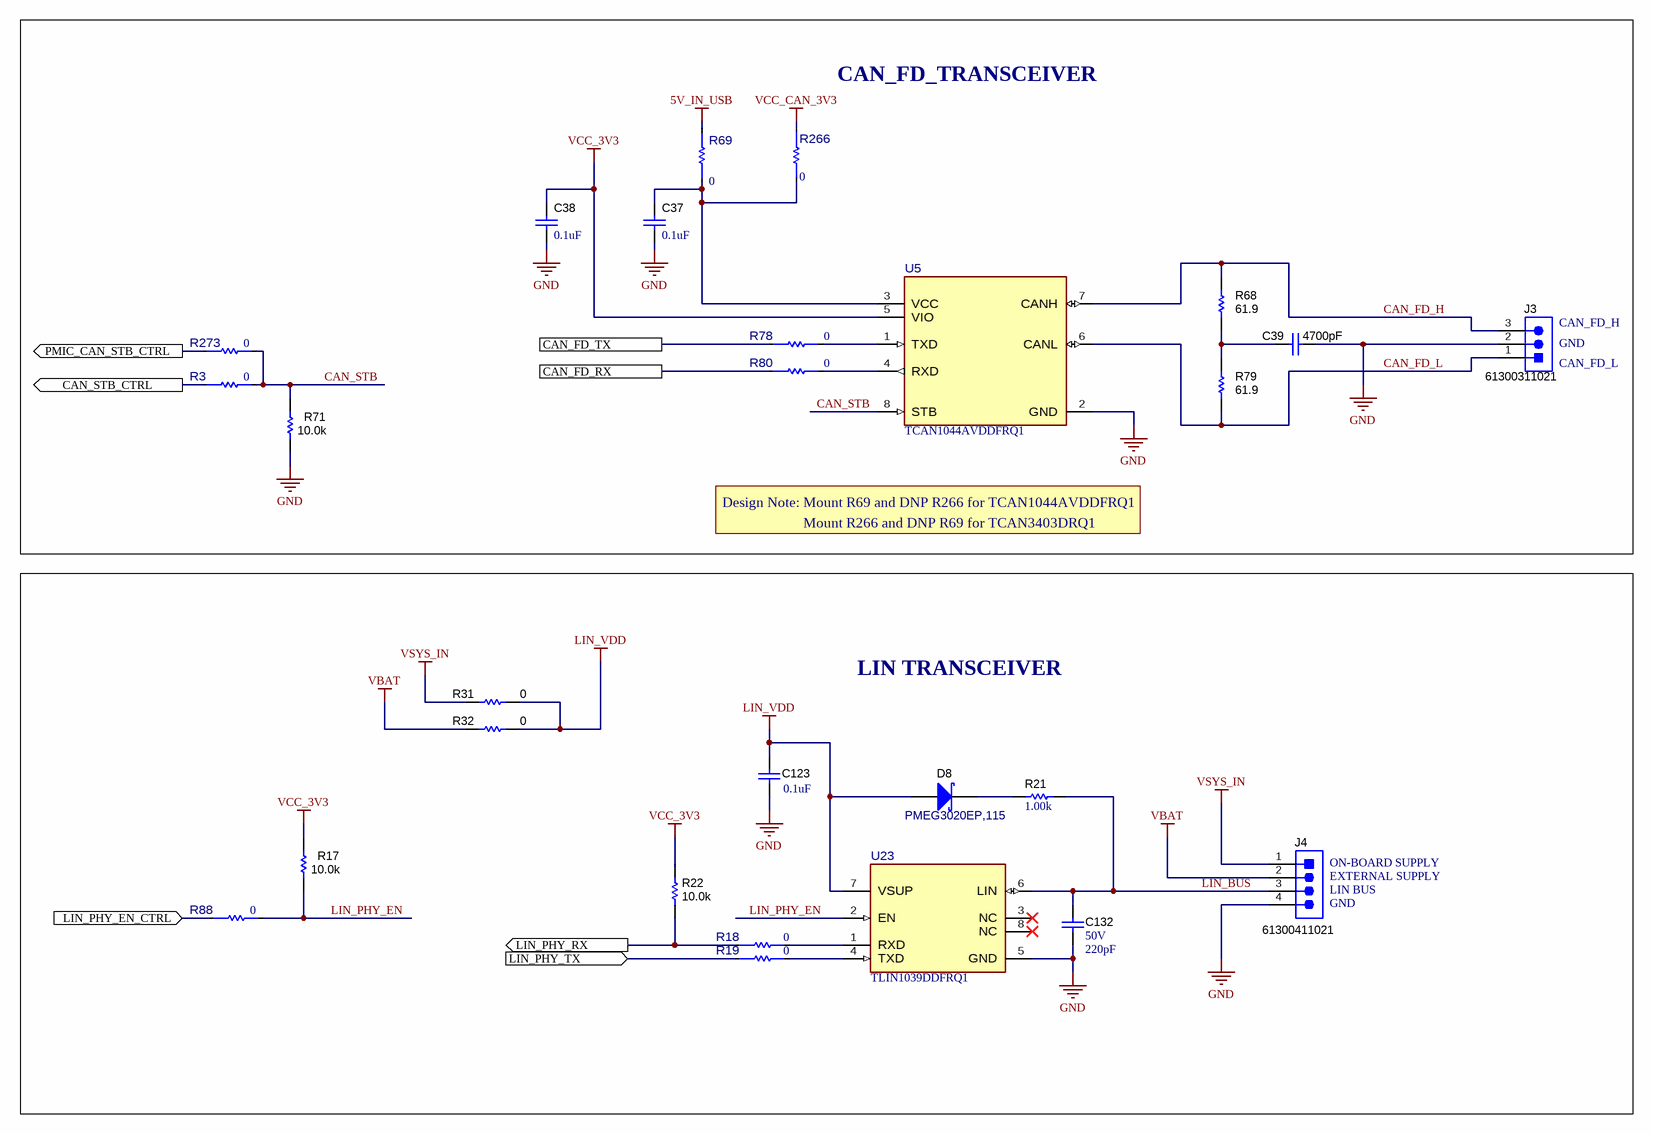
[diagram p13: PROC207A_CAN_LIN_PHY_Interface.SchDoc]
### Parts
C37  ValueDisplayed: 0.1uF  [0402]  (hidden comment: GCM155R71H104KE02D)
C38  ValueDisplayed: 0.1uF  [0402]  (hidden comment: GCM155R71H104KE02D)
C39  ValueDisplayed: 4700pF  [0402L]  (hidden comment: GCM155R71H472KA37D)
C123  ValueDisplayed: 0.1uF  [0402]  (hidden comment: GCM155R71H104KE02D)
C132  VDC_V: 50V  ValueDisplayed: 220pF  [0402]  (hidden comment: 885012005063)
D8  PMEG3020EP,115  [SOD-128]
J3  61300311021  [Wurth_61300311021]
J4  61300411021  [Wurth_61300411021]
R3  value 0  [FP-ERJ-2GE0R00X_0402-MFG]  (hidden comment: ERJ-2GE0R00X)
R17  ValueDisplayed: 10.0k  [0402L]  (hidden comment: CRCW040210K0FKED)
R18  value 0  [FP-ERJ-2GE0R00X_0402-MFG]  (hidden comment: ERJ-2GE0R00X)
R19  value 0  [FP-ERJ-2GE0R00X_0402-MFG]  (hidden comment: ERJ-2GE0R00X)
R21  ValueDisplayed: 1.00k  [0402]  (hidden comment: ERJ-2RKF1001X)
R22  ValueDisplayed: 10.0k  [0402L]  (hidden comment: CRCW040210K0FKED)
R31  ValueDisplayed: 0  [0603]  (hidden comment: MCT06030Z0000ZP500)
R32  ValueDisplayed: 0  [0603]  (hidden comment: MCT06030Z0000ZP500)
R68  ValueDisplayed: 61.9  [0402L]  (hidden comment: CRCW040261R9FKED)
R69  value 0  [FP-ERJ-2GE0R00X_0402-MFG]  (hidden comment: ERJ-2GE0R00X)
R71  ValueDisplayed: 10.0k  [0402L]  (hidden comment: CRCW040210K0FKED)
R78  value 0  [FP-ERJ-2GE0R00X_0402-MFG]  (hidden comment: ERJ-2GE0R00X)
R79  ValueDisplayed: 61.9  [0402L]  (hidden comment: CRCW040261R9FKED)
R80  value 0  [FP-ERJ-2GE0R00X_0402-MFG]  (hidden comment: ERJ-2GE0R00X)
R88  value 0  [FP-ERJ-2GE0R00X_0402-MFG]  (hidden comment: ERJ-2GE0R00X)
R266  value 0  [FP-ERJ-2GE0R00X_0402-MFG]  (hidden comment: ERJ-2GE0R00X)
R273  value 0  [FP-ERJ-2GE0R00X_0402-MFG]  (hidden comment: ERJ-2GE0R00X)
U5  TCAN1044AVDDFRQ1  [DDF0008A-MFG]
U23  TLIN1039DDFRQ1  [DDF0008A-MFG]

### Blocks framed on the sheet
CAN_FD_TRANSCEIVER: C37-C39 J3 R3 R68 R69 R71 R78-R80 R266 R273 U5
LIN TRANSCEIVER: C123 C132 D8 J4 R17-R19 R21 R22 R31 R32 R88 U23

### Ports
CAN_FD_RX, CAN_FD_TX, CAN_STB_CTRL (out), LIN_PHY_EN_CTRL (in), LIN_PHY_RX (out), LIN_PHY_TX (in), PMIC_CAN_STB_CTRL (out)

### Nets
5V_IN_USB: R69.2
GND: C37.1 C38.1 C39.1 C123.2 C132.2 J3.2 J4.4 R71.1 U5.2(GND) U23.5(GND)
LIN_VDD: C123.1 D8.2(A) R31.2 R32.2 U23.7(VSUP)
VBAT: J4.2 R32.1
VCC_3V3: C38.2 R17.2 R22.2 U5.5(VIO)
VCC_CAN_3V3: R266.1
VSYS_IN: J4.1 R31.1
CAN_FD_H: J3.3 R68.2 U5.7(CANH)
CAN_FD_L: J3.1 R79.1 U5.6(CANL)
CAN_FD_RX: R80.1 ; port CAN_FD_RX
CAN_FD_TX: R78.1 ; port CAN_FD_TX
CAN_STB: R3.2 R71.2 R273.2 U5.8(STB)
CAN_STB_CTRL: R3.1 ; port CAN_STB_CTRL
LIN_BUS: C132.1 J4.3 R21.1 U23.6(LIN)
LIN_PHY_EN: R17.1 R88.2 U23.2(EN)
LIN_PHY_EN_CTRL: R88.1 ; port LIN_PHY_EN_CTRL
LIN_PHY_RX: R18.1 R22.1 ; port LIN_PHY_RX
LIN_PHY_TX: R19.1 ; port LIN_PHY_TX
PMIC_CAN_STB_CTRL: R273.1 ; port PMIC_CAN_STB_CTRL
NetC37_2: C37.2 R69.1 R266.2 U5.3(VCC)
NetC39_2: C39.2 R68.1 R79.2
NetD8_1: D8.1(K) R21.2
NetR18_2: R18.2 U23.1(RXD)
NetR19_2: R19.2 U23.4(TXD)
NetR78_2: R78.2 U5.1(TXD)
NetR80_2: R80.2 U5.4(RXD)

Not connected (* = marked no-connect by the designer): U23 3(NC)* 8(NC)*

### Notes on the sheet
- (near J3) CAN_FD_H
- (near J3) GND
- (near J3) CAN_FD_L
- Design Note: Mount R69 and DNP R266 for TCAN1044AVDDFRQ1
- Mount R266 and DNP R69 for TCAN3403DRQ1
- (near J4) ON-BOARD SUPPLY
- (near J4) EXTERNAL SUPPLY
- (near J4) LIN BUS
- (near J4) GND

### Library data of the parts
C37 C38 = CMP-0006356-2: as C94 on sheet PROC207A_XDS110_Interface
C39 = CMP-0006361-2: as C111 on sheet PROC207A_MUX_CAN_FD
C123 = CMP-0006356-2: CAP, CERM, 0.1 uF, 50 V, +/- 10%, X7R, AEC-Q200 Grade 1, 0402; Manufacturer: MuRata; TaMin_C: -55°C; Polarized: N; SizeAreaWB_mm2: 3; Value1: Unknown; U/M: EA; Value: 0.1uF; TaMax_C: 125°C; SizeZ_mm: 0.6; SizeX_mm: 1; SizeY_mm: 0.5; Value2: 50V; AEC Qualified: Y; Cap_F: 100nF; AEC Category: Q200
C132 = CMP-0006218-2: CAP, CERM, 220 pF, 50 V, +/- 5%, C0G/NP0, 0402; Manufacturer: Wurth Elektronik; TaMin_C: -55°C; Polarized: N; SizeAreaWB_mm2: 3; Value1: Unknown; U/M: EA; Value: 220pF; TaMax_C: 125°C; SizeZ_mm: 0.6; SizeX_mm: 1; SizeY_mm: 0.5; AEC Category: Q200
D8 = CMP-0078758-2: Diode, Schottky, 30 V, 2 A, AEC-Q101, SOD-128; Manufacturer: Nexperia; Value2: 0.36V; SizeAreaWB_mm2: 19.6; Io_A: 2A; Value: 30V; AEC Qualified: Y; TJmax_C: 150°C; SizeX_mm: 4.6; AEC Category: Q101; SizeY_mm: 2.5; SizeArea_mm2: 11.5; Vf_V: 3.6dV; SizeZ_mm: 1.1
J3 = CMP-0054795-1: as J8 on sheet PROC207A_MUX_CAN_FD
J4 = CMP-0054797-1: Header, 2.54 mm, 4x1, Gold, R/A, TH; Manufacturer: Wurth Elektronik; CNHeader: TRUE; Shrouded: N; Gender: Male; Row_Count: 1; Pitch_mm: 2.54; CT: FALSE
R3 R18 R19 R69 R78 R80 R88 R266 R273 = CMP-0002710-1: as R24 on sheet PROC207A_XDS110_Interface
R17 R22 R71 = CMP-0025958-3: as R231 on sheet PROC207A_XDS110_Interface
R21 = CMP-0026657-1: as R191 on sheet PROC207A_XDS110_Interface
R31 R32 = CMP-0025884-3: RES, 0, 5%, 0.125 W, 0603; Manufacturer: Vishay/Beyschlag; Power_W: 125mW; TempCo: ppm/C; Value_Code: 0000; U/M: EA; Value: 0; EIA_Code: E24; SizeX_mm: 1.6; SizeY_mm: 0.8; SizeZ_mm: 1; Value2: 0.125W; SizeArea_mm2: 1.28; CompType: Resistor; AEC Qualified: N; AEC Category: Q200; INSTALATION: DNP
R68 R79 = CMP-0026491-2: as R130 on sheet PROC207A_MUX_CAN_FD
U5 = CMP-0122870-1: Enhanced automotive CAN transceiver with standby and 1.8-V I/O support 8-SOT-23-THIN -40 to 150; Manufacturer: Texas Instruments; SizeZ_mm: 1.1mm; AEC Qualified: Yes; AEC Grade: Grade 1; Max Supply Voltage: 5.5V; Min Supply Voltage: 1.7V; Standoff Height: 0mm; TJmax_C: +150°C
U23 = CMP-0090433-1: Local Interconnect Network (LIN) Transceiver with Dominant State Timeout; Manufacturer: Texas Instruments; Max Supply Voltage: 36V; SizeZ_mm: 1.1mm; Min Supply Voltage: 4.5V; Standoff Height: 0mm; Nominal Supply Current: 0.3-1.2mA; AEC Grade: Grade 0; TJmax_C: +150°C; Interface: UART,LIN,SCI; AEC Qualified: Yes

## Sheet PROC207A_FTDI.SchDoc: FTDI_USB to SPI/12C/UART_Converter
size 431 x 279 mm; Date: Not shown in title block; ApprovedBy: Not shown in title block; CheckedBy: Not shown in title block; Author: Not shown in title block; CompanyName: Not shown in title block; DrawnBy: Mistral; Engineer: Not shown in title block; Organization: Not shown in title block; Address1: Not shown in title block; Address2: Not shown in title block; Address3: Not shown in title block; Address4: Not shown in title block; DocumentNumber: 14; Revision: Use project parameter SCH_Rev; SheetNumber: 15; SheetTotal: 18; PageSetup: Record=PageOptions¦CenterHorizontal=True¦CenterVertical=True¦PrintScale=1.00¦XCorrection=1.00¦YCorrection=1.00¦PrintKind=0¦BorderSize=5000000¦LeftOffset=0¦BottomOffset=0¦Orientation=2¦PaperLength=1000¦PaperWidth=1000¦Scale=100¦PaperSource=15¦PrintQuality=600¦MediaType=1¦DitherType=10¦PaperKind=Letter¦PrintScaleMode=1

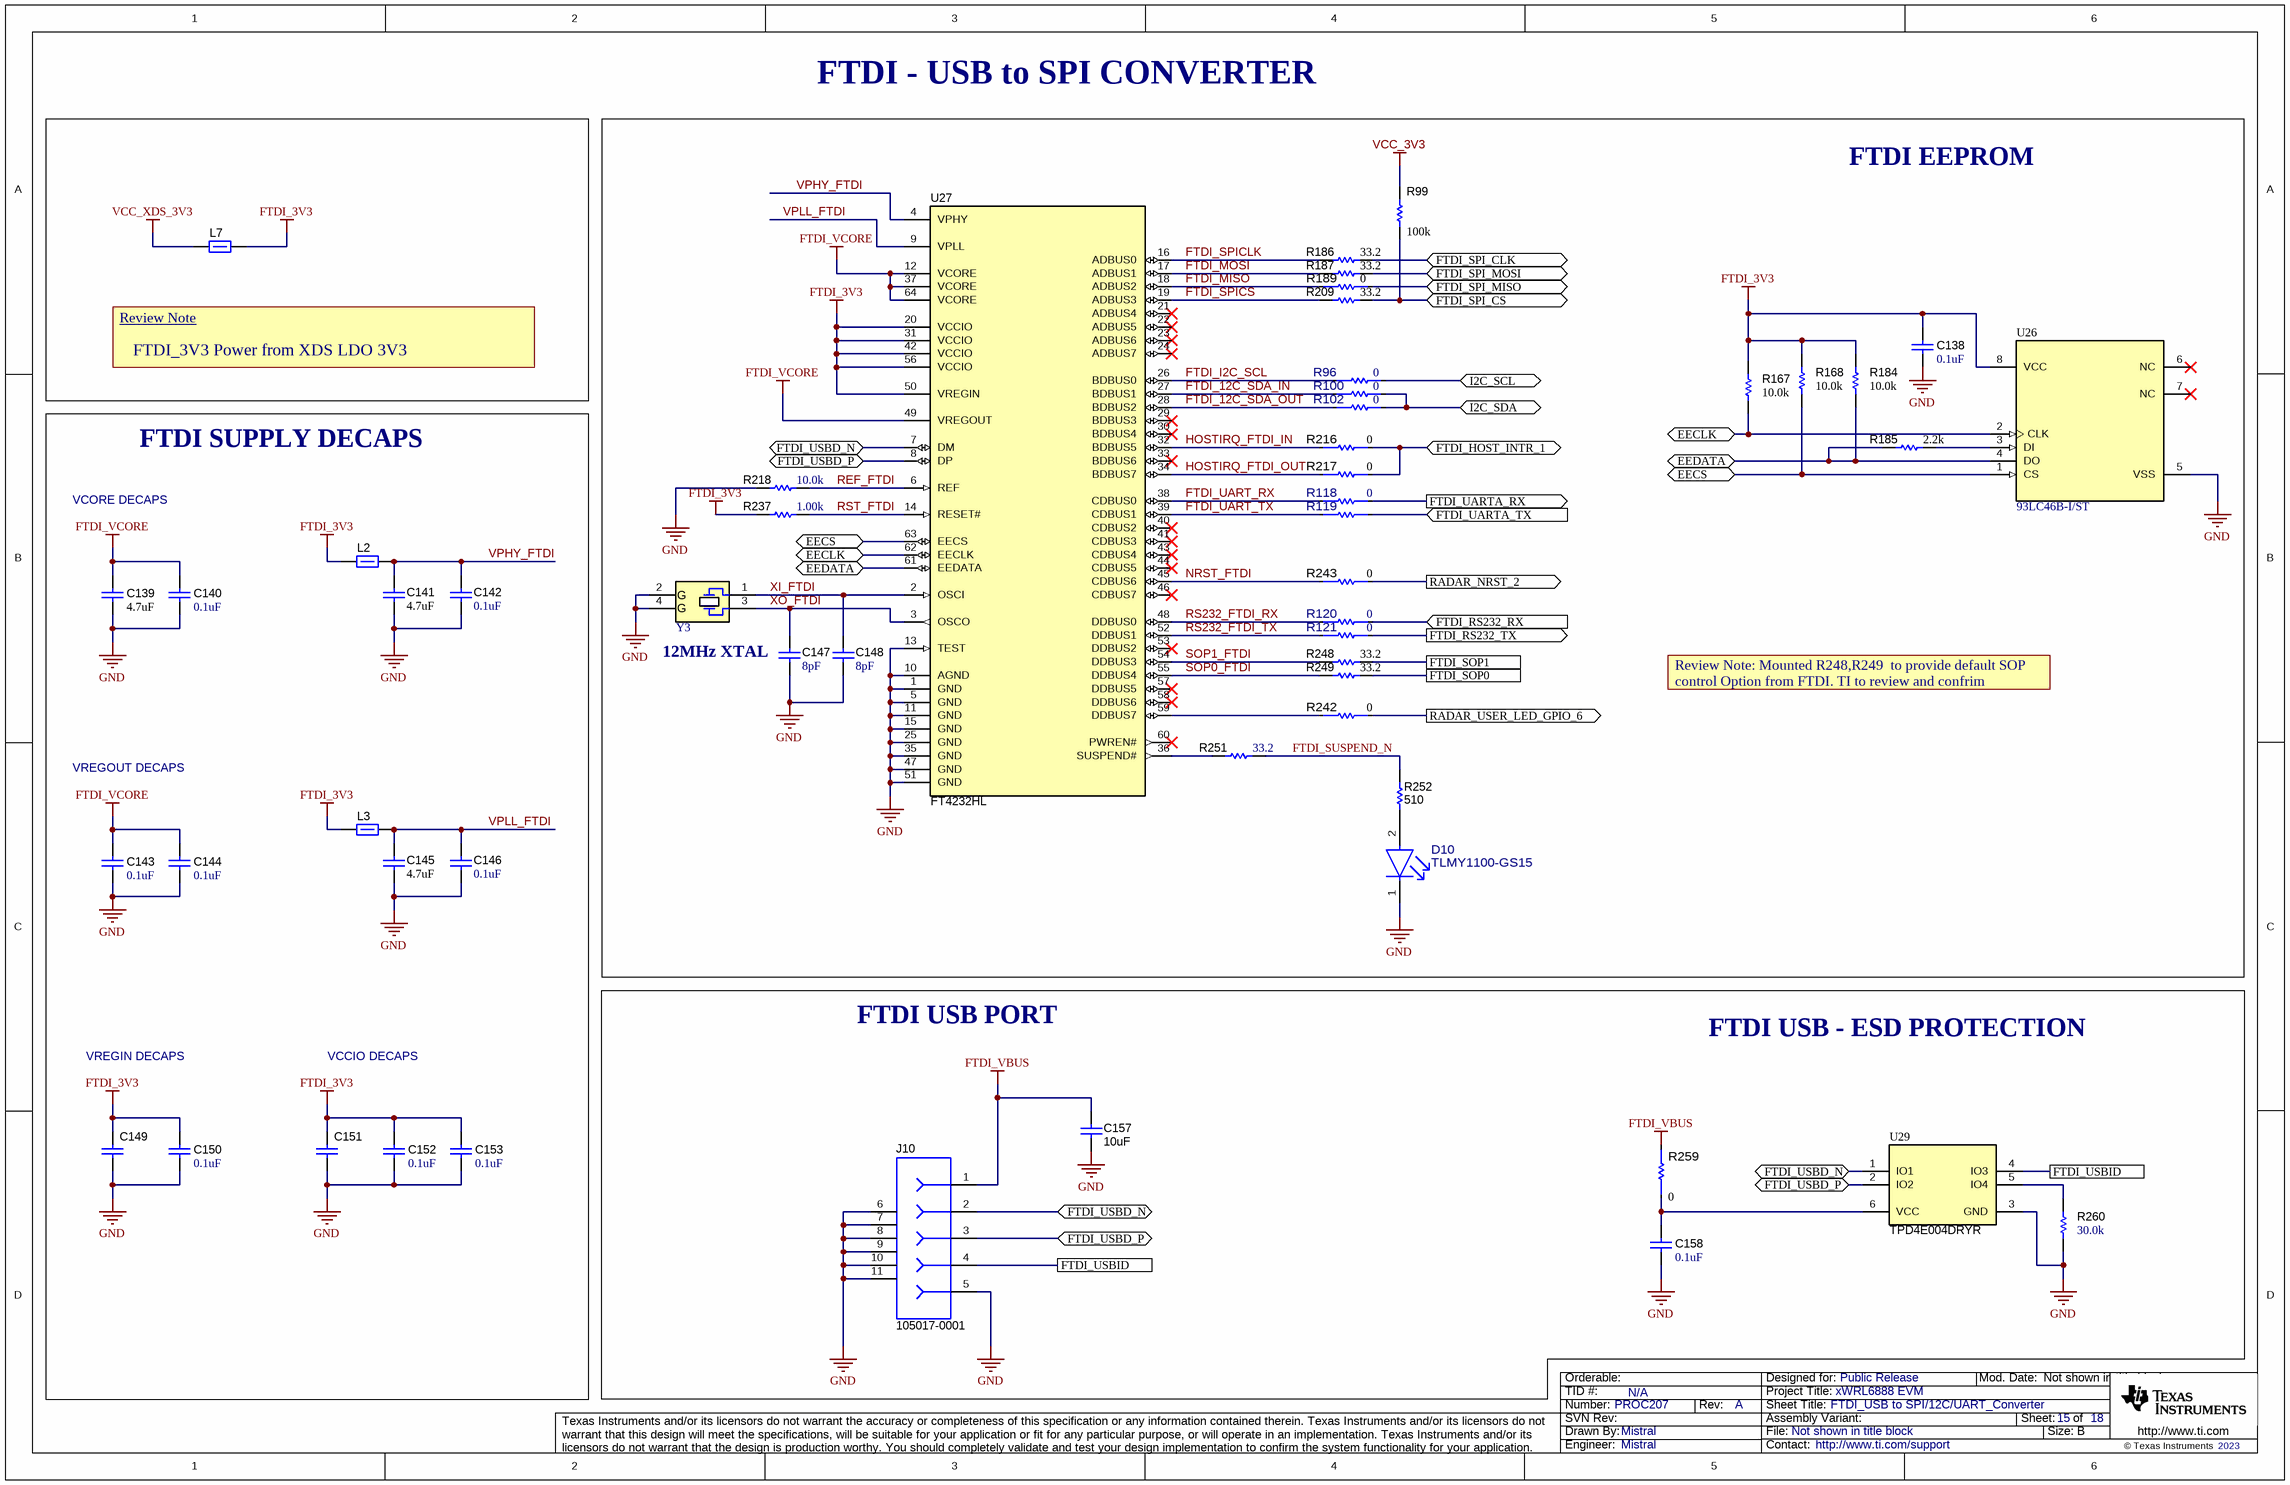
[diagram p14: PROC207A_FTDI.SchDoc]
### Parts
C138  ValueDisplayed: 0.1uF  [0402]  (hidden comment: GCM155R71H104KE02D)
C139  ValueDisplayed: 4.7uF  [0603L]  (hidden comment: C1608X7S1A475K080AC)
C140  ValueDisplayed: 0.1uF  [0402]  (hidden comment: GCM155R71H104KE02D)
C141  ValueDisplayed: 4.7uF  [0603L]  (hidden comment: C1608X7S1A475K080AC)
C142  ValueDisplayed: 0.1uF  [0402]  (hidden comment: GCM155R71H104KE02D)
C143  ValueDisplayed: 0.1uF  [0402]  (hidden comment: GCM155R71H104KE02D)
C144  ValueDisplayed: 0.1uF  [0402]  (hidden comment: GCM155R71H104KE02D)
C145  ValueDisplayed: 4.7uF  [0603L]  (hidden comment: C1608X7S1A475K080AC)
C146  ValueDisplayed: 0.1uF  [0402]  (hidden comment: GCM155R71H104KE02D)
C147  Cap_F: 8pF  [0402L]  (hidden comment: GCM1555C1H8R0DA16D)
C148  Cap_F: 8pF  [0402L]  (hidden comment: GCM1555C1H8R0DA16D)
C149  CL10B105KA8NNNC  [0603]  (value not drawn)
C150  ValueDisplayed: 0.1uF  [0402]  (hidden comment: GCM155R71H104KE02D)
C151  CL10B105KA8NNNC  [0603]  (value not drawn)
C152  ValueDisplayed: 0.1uF  [0402]  (hidden comment: GCM155R71H104KE02D)
C153  ValueDisplayed: 0.1uF  [0402]  (hidden comment: GCM155R71H104KE02D)
C157  ValueDisplayed: 10uF  [0603S]  (hidden comment: GRT188R61A106KE13D)
C158  ValueDisplayed: 0.1uF  [0402]  (hidden comment: GCM155R71H104KE02D)
D10  TLMY1100-GS15  [FP-TLMY1100-GS15_0603-MFG]
J10  105017-0001  [CONN_105017-0001]
L2  BLM15HG601SN1D  [0402L]  (value not drawn)
L3  BLM15HG601SN1D  [0402L]  (value not drawn)
L7  BLM15HG601SN1D  [0402L]  (value not drawn)
R96  value 0  [FP-ERJ-2GE0R00X_0402-MFG]  (hidden comment: ERJ-2GE0R00X)
R99  ValueDisplayed: 100k  [0402]  (hidden comment: CRCW0402100KFKED)
R100  value 0  [FP-ERJ-2GE0R00X_0402-MFG]  (hidden comment: ERJ-2GE0R00X)
R102  value 0  [FP-ERJ-2GE0R00X_0402-MFG]  (hidden comment: ERJ-2GE0R00X)
R118  value 0  [FP-ERJ-2GE0R00X_0402-MFG]  (hidden comment: ERJ-2GE0R00X)
R119  ERJ-2GE0R00X  [FP-ERJ-2GE0R00X_0402-MFG]  (value not drawn)
R120  value 0  [FP-ERJ-2GE0R00X_0402-MFG]  (hidden comment: ERJ-2GE0R00X)
R121  value 0  [FP-ERJ-2GE0R00X_0402-MFG]  (hidden comment: ERJ-2GE0R00X)
R167  ValueDisplayed: 10.0k  [0402L]  (hidden comment: CRCW040210K0FKED)
R168  ValueDisplayed: 10.0k  [0402L]  (hidden comment: CRCW040210K0FKED)
R184  ValueDisplayed: 10.0k  [0402L]  (hidden comment: CRCW040210K0FKED)
R185  ValueDisplayed: 2.2k  [0402L]  (hidden comment: CRCW04022K20JNED)
R186  ValueDisplayed: 33.2  [0402]  (hidden comment: CRCW040233R2FKED)
R187  ValueDisplayed: 33.2  [0402]  (hidden comment: CRCW040233R2FKED)
R189  value 0  [FP-ERJ-2GE0R00X_0402-MFG]  (hidden comment: ERJ-2GE0R00X)
R209  ValueDisplayed: 33.2  [0402]  (hidden comment: CRCW040233R2FKED)
R216  value 0  [FP-ERJ-2GE0R00X_0402-MFG]  (hidden comment: ERJ-2GE0R00X)
R217  value 0  [FP-ERJ-2GE0R00X_0402-MFG]  (hidden comment: ERJ-2GE0R00X)
R218  ValueDisplayed: 10.0k  [0402L]  (hidden comment: CRCW040210K0FKED)
R237  ValueDisplayed: 1.00k  [0402]  (hidden comment: ERJ-2RKF1001X)
R242  value 0  [FP-ERJ-2GE0R00X_0402-MFG]  (hidden comment: ERJ-2GE0R00X)
R243  value 0  [FP-ERJ-2GE0R00X_0402-MFG]  (hidden comment: ERJ-2GE0R00X)
R248  ValueDisplayed: 33.2  [0402]  (hidden comment: CRCW040233R2FKED)
R249  ValueDisplayed: 33.2  [0402]  (hidden comment: CRCW040233R2FKED)
R251  ValueDisplayed: 33.2  [0402]  (hidden comment: CRCW040233R2FKED)
R252  ValueDisplayed: 510  [0402L]  (hidden comment: ERJ-2GEJ511X)
R259  value 0  [FP-ERJ-2GE0R00X_0402-MFG]  (hidden comment: ERJ-2GE0R00X)
R260  ValueDisplayed: 30.0k  [0402L]  (hidden comment: CRCW040230K0FKED)
U26  93LC46B-I/ST  [TSSOP-8]
U27  FT4232HL  [LQFP64_N]
U29  TPD4E004DRYR  [DRY0006A]
Y3  NX3225SA-12.000M-STD-CRS-2  [NDK_NX3225SA]  (value not drawn)

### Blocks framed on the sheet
FTDI_3V3 Power from XDS LDO 3V3: L7
FTDI EEPROM: C138 C147 C148 D10 R96 R99 R100 R102 R118-R121 R167 R168 R184-R187 R189 R209 R216-R218 R237 R242 R243 R248 R249 R251 R252 U26 U27 Y3
FTDI SUPPLY DECAPS: C139-C146 C149-C153 L2 L3

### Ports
EECLK (bidir), EECS (bidir), EEDATA (bidir), FTDI_HOST_INTR_1 (bidir), FTDI_RS232_RX (in), FTDI_RS232_TX (out), FTDI_SOP0, FTDI_SOP1, FTDI_SPI_CLK (bidir), FTDI_SPI_CS (bidir), FTDI_SPI_MISO (bidir), FTDI_SPI_MOSI (bidir), FTDI_UARTA_RX (out), FTDI_UARTA_TX (in), FTDI_USBD_N (bidir), FTDI_USBD_P (bidir), FTDI_USBID, I2C_SCL (bidir), I2C_SDA (bidir), RADAR_NRST_2 (out), RADAR_USER_LED_GPIO_6 (out)

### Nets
FTDI_3V3: C138.1 C149.2 C150.1 C151.2 C152.1 C153.1 L2.1 L3.1 L7.2 R167.2 R168.2 R184.2 R237.1 U26.8(VCC) U27.20(VCCIO) U27.31(VCCIO) U27.42(VCCIO) U27.50(VREGIN) U27.56(VCCIO)
FTDI_VBUS: C157.2 J10.1 R259.2
FTDI_VCORE: C139.1 C140.1 C143.1 C144.1 U27.12(VCORE) U27.37(VCORE) U27.49(VREGOUT) U27.64(VCORE)
GND: C138.2 C139.2 C140.2 C141.2 C142.1 C143.2 C144.2 C145.2 C146.1 C147.2 C148.2 C149.1 C150.2 C151.1 C152.2 C153.2 C157.1 C158.2 D10.1(C) J10.5 J10.6 J10.7 J10.8 J10.9 J10.10 J10.11 R218.1 R260.1 U26.5(VSS) U27.1(GND) U27.5(GND) U27.10(AGND) U27.11(GND) U27.13(TEST) U27.15(GND) U27.25(GND) U27.35(GND) U27.47(GND) U27.51(GND) U29.3(GND) Y3.2(GND) Y3.4(GND)
VCC_3V3: R99.2
VCC_XDS_3V3: L7.1
EECLK: R167.1 U26.2(CLK) U27.62(EECLK) ; port EECLK
EECS: R168.1 U26.1(CS) U27.63(EECS) ; port EECS
EEDATA: R184.1 R185.1 U26.4(DO) U27.61(EEDATA) ; port EEDATA
FTDI_12C_SDA_IN: R100.1 U27.27(BDBUS1)
FTDI_12C_SDA_OUT: R102.1 U27.28(BDBUS2)
FTDI_HOST_INTR_1: R216.2 R217.2 ; port FTDI_HOST_INTR_1
FTDI_I2C_SCL: R96.1 U27.26(BDBUS0)
FTDI_MISO: R189.1 U27.18(ADBUS2)
FTDI_MOSI: R187.1 U27.17(ADBUS1)
FTDI_RS232_RX: R120.2 ; port FTDI_RS232_RX
FTDI_RS232_TX: R121.2 ; port FTDI_RS232_TX
FTDI_SOP0: R249.2 ; port FTDI_SOP0
FTDI_SOP1: R248.2 ; port FTDI_SOP1
FTDI_SPI_CLK: R186.2 ; port FTDI_SPI_CLK
FTDI_SPI_CS: R99.1 R209.2 ; port FTDI_SPI_CS
FTDI_SPI_MISO: R189.2 ; port FTDI_SPI_MISO
FTDI_SPI_MOSI: R187.2 ; port FTDI_SPI_MOSI
FTDI_SPICLK: R186.1 U27.16(ADBUS0)
FTDI_SPICS: R209.1 U27.19(ADBUS3)
FTDI_SUSPEND_N: R251.2 R252.1
FTDI_UART_RX: R118.1 U27.38(CDBUS0)
FTDI_UART_TX: R119.1 U27.39(CDBUS1)
FTDI_UARTA_RX: R118.2 ; port FTDI_UARTA_RX
FTDI_UARTA_TX: R119.2 ; port FTDI_UARTA_TX
FTDI_USBD_N: J10.2 U27.7(DM) U29.1(IO1) ; port FTDI_USBD_N
FTDI_USBD_P: J10.3 U27.8(DP) U29.2(IO2) ; port FTDI_USBD_P
FTDI_USBID: J10.4 U29.4(IO3) ; port FTDI_USBID
HOSTIRQ_FTDI_IN: R216.1 U27.32(BDBUS5)
HOSTIRQ_FTDI_OUT: R217.1 U27.34(BDBUS7)
I2C_SCL: R96.2 ; port I2C_SCL
I2C_SDA: R100.2 R102.2 ; port I2C_SDA
NRST_FTDI: R243.1 U27.45(CDBUS6)
RADAR_NRST_2: R243.2 ; port RADAR_NRST_2
RADAR_USER_LED_GPIO_6: R242.2 ; port RADAR_USER_LED_GPIO_6
REF_FTDI: R218.2 U27.6(REF)
RS232_FTDI_RX: R120.1 U27.48(DDBUS0)
RS232_FTDI_TX: R121.1 U27.52(DDBUS1)
RST_FTDI: R237.2 U27.14(RESET#)
SOP0_FTDI: R249.1 U27.55(DDBUS4)
SOP1_FTDI: R248.1 U27.54(DDBUS3)
VPHY_FTDI: C141.1 C142.2 L2.2 U27.4(VPHY)
VPLL_FTDI: C145.1 C146.2 L3.2 U27.9(VPLL)
XI_FTDI: C148.1 U27.2(OSCI) Y3.1
XO_FTDI: C147.1 U27.3(OSCO) Y3.3
NetC158_1: C158.1 R259.1 U29.6(VCC)
NetD10_2: D10.2(A) R252.2
NetR185_2: R185.2 U26.3(DI)
NetR242_1: R242.1 U27.59(DDBUS7)
NetR251_1: R251.1 U27.36(SUSPEND#)
NetR260_2: R260.2 U29.5(IO4)

Not connected (* = marked no-connect by the designer): U26 6(NC)* 7(NC)*; U27 21(ADBUS4)* 22(ADBUS5)* 23(ADBUS6)* 24(ADBUS7)* 29(BDBUS3)* 30(BDBUS4)* 33(BDBUS6)* 40(CDBUS2)* 41(CDBUS3)* 43(CDBUS4)* 44(CDBUS5)* 46(CDBUS7)* 53(DDBUS2)* 57(DDBUS5)* 58(DDBUS6)* 60(PWREN#)*

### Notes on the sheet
- FTDI - USB to SPI CONVERTER
- Review Note
- VCORE DECAPS
- 12MHz XTAL
- Review Note: Mounted R248,R249  to provide default SOP control Option from FTDI. TI to review and confrim
- VREGOUT DECAPS
- FTDI USB PORT
- VREGIN DECAPS
- VCCIO DECAPS
- FTDI USB - ESD PROTECTION

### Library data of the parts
C138 C140 C142-C144 C146 C150 C152 C153 C158 = CMP-0006356-2: as C94 on sheet PROC207A_XDS110_Interface
C139 C141 C145 = CMP-0007058-4: CAP, CERM, 4.7 uF, 10 V, +/- 10%, X7S, 0603; Manufacturer: TDK; TaMin_C: -55°C; Polarized: N; SizeAreaWB_mm2: 4.68; Value1: Unknown; U/M: EA; Value: 4.7uF; TaMax_C: 125°C; SizeZ_mm: 1; SizeX_mm: 1.6; SizeY_mm: 0.8; Cap_Case: 0603; Value2: 10V; SizeArea_mm2: 1.28; CompType: Capacitor; Cap_F: 4.7µF; AEC Category: Q200
C147 C148 = CMP-0087060-3: Cap Ceramic 8pF 50V C0G 0.5pF SMD 0402 125C Paper T/R; Manufacturer: Murata Electronics North America; AEC Qualified: Yes; TempCo: 30ppm/°C; AEC Grade: Grade 1; SizeZ_mm: 0.55mm
C149 C151 = CMP-0086540-3: CAP, 1uF, 25V, ±10%, X7R, 0603; Manufacturer: Samsung; TempCo: 15%; SizeZ_mm: 0.9mm; AEC Qualified: No; Cap_F: 1µF; Symbol Name: SYM-CL10B105KA8NNNC
C157 = CMP-0007497-5: CAP, CERM, 10 uF, 10 V, +/- 10%, X5R, 0603; Manufacturer: MuRata; Polarized: N; Value: 10uF; U/M: EA; Cap_F: 10µF; Tolerance_%: 20%; Value1: Unknown; VDC_V: 10V; TempCo: X7R; TaMin_C: -55°C; TaMax_C: 125°C; Cap_Case: 0603; SizeArea_mm2: 1.28; SizeAreaWB_mm2: 4.68; SizeX_mm: 1.6; SizeY_mm: 0.8; SizeZ_mm: 1; AEC Category: Q200
D10 = CMP-0121062-1: Yellow 589nm LED Indication - Discrete 2.1V 0603 (1608 Metric); Manufacturer: Vishay; Angle: 160°; LambdaP: 591nm; Power_TotalModule: 90mW; SizeZ_mm: 0.65mm; Tjmax_C: 120°C; Vr_V: 12V; AEC Grade: Grade 3; AEC Qualified: Yes; Forward Current: 20mA; Led Orientation: Top View; Luminous Intensity: 80mcd; TaMax_C: +100°C; TaMin_C: -40°C
J10 = CMP-0055293-1: Connector, Receptacle, Micro-USB Type B, R/A, Bottom Mount SMT; Manufacturer: Molex; CNHeader: FALSE; Green_Lifecycle: Active; Gender: Female; Green_REACh: Passed; CompType: USB; CT: TRUE
L2 L3 L7 = CMP-0081523-1: Ferrite Bead, 600 ohm @ 100 MHz, 0.3 A, 0402; Manufacturer: MuRata; SizeAreaWB_mm2: 3; SizeArea_mm2: 0.5; Value: 600 ohm; SizeZ_mm: 0.6; Imax_A: 3dA; ZTyp@100MHz_Ohm: 600; Value2: 0.3A; Value1: 0.7 ohm; DCR_ohm: 7d; SizeX_mm: 1; Ztyp@1GHz_Ohm: 1k
R96 R100 R102 R118 R120 R121 R189 R216 R217 R242 R243 R259 = CMP-0002710-1: as R24 on sheet PROC207A_XDS110_Interface
R99 = CMP-0025950-3: as R147 on sheet PROC207A_MUX_CAN_FD
R119 = CMP-0002710-1: 0 Ohms Jumper Chip Resistor 0402 (1005 Metric) Automotive AEC-Q200 Thick Film; Manufacturer: Panasonic; Value: 0; SizeZ_mm: 0.4mm; AEC Qualified: Yes; AEC Grade: Grade 0; Power: 100mW
R167 R168 R184 R218 = CMP-0025958-3: as R231 on sheet PROC207A_XDS110_Interface
R185 = CMP-0026890-5: RES, 2.2 k, 5%, 0.063 W, AEC-Q200 Grade 0, 0402; Manufacturer: Vishay-Dale; Power_W: 63mW; TempCo: 200 ppm/C; Value_Code: 2k20; Value: 2.2k; EIA_Code: E24; SizeX_mm: 1; SizeY_mm: 0.5; SizeZ_mm: 0.6; Value2: 0.063W; AEC Qualified: Y; VDC_V: 50V; AEC Category: Q200; AEC Grade: 0
R186 R187 R209 R248 R249 R251 = CMP-0026299-2: RES, 33.2, 1%, 0.063 W, AEC-Q200 Grade 0, 0402; Manufacturer: Vishay-Dale; Power_W: 63mW; TempCo: 100 ppm/C; Value_Code: 33R2; Value: 33.2; EIA_Code: E96; SizeX_mm: 1; SizeY_mm: 0.5; SizeZ_mm: 0.6; Value2: 0.063W; AEC Qualified: Y; VDC_V: 50V; AEC Category: Q200; AEC Grade: 0
R237 = CMP-0026657-1: as R191 on sheet PROC207A_XDS110_Interface
R252 = CMP-0078212-1: RES, 510, 5%, 0.1 W, AEC-Q200 Grade 0, 0402; Manufacturer: Panasonic; Value_Code: 510R; SizeArea_mm2: 0.5; AEC Qualified: Y; AEC Category: Q200; Value: 510; SizeZ_mm: 0.6; EIA_Code: E24; TempCo: 200 ppm/C; AEC Grade: 0; Power_W: 100mW; VDC_V: 50V; Value2: 0.1W; U/M: EA; SizeX_mm: 1
R260 = CMP-0078244-2: RES, 30.0 k, 1%, 0.063 W, AEC-Q200 Grade 0, 0402; Manufacturer: Vishay-Dale; Power_W: 63mW; Green_Lifecycle: Active; TempCo: 100 ppm/C; Value_Code: 30k0; Green_REACh: Passed; Value: 30.0k; Res_ohm: 30k; SizeX_mm: 1; SizeY_mm: 0.5; SizeZ_mm: 0.6; Value2: 0.063W; AEC Qualified: Y; VDC_V: 50V; AEC Grade: 0; AEC Category: Q200
U26 = CMP-0081524-1: 1K Microwire Compatible Serial EEPROM, TSSOP-8; Manufacturer: Microchip; SizeArea_mm2: 19.2; SizeAreaWB_mm2: 42; SizeY_mm: 3; SizeZ_mm: 1.2; SizeX_mm: 6.4
U27 = CMP-0004747-1: Quad High Speed USB to Multipurpose UART/MPSSE IC; Manufacturer: FTDI
U29 = CMP-0043115-3: 4-Channel ESD Protection Array for High-Speed Data Interfaces, DRY0006A (USON-6); Manufacturer: Texas Instruments; IO Leakage Current(nA): 1; USB High Speed: TRUE; IO Capacitance(Typ)(pF): 1.6; Eco-Plan: Green (RoHS & no Sb/Br); IEC 61000-4-2 Contact(+/- kV): 8; Breakdown Voltage(Min)(V): 6; IEC 61000-4-2 Air-Gap(+/- kV): 12; AEC Category: Q200; AEC Qualified: N; CompType: IC; SizeAreaWB_mm2: 4.9; SizeArea_mm2: 1.45; SizeX_mm: 1.0; SizeZ_mm: 0.6; Rating: Catalog
Y3 = CMP-0081529-1: Crystal, 12 MHz, 15 ppm, 8 pF, AEC-Q200 Grade 1, SMD; Manufacturer: NDK; TaMin_C: -40°C; Frequency Tolerance: 15 ppm; Frequency Stability: 50 ppm; Load Capacitance: 8 pF; Frequency_Fixed: 12MHz; TaMax_C: 125°C; AEC Qualified: Y; AEC Grade: 1; AEC Category: Q200

## Sheet PROC207A_DCA1000_Connector_Reset.SchDoc: DCA1000_CONN_RESET
size 431 x 279 mm; Date: Not shown in title block; ApprovedBy: Not shown in title block; CheckedBy: Not shown in title block; Author: Not shown in title block; CompanyName: Not shown in title block; DrawnBy: Mistral; Engineer: Not shown in title block; Organization: Not shown in title block; Address1: Not shown in title block; Address2: Not shown in title block; Address3: Not shown in title block; Address4: Not shown in title block; DocumentNumber: 15; Revision: Use project parameter SCH_Rev; SheetNumber: 16; SheetTotal: 18; PageSetup: Record=PageOptions¦CenterHorizontal=True¦CenterVertical=True¦PrintScale=1.00¦XCorrection=1.00¦YCorrection=1.00¦PrintKind=0¦BorderSize=5000000¦LeftOffset=0¦BottomOffset=0¦Orientation=2¦PaperLength=1000¦PaperWidth=1000¦Scale=100¦PaperSource=15¦PrintQuality=600¦MediaType=1¦DitherType=10¦PaperKind=Letter¦PrintScaleMode=1

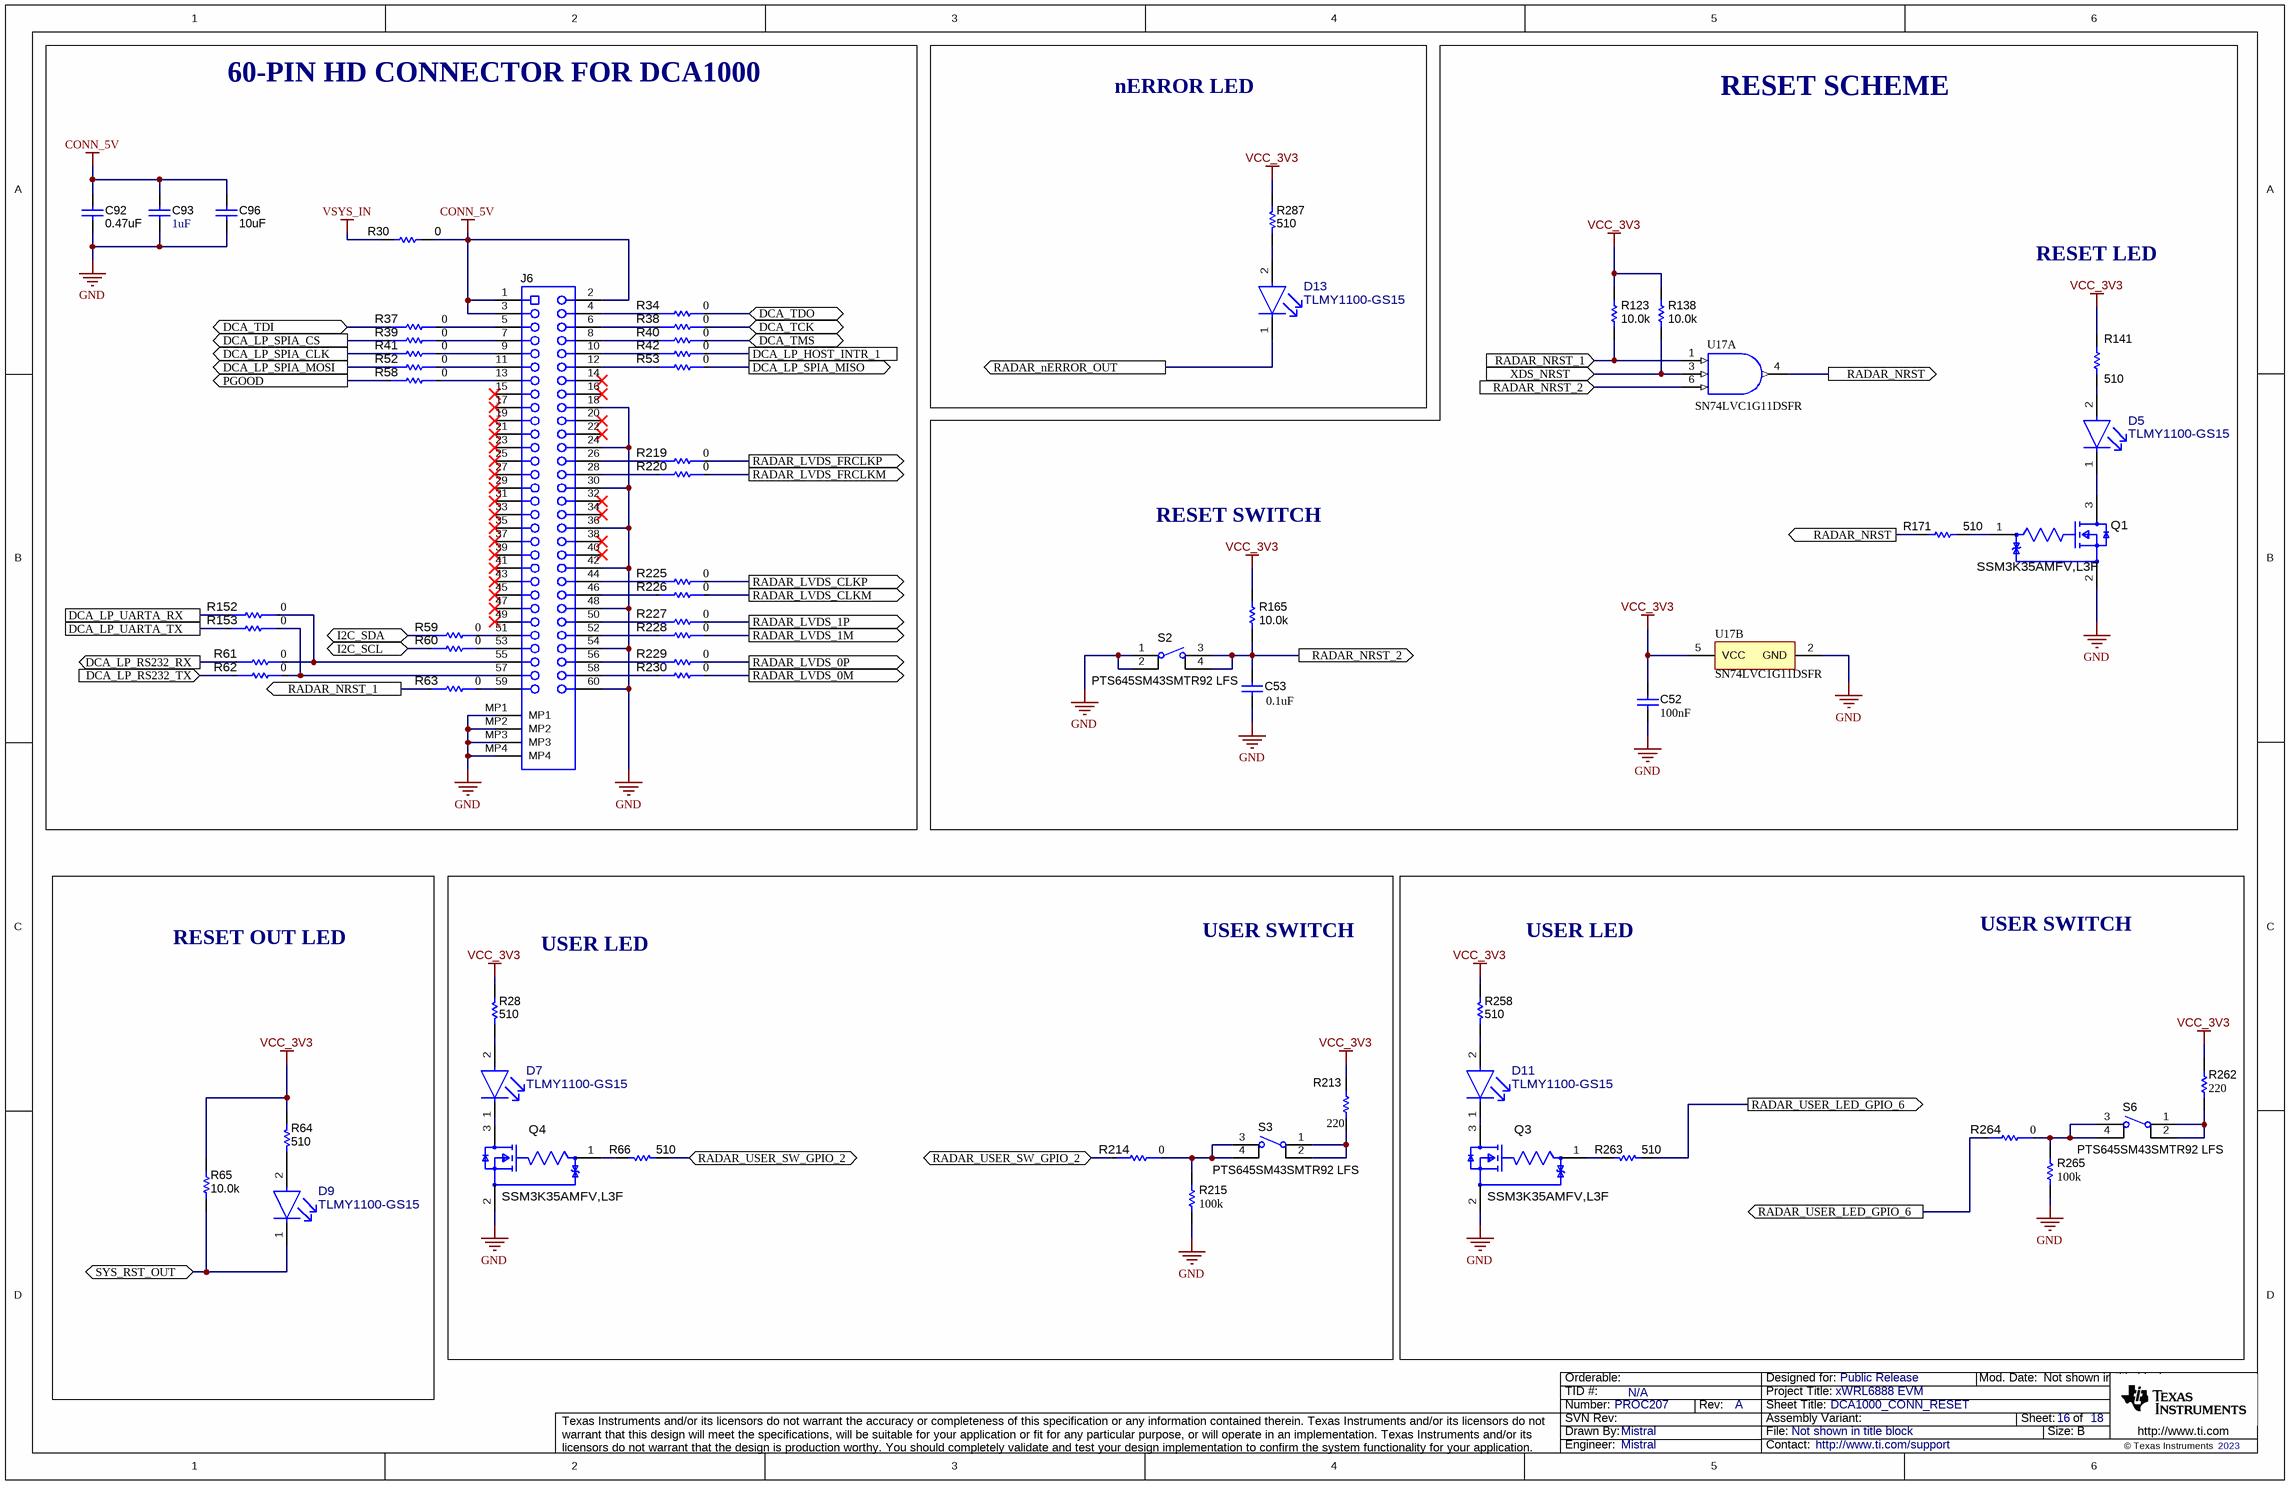
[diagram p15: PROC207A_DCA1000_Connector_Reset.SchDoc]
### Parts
C52  Cap_F: 100nF  [0402]  (hidden comment: GCM155R71H104KE02D)
C53  ValueDisplayed: 0.1uF  [0402]  (hidden comment: GCM155R71H104KE02D)
C92  ValueDisplayed: 0.47uF  [0402L]  (hidden comment: GCM155C71A474KE36D)
C93  ValueDisplayed: 1uF  [0402_070]  (hidden comment: GCM155C71A105KE38D)
C96  ValueDisplayed: 10uF  [0603S]  (hidden comment: GRT188R61A106KE13D)
D5  TLMY1100-GS15  [FP-TLMY1100-GS15_0603-MFG]
D7  TLMY1100-GS15  [FP-TLMY1100-GS15_0603-MFG]
D9  TLMY1100-GS15  [FP-TLMY1100-GS15_0603-MFG]
D11  TLMY1100-GS15  [FP-TLMY1100-GS15_0603-MFG]
D13  TLMY1100-GS15  [FP-TLMY1100-GS15_0603-MFG]
J6  QSH-030-01-L-D-A  [Samtec_QSH-030-01-X-D-A]  (value not drawn)
Q1  SSM3K35AMFV,L3F  [FP-SSM3K35AMFV,L3F_SOT-723-MFG]
Q3  SSM3K35AMFV,L3F  [FP-SSM3K35AMFV,L3F_SOT-723-MFG]
Q4  SSM3K35AMFV,L3F  [FP-SSM3K35AMFV,L3F_SOT-723-MFG]
R28  ValueDisplayed: 510  [0402L]  (hidden comment: ERJ-2GEJ511X)
R30  ValueDisplayed: 0  [0603]  (hidden comment: MCT06030Z0000ZP500)
R34  value 0  [FP-ERJ-2GE0R00X_0402-MFG]  (hidden comment: ERJ-2GE0R00X)
R37  value 0  [FP-ERJ-2GE0R00X_0402-MFG]  (hidden comment: ERJ-2GE0R00X)
R38  value 0  [FP-ERJ-2GE0R00X_0402-MFG]  (hidden comment: ERJ-2GE0R00X)
R39  value 0  [FP-ERJ-2GE0R00X_0402-MFG]  (hidden comment: ERJ-2GE0R00X)
R40  value 0  [FP-ERJ-2GE0R00X_0402-MFG]  (hidden comment: ERJ-2GE0R00X)
R41  value 0  [FP-ERJ-2GE0R00X_0402-MFG]  (hidden comment: ERJ-2GE0R00X)
R42  value 0  [FP-ERJ-2GE0R00X_0402-MFG]  (hidden comment: ERJ-2GE0R00X)
R52  value 0  [FP-ERJ-2GE0R00X_0402-MFG]  (hidden comment: ERJ-2GE0R00X)
R53  value 0  [FP-ERJ-2GE0R00X_0402-MFG]  (hidden comment: ERJ-2GE0R00X)
R58  value 0  [FP-ERJ-2GE0R00X_0402-MFG]  (hidden comment: ERJ-2GE0R00X)
R59  value 0  [FP-ERJ-2GE0R00X_0402-MFG]  (hidden comment: ERJ-2GE0R00X)
R60  value 0  [FP-ERJ-2GE0R00X_0402-MFG]  (hidden comment: ERJ-2GE0R00X)
R61  value 0  [FP-ERJ-2GE0R00X_0402-MFG]  (hidden comment: ERJ-2GE0R00X)
R62  value 0  [FP-ERJ-2GE0R00X_0402-MFG]  (hidden comment: ERJ-2GE0R00X)
R63  value 0  [FP-ERJ-2GE0R00X_0402-MFG]  (hidden comment: ERJ-2GE0R00X)
R64  ValueDisplayed: 510  [0402L]  (hidden comment: ERJ-2GEJ511X)
R65  ValueDisplayed: 10.0k  [0402L]  (hidden comment: CRCW040210K0FKED)
R66  ValueDisplayed: 510  [0402L]  (hidden comment: ERJ-2GEJ511X)
R123  ValueDisplayed: 10.0k  [0402L]  (hidden comment: CRCW040210K0FKED)
R138  ValueDisplayed: 10.0k  [0402L]  (hidden comment: CRCW040210K0FKED)
R141  ValueDisplayed: 510  [0402L]  (hidden comment: ERJ-2GEJ511X)
R152  value 0  [FP-ERJ-2GE0R00X_0402-MFG]  (hidden comment: ERJ-2GE0R00X)
R153  value 0  [FP-ERJ-2GE0R00X_0402-MFG]  (hidden comment: ERJ-2GE0R00X)
R165  ValueDisplayed: 10.0k  [0402L]  (hidden comment: CRCW040210K0FKED)
R171  ValueDisplayed: 510  [0402L]  (hidden comment: ERJ-2GEJ511X)
R213  ValueDisplayed: 220  [0402]  (hidden comment: CRCW0402220RJNED)
R214  Res_ohm: 0  [FP-ERJ-2GE0R00X_0402-MFG]  (hidden comment: ERJ-2GE0R00X)
R215  value 100k  [0402]  (hidden comment: CRCW0402100KFKED)
R219  value 0  [FP-ERJ-2GE0R00X_0402-MFG]  (hidden comment: ERJ-2GE0R00X)
R220  value 0  [FP-ERJ-2GE0R00X_0402-MFG]  (hidden comment: ERJ-2GE0R00X)
R225  value 0  [FP-ERJ-2GE0R00X_0402-MFG]  (hidden comment: ERJ-2GE0R00X)
R226  value 0  [FP-ERJ-2GE0R00X_0402-MFG]  (hidden comment: ERJ-2GE0R00X)
R227  value 0  [FP-ERJ-2GE0R00X_0402-MFG]  (hidden comment: ERJ-2GE0R00X)
R228  value 0  [FP-ERJ-2GE0R00X_0402-MFG]  (hidden comment: ERJ-2GE0R00X)
R229  value 0  [FP-ERJ-2GE0R00X_0402-MFG]  (hidden comment: ERJ-2GE0R00X)
R230  value 0  [FP-ERJ-2GE0R00X_0402-MFG]  (hidden comment: ERJ-2GE0R00X)
R258  ValueDisplayed: 510  [0402L]  (hidden comment: ERJ-2GEJ511X)
R262  ValueDisplayed: 220  [0402]  (hidden comment: CRCW0402220RJNED)
R263  ValueDisplayed: 510  [0402L]  (hidden comment: ERJ-2GEJ511X)
R264  Res_ohm: 0  [FP-ERJ-2GE0R00X_0402-MFG]  (hidden comment: ERJ-2GE0R00X)
R265  value 100k  [0402]  (hidden comment: CRCW0402100KFKED)
R287  ValueDisplayed: 510  [0402L]  (hidden comment: ERJ-2GEJ511X)
S2  PTS645SM43SMTR92 LFS  [SW_PTS645SM43SMT]
S3  PTS645SM43SMTR92 LFS  [SW_PTS645SM43SMT]
S6  PTS645SM43SMTR92 LFS  [SW_PTS645SM43SMT]
U17  SN74LVC1G11DSFR  [DSF0006A]  (parts A,B of 2)

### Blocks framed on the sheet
60-PIN HD CONNECTOR FOR DCA1000: C92 C93 C96 J6 R30 R34 R37-R42 R52 R53 R58-R63 R152 R153 R219 R220 R225-R230
RESET SCHEME: C52 C53 D5 Q1 R123 R138 R141 R165 R171 S2 U17
nERROR LED: D13 R287
RESET OUT LED: D9 R64 R65

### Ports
DCA_LP_HOST_INTR_1, DCA_LP_RS232_RX (out), DCA_LP_RS232_TX (in), DCA_LP_SPIA_CLK (out), DCA_LP_SPIA_CS (out), DCA_LP_SPIA_MISO (out), DCA_LP_SPIA_MOSI (out), DCA_LP_UARTA_RX, DCA_LP_UARTA_TX, DCA_TCK (bidir), DCA_TDI (bidir), DCA_TDO (bidir), DCA_TMS (bidir), I2C_SCL (bidir), I2C_SDA (bidir), PGOOD (out), RADAR_LVDS_0M (out), RADAR_LVDS_0P (out), RADAR_LVDS_1M (out), RADAR_LVDS_1P (out), RADAR_LVDS_CLKM (out), RADAR_LVDS_CLKP (out), RADAR_LVDS_FRCLKM (out), RADAR_LVDS_FRCLKP (out), RADAR_nERROR_OUT (out), RADAR_NRST (out), RADAR_NRST_1 (in), RADAR_NRST_1 (out), RADAR_NRST_2 (in), RADAR_NRST_2 (out), RADAR_USER_LED_GPIO_6 (out), RADAR_USER_SW_GPIO_2 (bidir), SYS_RST_OUT (bidir), XDS_NRST (in)

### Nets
CONN_5V: C92.1 C93.1 C96.2 J6.1 J6.2 J6.3 R30.2
GND: C52.1 C53.2 C92.2 C93.2 C96.1 J6.18 J6.24 J6.30 J6.36 J6.42 J6.48 J6.54 J6.60 J6.MP1 J6.MP2 J6.MP3 J6.MP4 Q1.2(S) Q3.2(S) Q4.2(S) R215.2 R265.2 S2.1 S2.2 U17.2(GND)
VCC_3V3: C52.2 R28.2 R64.2 R65.1 R123.2 R138.2 R141.2 R165.2 R213.2 R258.2 R262.2 R287.2 U17.5(VCC)
VSYS_IN: R30.1
DCA_LP_HOST_INTR_1: R42.2 ; port DCA_LP_HOST_INTR_1
DCA_LP_RS232_RX: R61.1 ; port DCA_LP_RS232_RX
DCA_LP_RS232_TX: R62.1 ; port DCA_LP_RS232_TX
DCA_LP_SPIA_CLK: R41.1 ; port DCA_LP_SPIA_CLK
DCA_LP_SPIA_CS: R39.1 ; port DCA_LP_SPIA_CS
DCA_LP_SPIA_MISO: R53.2 ; port DCA_LP_SPIA_MISO
DCA_LP_SPIA_MOSI: R52.1 ; port DCA_LP_SPIA_MOSI
DCA_LP_UARTA_RX: R152.2 ; port DCA_LP_UARTA_RX
DCA_LP_UARTA_TX: R153.2 ; port DCA_LP_UARTA_TX
DCA_TCK: R38.2 ; port DCA_TCK
DCA_TDI: R37.1 ; port DCA_TDI
DCA_TDO: R34.2 ; port DCA_TDO
DCA_TMS: R40.2 ; port DCA_TMS
I2C_SCL: R60.1 ; port I2C_SCL
I2C_SDA: R59.1 ; port I2C_SDA
PGOOD: R58.1 ; port PGOOD
RADAR_LVDS_0M: R230.2 ; port RADAR_LVDS_0M
RADAR_LVDS_0P: R229.2 ; port RADAR_LVDS_0P
RADAR_LVDS_1M: R228.2 ; port RADAR_LVDS_1M
RADAR_LVDS_1P: R227.2 ; port RADAR_LVDS_1P
RADAR_LVDS_CLKM: R226.2 ; port RADAR_LVDS_CLKM
RADAR_LVDS_CLKP: R225.2 ; port RADAR_LVDS_CLKP
RADAR_LVDS_FRCLKM: R220.2 ; port RADAR_LVDS_FRCLKM
RADAR_LVDS_FRCLKP: R219.2 ; port RADAR_LVDS_FRCLKP
RADAR_nERROR_OUT: D13.1(C) ; port RADAR_nERROR_OUT
RADAR_NRST: R171.2 U17.4(Y) ; port RADAR_NRST
RADAR_NRST_1: R63.1 R123.1 U17.1(A) ; port RADAR_NRST_1
RADAR_NRST_2: C53.1 R165.1 S2.3 S2.4 U17.6(C) ; port RADAR_NRST_2
RADAR_USER_LED_GPIO_6: R263.2 R264.2 ; port RADAR_USER_LED_GPIO_6
RADAR_USER_SW_GPIO_2: R66.2 R214.2 ; port RADAR_USER_SW_GPIO_2
SYS_RST_OUT: D9.1(C) R65.2 ; port SYS_RST_OUT
XDS_NRST: R138.1 U17.3(B) ; port XDS_NRST
NetD5_1: D5.1(C) Q1.3(D)
NetD5_2: D5.2(A) R141.1
NetD7_1: D7.1(C) Q4.3(D)
NetD7_2: D7.2(A) R28.1
NetD9_2: D9.2(A) R64.1
NetD11_1: D11.1(C) Q3.3(D)
NetD11_2: D11.2(A) R258.1
NetD13_2: D13.2(A) R287.1
NetJ6_4: J6.4 R34.1
NetJ6_5: J6.5 R37.2
NetJ6_6: J6.6 R38.1
NetJ6_7: J6.7 R39.2
NetJ6_8: J6.8 R40.1
NetJ6_9: J6.9 R41.2
NetJ6_10: J6.10 R42.1
NetJ6_11: J6.11 R52.2
NetJ6_12: J6.12 R53.1
NetJ6_13: J6.13 R58.2
NetJ6_26: J6.26 R219.1
NetJ6_28: J6.28 R220.1
NetJ6_44: J6.44 R225.1
NetJ6_46: J6.46 R226.1
NetJ6_50: J6.50 R227.1
NetJ6_51: J6.51 R59.2
NetJ6_52: J6.52 R228.1
NetJ6_53: J6.53 R60.2
NetJ6_55: J6.55 R61.2 R152.1
NetJ6_56: J6.56 R229.1
NetJ6_57: J6.57 R62.2 R153.1
NetJ6_58: J6.58 R230.1
NetJ6_59: J6.59 R63.2
NetQ1_1: Q1.1(G) R171.1
NetQ3_1: Q3.1(G) R263.1
NetQ4_1: Q4.1(G) R66.1
NetR213_1: R213.1 S3.1 S3.2
NetR214_1: R214.1 R215.1 S3.3 S3.4
NetR262_1: R262.1 S6.1 S6.2
NetR264_1: R264.1 R265.1 S6.3 S6.4

Not connected (* = marked no-connect by the designer): J6 14* 15* 16* 17* 19* 20* 21* 22* 23* 25* 27* 29* 31* 32* 33* 34* 35* 37* 38* 39* 40* 41* 43* 45* 47* 49*

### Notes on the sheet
- RESET LED
- RESET SWITCH
- USER LED
- USER SWITCH

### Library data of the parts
C52 = CMP-0006356-2: CAP, CERM, 0.1 uF, 50 V, +/- 10%, X7R, AEC-Q200 Grade 1, 0402; Manufacturer: MuRata; AEC Qualified: Y; SizeZ_mm: 0.6; VDC_V: 50V; AEC Category: Q200; AEC Grade: 1; Polarized: N; SizeArea_mm2: 0.5; SizeAreaWB_mm2: 3; TaMax_C: 125°C; TaMin_C: -55°C; U/M: EA; Value1: Unknown; Value: 0.1uF
C53 = CMP-0006356-2: as C123 on sheet PROC207A_CAN_LIN_PHY_Interface
C92 = CMP-0064967-2: CAP, CERM, 0.47 uF, 10 V,+/- 10%, X7S, 0402; Manufacturer: MuRata; Polarized: N; Value: 0.47uF; U/M: EA; Cap_F: 470nF; Value1: Unknown; VDC_V: 10V; TaMin_C: -55°C; TaMax_C: 125°C; Cap_Case: 0402; SizeArea_mm2: 0.5; SizeAreaWB_mm2: 3; SizeX_mm: 1; SizeZ_mm: 0.6; AEC Category: Q200
C93 = CMP-0006349-2: as C108 on sheet PROC207A_XDS110_Interface
C96 = CMP-0007497-5: as C157 on sheet PROC207A_FTDI
D5 D7 D9 D11 D13 = CMP-0121062-1: as D10 on sheet PROC207A_FTDI
J6 = CMP-0075524-1: Receptacle, 0.5 mm, 30x2, Gold, TH; Manufacturer: Samtec; Pitch_mm: 0.5; Gender: Female; Green_REACh: Passed; CT: False; Shrouded: N; RowSpacing_mm: 5.73; Green_Lifecycle: Active; Row_Count: 2
Q1 Q3 Q4 = CMP-0091833-1: N-Channel 20V 250mA (Ta) 500mW (Ta) Surface Mount VESM; Manufacturer: Toshiba; Threshold Vgs Min: 0.35V; QgTyp_nC: 0.34nC @ 4.5V; AEC Qualified: No; Rdson45_ohm: 0.75; TJmax_C: +150°C; Input Capacitace At Vds: 18pF @ 10V; SizeZ_mm: 0.55mm; Pulse Drain Current: 600mA; Threshold Vgs Max: 1V; Vgs_V: 10V; Typ Forward Diode Voltage: 0.8V; VdsMax_V: 1.2V; Power_W: 150mW; Number Of N Channels: 1; Turn Off Delay Time: 6.5ns; ChMode: False; Turn On Delay Time: 2ns
R28 R64 R66 R141 R171 R258 R263 R287 = CMP-0078212-1: as R252 on sheet PROC207A_FTDI
R30 = CMP-0025884-3: as R31 on sheet PROC207A_CAN_LIN_PHY_Interface
R34 R37-R42 R52 R53 R58-R63 R152 R153 R219 R220 R225-R230 = CMP-0002710-1: as R24 on sheet PROC207A_XDS110_Interface
R65 R123 R138 R165 = CMP-0025958-3: as R231 on sheet PROC207A_XDS110_Interface
R213 R262 = CMP-0026878-3: RES, 220, 5%, 0.063 W, AEC-Q200 Grade 0, 0402; Manufacturer: Vishay-Dale; Power_W: 63mW; TempCo: 200 ppm/C; Value_Code: 220R; Value: 220; EIA_Code: E24; SizeX_mm: 1; SizeY_mm: 0.5; SizeZ_mm: 0.6; Value2: 0.063W; AEC Qualified: Y; VDC_V: 50V; AEC Category: Q200; AEC Grade: 0
R214 R264 = CMP-0002710-1: 0 Ohms Jumper Chip Resistor 0402 (1005 Metric) Automotive AEC-Q200 Thick Film; Manufacturer: Panasonic; AEC Qualified: Yes; SizeZ_mm: 0.4mm; AEC Grade: Grade 0; Power: 100mW; Value: 0
R215 R265 = CMP-0025950-3: RES, 100 k, 1%, 0.063 W, AEC-Q200 Grade 0, 0402; Manufacturer: Vishay-Dale; AEC Category: Q200; AEC Grade: 0; AEC Qualified: Y; EIA_Code: E96; Power_W: 63mW; SizeArea_mm2: 0.5; SizeX_mm: 1; SizeZ_mm: 0.6; TempCo: 100 ppm/C; Value2: 0.063W; VDC_V: 50V
S2 S3 S6 = CMP-0079642-1: Switch, SPST-NO, Off-Mom, 0.05 A, 12 VDC, SMD; Manufacturer: C&K Components; SizeAreaWB_mm2: 88; SizeArea_mm2: 54; SizeZ_mm: 4.4; SizeY_mm: 6; VDC_V: 12V; CurrentRating_mA: 50A; PositionCount: 1; SizeX_mm: 9
U17 = CMP-0051215-4: Single 3-Input Positive-AND Gate, DSF0006A, LARGE T&R; Manufacturer: Texas Instruments; Output Type: CMOS; Bits(#): 1; Input Type: CMOS/TTL; Technology Family: LVC; Schmitt Trigger: No; VCC(Max)(V): 5.5; Gate Type: AND; Rating: Catalog; Output Drive (IOL/IOH)(Max)(mA): 32/-32; ICC @ Nom Voltage(Max)(mA): 0.01; VCC(Min)(V): 1.65; F @ Nom Voltage(Max)(Mhz): 150; Logic: True; Voltage(Nom)(V): 1.8,2.5,3.3,5; tpd @ Nom Voltage(Max)(ns): 20,7.8,6.2,4.6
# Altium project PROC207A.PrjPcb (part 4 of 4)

## Sheet PROC207A_I2C_SPI_Connector.SchDoc: I2C_SPI_UART_LP/BP_INTERFACE_CONN_HEADER
size 431 x 279 mm; Date: Not shown in title block; ApprovedBy: Not shown in title block; CheckedBy: Not shown in title block; Author: Not shown in title block; CompanyName: Not shown in title block; DrawnBy: Mistral; Engineer: Not shown in title block; Organization: Not shown in title block; Address1: Not shown in title block; Address2: Not shown in title block; Address3: Not shown in title block; Address4: Not shown in title block; DocumentNumber: 16; Revision: Use project parameter SCH_Rev; SheetNumber: 16; SheetTotal: 17; PageSetup: Record=PageOptions¦CenterHorizontal=True¦CenterVertical=True¦PrintScale=1.00¦XCorrection=1.00¦YCorrection=1.00¦PrintKind=0¦BorderSize=5000000¦LeftOffset=0¦BottomOffset=0¦Orientation=2¦PaperLength=1000¦PaperWidth=1000¦Scale=100¦PaperSource=15¦PrintQuality=600¦MediaType=1¦DitherType=10¦PaperKind=Letter¦PrintScaleMode=1

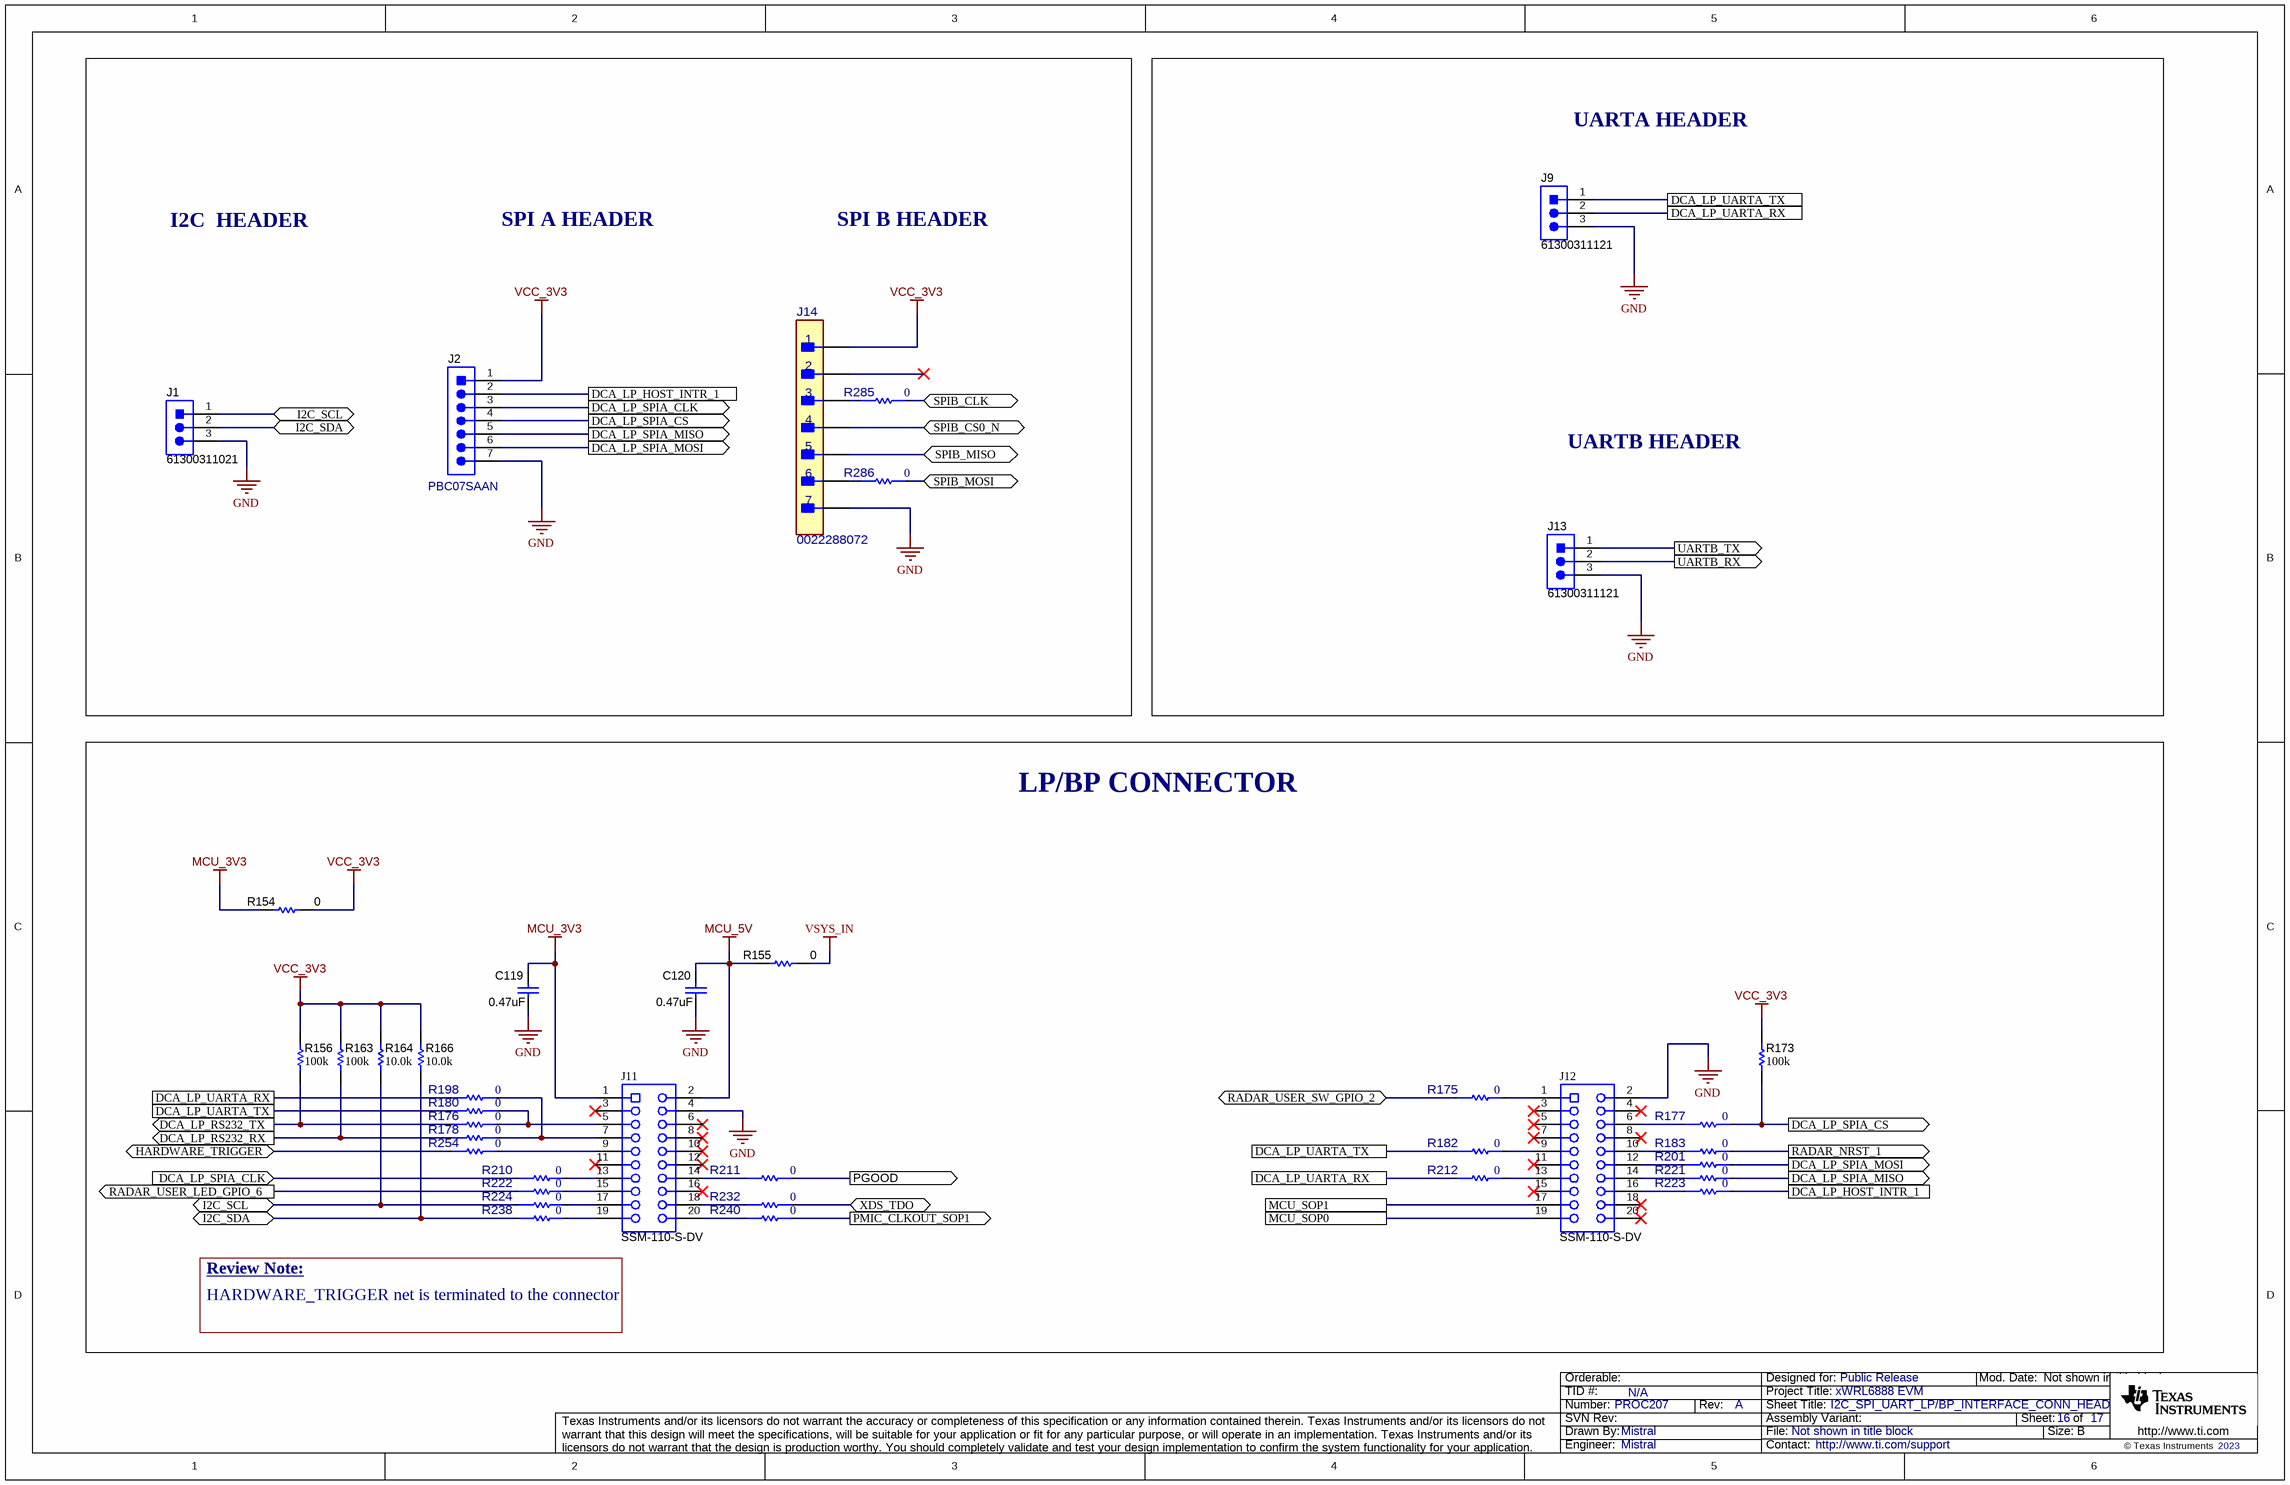
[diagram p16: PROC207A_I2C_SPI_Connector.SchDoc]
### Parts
C119  ValueDisplayed: 0.47uF  [0402L]  (hidden comment: GCM155C71A474KE36D)
C120  ValueDisplayed: 0.47uF  [0402L]  (hidden comment: GCM155C71A474KE36D)
J1  61300311021  [Wurth_61300311021]
J2  PBC07SAAN  [Sullins_xxC07SAAN]
J9  61300311121  [WURTH_61300311121]
J11  SSM-110-S-DV  [Samtec_SSM-110-x-DV]
J12  SSM-110-S-DV  [Samtec_SSM-110-x-DV]
J13  61300311121  [WURTH_61300311121]
J14  0022288072  [FP-0022288072_HDR7-MFG]
R154  ValueDisplayed: 0  [0603]  (hidden comment: MCT06030Z0000ZP500)
R155  ValueDisplayed: 0  [0603]  (hidden comment: MCT06030Z0000ZP500)
R156  ValueDisplayed: 100k  [0402L]  (hidden comment: CRCW0402100KFKED)
R163  ValueDisplayed: 100k  [0402L]  (hidden comment: CRCW0402100KFKED)
R164  ValueDisplayed: 10.0k  [0402L]  (hidden comment: CRCW040210K0FKED)
R166  ValueDisplayed: 10.0k  [0402L]  (hidden comment: CRCW040210K0FKED)
R173  ValueDisplayed: 100k  [0402L]  (hidden comment: CRCW0402100KFKED)
R175  value 0  [FP-ERJ-2GE0R00X_0402-MFG]  (hidden comment: ERJ-2GE0R00X)
R176  value 0  [FP-ERJ-2GE0R00X_0402-MFG]  (hidden comment: ERJ-2GE0R00X)
R177  value 0  [FP-ERJ-2GE0R00X_0402-MFG]  (hidden comment: ERJ-2GE0R00X)
R178  value 0  [FP-ERJ-2GE0R00X_0402-MFG]  (hidden comment: ERJ-2GE0R00X)
R180  value 0  [FP-ERJ-2GE0R00X_0402-MFG]  (hidden comment: ERJ-2GE0R00X)
R182  value 0  [FP-ERJ-2GE0R00X_0402-MFG]  (hidden comment: ERJ-2GE0R00X)
R183  value 0  [FP-ERJ-2GE0R00X_0402-MFG]  (hidden comment: ERJ-2GE0R00X)
R198  value 0  [FP-ERJ-2GE0R00X_0402-MFG]  (hidden comment: ERJ-2GE0R00X)
R201  value 0  [FP-ERJ-2GE0R00X_0402-MFG]  (hidden comment: ERJ-2GE0R00X)
R210  value 0  [FP-ERJ-2GE0R00X_0402-MFG]  (hidden comment: ERJ-2GE0R00X)
R211  value 0  [FP-ERJ-2GE0R00X_0402-MFG]  (hidden comment: ERJ-2GE0R00X)
R212  value 0  [FP-ERJ-2GE0R00X_0402-MFG]  (hidden comment: ERJ-2GE0R00X)
R221  value 0  [FP-ERJ-2GE0R00X_0402-MFG]  (hidden comment: ERJ-2GE0R00X)
R222  value 0  [FP-ERJ-2GE0R00X_0402-MFG]  (hidden comment: ERJ-2GE0R00X)
R223  value 0  [FP-ERJ-2GE0R00X_0402-MFG]  (hidden comment: ERJ-2GE0R00X)
R224  value 0  [FP-ERJ-2GE0R00X_0402-MFG]  (hidden comment: ERJ-2GE0R00X)
R232  value 0  [FP-ERJ-2GE0R00X_0402-MFG]  (hidden comment: ERJ-2GE0R00X)
R238  value 0  [FP-ERJ-2GE0R00X_0402-MFG]  (hidden comment: ERJ-2GE0R00X)
R240  value 0  [FP-ERJ-2GE0R00X_0402-MFG]  (hidden comment: ERJ-2GE0R00X)
R254  value 0  [FP-ERJ-2GE0R00X_0402-MFG]  (hidden comment: ERJ-2GE0R00X)
R285  value 0  [FP-ERJ-2GE0R00X_0402-MFG]  (hidden comment: ERJ-2GE0R00X)
R286  value 0  [FP-ERJ-2GE0R00X_0402-MFG]  (hidden comment: ERJ-2GE0R00X)

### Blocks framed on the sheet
LP/BP CONNECTOR: C119 C120 J11 J12 R154-R156 R163 R164 R166 R173 R175-R178 R180 R182 R183 R198 R201 R210-R212 R221-R224 R232 R238 R240 R254

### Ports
DCA_LP_HOST_INTR_1, DCA_LP_RS232_RX (out), DCA_LP_RS232_TX (out), DCA_LP_SPIA_CLK (in), DCA_LP_SPIA_CLK (out), DCA_LP_SPIA_CS (out), DCA_LP_SPIA_MISO (out), DCA_LP_SPIA_MOSI (out), DCA_LP_UARTA_RX, DCA_LP_UARTA_TX, HARDWARE_TRIGGER (bidir), I2C_SCL (bidir), I2C_SDA (bidir), MCU_SOP0, MCU_SOP1, PGOOD (out), PMIC_CLKOUT_SOP1 (out), RADAR_NRST_1 (out), RADAR_USER_LED_GPIO_6 (out), RADAR_USER_SW_GPIO_2 (bidir), SPIB_CLK (bidir), SPIB_CS0_N (bidir), SPIB_MISO (bidir), SPIB_MOSI (bidir), UARTB_RX (out), UARTB_TX (out), XDS_TDO (bidir)

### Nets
GND: C119.2 C120.2 J1.3 J2.7 J9.3 J11.4 J12.2 J13.3 J14.7
MCU_3V3: C119.1 J11.1 R154.1
MCU_5V: C120.1 J11.2 R155.1
VCC_3V3: J2.1 J14.1 R154.2 R156.2 R163.2 R164.2 R166.2 R173.2
VSYS_IN: R155.2
DCA_LP_HOST_INTR_1: J2.2 R223.2 ; port DCA_LP_HOST_INTR_1
DCA_LP_RS232_RX: R163.1 R178.1 ; port DCA_LP_RS232_RX
DCA_LP_RS232_TX: R156.1 R176.1 ; port DCA_LP_RS232_TX
DCA_LP_SPIA_CLK: J2.3 R210.1 ; port DCA_LP_SPIA_CLK
DCA_LP_SPIA_CS: J2.4 R173.1 R177.2 ; port DCA_LP_SPIA_CS
DCA_LP_SPIA_MISO: J2.5 R221.2 ; port DCA_LP_SPIA_MISO
DCA_LP_SPIA_MOSI: J2.6 R201.2 ; port DCA_LP_SPIA_MOSI
DCA_LP_UARTA_RX: J9.2 R198.1 R212.1 ; port DCA_LP_UARTA_RX
DCA_LP_UARTA_TX: J9.1 R180.1 R182.1 ; port DCA_LP_UARTA_TX
HARDWARE_TRIGGER: R254.1 ; port HARDWARE_TRIGGER
I2C_SCL: J1.1 R164.1 R224.1 ; port I2C_SCL
I2C_SDA: J1.2 R166.1 R238.1 ; port I2C_SDA
MCU_SOP0: J12.19 ; port MCU_SOP0
MCU_SOP1: J12.17 ; port MCU_SOP1
PGOOD: R211.2 ; port PGOOD
PMIC_CLKOUT_SOP1: R240.2 ; port PMIC_CLKOUT_SOP1
RADAR_NRST_1: R183.2 ; port RADAR_NRST_1
RADAR_USER_LED_GPIO_6: R222.1 ; port RADAR_USER_LED_GPIO_6
RADAR_USER_SW_GPIO_2: R175.1 ; port RADAR_USER_SW_GPIO_2
SPIB_CLK: R285.2 ; port SPIB_CLK
SPIB_CS0_N: J14.4 ; port SPIB_CS0_N
SPIB_MISO: J14.5 ; port SPIB_MISO
SPIB_MOSI: R286.2 ; port SPIB_MOSI
UARTB_RX: J13.2 ; port UARTB_RX
UARTB_TX: J13.1 ; port UARTB_TX
XDS_TDO: R232.2 ; port XDS_TDO
NetJ11_5: J11.5 R176.2 R180.2
NetJ11_7: J11.7 R178.2 R198.2
NetJ11_9: J11.9 R254.2
NetJ11_13: J11.13 R210.2
NetJ11_14: J11.14 R211.1
NetJ11_15: J11.15 R222.2
NetJ11_17: J11.17 R224.2
NetJ11_18: J11.18 R232.1
NetJ11_19: J11.19 R238.2
NetJ11_20: J11.20 R240.1
NetJ12_1: J12.1 R175.2
NetJ12_6: J12.6 R177.1
NetJ12_9: J12.9 R182.2
NetJ12_10: J12.10 R183.1
NetJ12_12: J12.12 R201.1
NetJ12_13: J12.13 R212.2
NetJ12_14: J12.14 R221.1
NetJ12_16: J12.16 R223.1
NetJ14_3: J14.3 R285.1
NetJ14_6: J14.6 R286.1

Not connected (* = marked no-connect by the designer): J11 3* 6* 8* 10* 11* 12* 16*; J12 3* 4* 5* 7* 8* 11* 15* 18* 20*; J14 2*

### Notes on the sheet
- UARTA HEADER
- I2C  HEADER
- SPI A HEADER
- SPI B HEADER
- UARTB HEADER
- Review Note:
- HARDWARE_TRIGGER net is terminated to the connector

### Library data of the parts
C119 C120 = CMP-0064967-2: CAP, CERM, 0.47 uF, 10 V,+/- 10%, X7S, 0402; Manufacturer: MuRata; Polarized: N; Value: 0.47uF; U/M: EA; Cap_F: 470nF; Value1: Unknown; VDC_V: 10V; TaMin_C: -55°C; TaMax_C: 125°C; Cap_Case: 0402; SizeArea_mm2: 0.5; SizeAreaWB_mm2: 3; SizeX_mm: 1; SizeZ_mm: 0.6; AEC Category: Q200
J1 = CMP-0054795-1: Header, 2.54 mm, 3x1, Gold, R/A, TH; Manufacturer: Wurth Elektronik; CNHeader: TRUE; Shrouded: N; Gender: Male; Row_Count: 1; Pitch_mm: 2.54; CT: FALSE
J2 = CMP-0054584-1: Header, 2.54 mm, 7x1, Gold, TH; Manufacturer: Sullins Connector Solutions; CNHeader: TRUE; Current_A: 3A; Shrouded: N; Gender: Male; Voltage_V: 1.8kV; Row_Count: 1; Pitch_mm: 2.54; CT: FALSE; Cert_UL: Y
J9 J13 = CMP-0054796-4: Header, 2.54 mm, 3x1, Gold, TH; Manufacturer: Wurth Elektronik; Green_REACh: Passed; CT: FALSE; CNHeader: TRUE; Green_Lifecycle: Active
J11 J12 = CMP-0078182-1: Receptacle, 2.54mm, 10x2, Gold with Tin tail, SMT; Manufacturer: Samtec; Pitch_mm: 2.54; Gender: Female; Cert_CSA: Y; Voltage_V: 405V; Current_A: 5.2A; Row_Count: 2; CompType: Socket Strip
J14 = CMP-0120118-1: Manufacturer: Molex; ContactFinish: Gold,Nickel; Current_A: 4A; Row_Count: 1; Voltage_V: 600V; AEC Qualified: No; Conn Gender: Male; Conn Orientation: Right Angle; DUT-Pitch_mm: 2.54mm; SizeZ_mm: 2.74mm
R154 R155 = CMP-0025884-3: RES, 0, 5%, 0.125 W, 0603; Manufacturer: Vishay/Beyschlag; Power_W: 125mW; TempCo: ppm/C; Value_Code: 0000; U/M: EA; Value: 0; EIA_Code: E24; SizeX_mm: 1.6; SizeY_mm: 0.8; SizeZ_mm: 1; Value2: 0.125W; SizeArea_mm2: 1.28; CompType: Resistor; AEC Qualified: N; AEC Category: Q200; INSTALATION: DNP
R156 R163 R173 = CMP-0025950-3: RES, 100 k, 1%, 0.063 W, AEC-Q200 Grade 0, 0402; Manufacturer: Vishay-Dale; Power_W: 63mW; TempCo: 100 ppm/C; Value: 100k; EIA_Code: E96; SizeX_mm: 1; SizeY_mm: 0.5; SizeZ_mm: 0.6; Value2: 0.063W; AEC Qualified: Y; VDC_V: 50V; AEC Category: Q200; AEC Grade: 0
R164 R166 = CMP-0025958-3: RES, 10.0 k, 1%, 0.063 W, AEC-Q200 Grade 0, 0402; Manufacturer: Vishay-Dale; Power_W: 63mW; TempCo: 100 ppm/C; Value_Code: 10k0; Value: 10.0k; EIA_Code: E96; Res_ohm: 10k; SizeX_mm: 1; SizeY_mm: 0.5; SizeZ_mm: 0.6; Value2: 0.063W; AEC Qualified: Y; VDC_V: 50V; AEC Category: Q200; AEC Grade: 0
R175-R178 R180 R182 R183 R198 R201 R210-R212 R221-R224 R232 R238 R240 R254 R285 R286 = CMP-0002710-1: 0 Ohms Jumper Chip Resistor 0402 (1005 Metric) Automotive AEC-Q200 Thick Film; Manufacturer: Panasonic; SizeZ_mm: 0.4mm; AEC Qualified: Yes; AEC Grade: Grade 0; Power: 100mW

## Sheet PROC207A_Hardware.SchDoc: HARDWARE
size 431 x 279 mm; Date: Not shown in title block; ApprovedBy: Not shown in title block; CheckedBy: Not shown in title block; Author: Not shown in title block; CompanyName: Not shown in title block; DrawnBy: Mistral; Engineer: Not shown in title block; Organization: Not shown in title block; Address1: Not shown in title block; Address2: Not shown in title block; Address3: Not shown in title block; Address4: Not shown in title block; DocumentNumber: 16; Revision: Use project parameter SCH_Rev; SheetNumber: 18; SheetTotal: 18; PageSetup: Record=PageOptions¦CenterHorizontal=True¦CenterVertical=True¦PrintScale=1.00¦XCorrection=1.00¦YCorrection=1.00¦PrintKind=0¦BorderSize=5000000¦LeftOffset=0¦BottomOffset=0¦Orientation=2¦PaperLength=1000¦PaperWidth=1000¦Scale=100¦PaperSource=15¦PrintQuality=600¦MediaType=1¦DitherType=10¦PaperKind=Letter¦PrintScaleMode=1

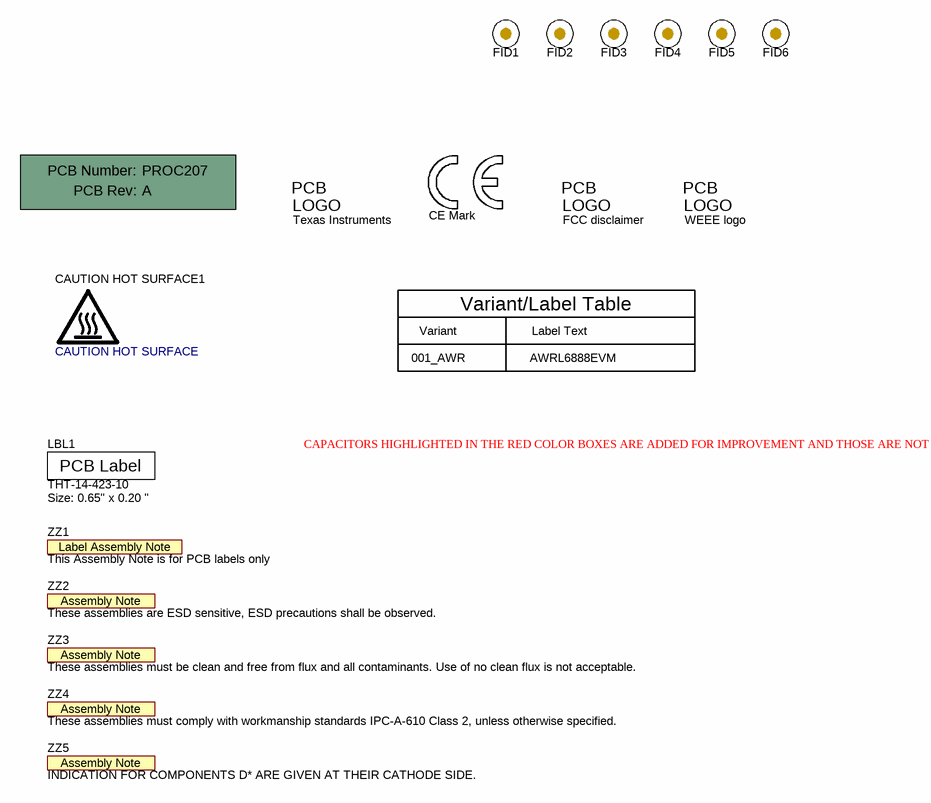
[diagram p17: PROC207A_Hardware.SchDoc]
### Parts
!PCB  Printed Circuit Board  (value not drawn)  (mechanical)
CAUTION_HOT_SURFACE1  CAUTION HOT SURFACE  [IEC_HotSurface_Small]  (no BOM)
FID1  Fiducial  [Fiducial10-20]  (value not drawn)
FID2  Fiducial  [Fiducial10-20]  (value not drawn)
FID3  Fiducial  [Fiducial10-20]  (value not drawn)
FID4  Fiducial  [Fiducial10-20]  (value not drawn)
FID5  Fiducial  [Fiducial10-20]  (value not drawn)
FID6  Fiducial  [Fiducial10-20]  (value not drawn)
LBL1  THT-14-423-10  Note: Size: 0.65" x 0.20 "  [Label_650x200]
Logo1  Texas Instruments  [TI_Stacked_Overlay_Small]  (no BOM)
Logo2  CE Mark  [CE_Mark_5mm]  (no BOM)
Logo3  FCC disclaimer  [FCC_disclaimer]  (no BOM)
Logo4  WEEE logo  [WEEE_Minimum]  (no BOM)
ZZ1  This Assembly Note is for PCB labels only  [AssemblyNoteLabel]  (no BOM)
ZZ2  These assemblies are ESD sensitive, ESD precautions shall be observed.  [AssemblyNote]  (no BOM)
ZZ3  These assemblies must be clean and free from flux and all contaminants. Use of no clean flux is not acceptable.  [AssemblyNote]  (no BOM)
ZZ4  These assemblies must comply with workmanship standards IPC-A-610 Class 2, unless otherwise specified.  [AssemblyNote]  (no BOM)
ZZ5  INDICATION FOR COMPONENTS D* ARE GIVEN AT THEIR CATHODE SIDE.  [AssemblyNote]  (no BOM)

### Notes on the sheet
- Variant
- 001_AWR
- Variant/Label Table
- Label Text
- AWRL6888EVM
- CAPACITORS HIGHLIGHTED IN THE RED COLOR BOXES ARE ADDED FOR IMPROVEMENT AND THOSE ARE NOT MANDITORY.

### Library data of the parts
!PCB = CMP-0003618-2: Manufacturer: Any; PartNumber: PROC207
CAUTION_HOT_SURFACE1 = CMP-0074837-2: IEC 61010-1 Hot Surface Warning; Manufacturer: Texas Instruments; SymbolCreator: a0412235; AEC Category: Q200; CompType: IC
FID1-FID6 = CMP-0077181-1: Fiducial mark.  There is nothing to buy or mount.
LBL1 = CMP-0003625-1: Thermal Transfer Printable Labels, 0.650" W x 0.200" H - 10,000 per roll; Manufacturer: Brady; CompType: Label
Logo1 = CMP-0074838-1: Texas Instrument Corporate Signature; SymbolCreator: a0412235; Lib Reference: TI_Logo; Library Reference: Logo
Logo2 = CMP-0074844-1: SymbolCreator: a0412235
Logo3 = CMP-0074847-1: FCC_disclaimer; Library Reference: Logo
Logo4 = CMP-0074769-1
ZZ1 = CMP-0003616-3
ZZ2 = CMP-0077236-1
ZZ3 = CMP-0077237-1
ZZ4 ZZ5 = CMP-0077238-1

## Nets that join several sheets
5V_IN_USB: PROC207A_USB_PWR_DC_Jack_Switch (15 pins), PROC207A_PMIC (C42.2 U13.6), PROC207A_CAN_LIN_PHY_Interface (R69.2)
FTDI_VBUS: PROC207A_USB_PWR_DC_Jack_Switch (L8.1), PROC207A_FTDI (C157.2 J10.1 R259.2)
GND: PROC207A_USB_PWR_DC_Jack_Switch (45 pins), PROC207A_PMIC (46 pins), PROC207A_Chip (6 pins), PROC207A_Chip_Power (202 pins), PROC207A_Decoupling_caps- QSPI Flash (33 pins), PROC207A_Temp_Current_sensors_EPROM (24 pins), PROC207A_Analog_Mux_SOP_Ctrl (19 pins), PROC207A_Analog_MUX_SPI (9 pins), PROC207A_XDS110_Interface (33 pins), PROC207A_MUX_CAN_FD (8 pins), PROC207A_CAN_LIN_PHY_Interface (10 pins), PROC207A_FTDI (42 pins), PROC207A_DCA1000_Connector_Reset (25 pins), PROC207A_I2C_SPI_Connector (9 pins)
RADAR_1P2_RF: PROC207A_Chip_Power (U1.F11 U1.F12 U1.F13), PROC207A_Decoupling_caps- QSPI Flash (C24.2 C44.1), PROC207A_Temp_Current_sensors_EPROM (R134.2 U25.9)
RADAR_1V2: PROC207A_Chip_Power (40 pins), PROC207A_Decoupling_caps- QSPI Flash (8 pins), PROC207A_Temp_Current_sensors_EPROM (R193.2 U8.9)
RADAR_1V4_APLL: PROC207A_Chip_Power (U1.K8), PROC207A_Decoupling_caps- QSPI Flash (C22.2)
RADAR_1V4_SYNTH: PROC207A_Chip_Power (U1.F6), PROC207A_Decoupling_caps- QSPI Flash (C18.2)
RADAR_1V8: PROC207A_Chip_Power (10 pins), PROC207A_Decoupling_caps- QSPI Flash (11 pins), PROC207A_Temp_Current_sensors_EPROM (R192.2 U6.9)
RADAR_1V_RF_OUT: PROC207A_Chip_Power (5 pins), PROC207A_Decoupling_caps- QSPI Flash (C9.2 C19.2)
RADAR_3V3: PROC207A_Chip (7 pins), PROC207A_Chip_Power (U1.AA12 U1.G21 U1.W21), PROC207A_Decoupling_caps- QSPI Flash (C16.2 C17.2 C21.2), PROC207A_Temp_Current_sensors_EPROM (R200.2 U7.9)
RADAR_VBGAP: PROC207A_Chip_Power (U1.P6), PROC207A_Decoupling_caps- QSPI Flash (C6.1)
REG_1V2: PROC207A_PMIC (C20.2 C91.2 FB2.2), PROC207A_Temp_Current_sensors_EPROM (R193.1 U8.8 U8.10)
REG_1V8: PROC207A_PMIC (C3.2 C82.2 FB1.2), PROC207A_Temp_Current_sensors_EPROM (R192.1 U6.8 U6.10)
REG_RF_1V2: PROC207A_PMIC (C27.2 C103.2 FB3.2), PROC207A_Temp_Current_sensors_EPROM (R134.1 U25.8 U25.10)
VCC_3V3: PROC207A_USB_PWR_DC_Jack_Switch (R172.2), PROC207A_PMIC (5 pins), PROC207A_Decoupling_caps- QSPI Flash (6 pins), PROC207A_Temp_Current_sensors_EPROM (33 pins), PROC207A_Analog_Mux_SOP_Ctrl (14 pins), PROC207A_Analog_MUX_SPI (11 pins), PROC207A_MUX_CAN_FD (8 pins), PROC207A_CAN_LIN_PHY_Interface (C38.2 R17.2 R22.2 U5.5), PROC207A_FTDI (R99.2), PROC207A_DCA1000_Connector_Reset (13 pins), PROC207A_I2C_SPI_Connector (8 pins)
VCC_CAN_3V3: PROC207A_PMIC (C72.2 L4.2), PROC207A_MUX_CAN_FD (R129.2), PROC207A_CAN_LIN_PHY_Interface (R266.1)
VCC_XDS_3V3: PROC207A_PMIC (C105.1 TP20.1 U13.1), PROC207A_XDS110_Interface (26 pins), PROC207A_FTDI (L7.1)
VPP_1P7: PROC207A_PMIC (P1.1), PROC207A_Chip_Power (C31.1 U1.Y6)
VSYS_IN: PROC207A_USB_PWR_DC_Jack_Switch (8 pins), PROC207A_PMIC (5 pins), PROC207A_CAN_LIN_PHY_Interface (J4.1 R31.1), PROC207A_DCA1000_Connector_Reset (R30.1), PROC207A_I2C_SPI_Connector (R155.2)
XDSET_1_VBUS: PROC207A_USB_PWR_DC_Jack_Switch (R1.1 U9.6), PROC207A_XDS110_Interface (R169.2 R236.2)
CAN_FD_B_PHY_RX: PROC207A_Chip (U1.AA16), PROC207A_MUX_CAN_FD (R143.1)
CAN_FD_B_PHY_TX: PROC207A_Chip (U1.AA14), PROC207A_MUX_CAN_FD (R132.1)
CAN_FD_B_STB_CTRL: PROC207A_Analog_Mux_SOP_Ctrl (S1.1), PROC207A_MUX_CAN_FD (R133.1)
CAN_FD_RX: PROC207A_MUX_CAN_FD (U18.5), PROC207A_CAN_LIN_PHY_Interface (R80.1)
CAN_FD_TX: PROC207A_MUX_CAN_FD (U18.9), PROC207A_CAN_LIN_PHY_Interface (R78.1)
CAN_FD_UARTA_RX: PROC207A_Chip (U1.Y8), PROC207A_MUX_CAN_FD (U18.6)
CAN_FD_UARTA_TX: PROC207A_Chip (U1.AA7), PROC207A_MUX_CAN_FD (U18.10)
CAN_STB_CTRL: PROC207A_Analog_Mux_SOP_Ctrl (S4.1), PROC207A_CAN_LIN_PHY_Interface (R3.1)
DCA_LP_FTDI_HOST_INTR_1: PROC207A_Chip (R81.2 R261.2 R276.1), PROC207A_Analog_MUX_SPI (U28.10)
DCA_LP_FTDI_SPIA_CLK: PROC207A_Chip (U1.F19), PROC207A_Analog_MUX_SPI (U28.4)
DCA_LP_FTDI_SPIA_CS: PROC207A_Chip (R246.1 U1.E20), PROC207A_Analog_MUX_SPI (U28.6)
DCA_LP_FTDI_SPIA_MISO: PROC207A_Chip (R284.1), PROC207A_Analog_MUX_SPI (U28.7)
DCA_LP_FTDI_SPIA_MOSI: PROC207A_Chip (U1.E19), PROC207A_Analog_MUX_SPI (U28.9)
DCA_LP_HOST_INTR_1: PROC207A_Analog_MUX_SPI (U28.19), PROC207A_DCA1000_Connector_Reset (R42.2), PROC207A_I2C_SPI_Connector (J2.2 R223.2)
DCA_LP_RS232_RX: PROC207A_Analog_Mux_SOP_Ctrl (U12.3), PROC207A_DCA1000_Connector_Reset (R61.1), PROC207A_I2C_SPI_Connector (R163.1 R178.1)
DCA_LP_RS232_TX: PROC207A_Analog_Mux_SOP_Ctrl (U12.15), PROC207A_DCA1000_Connector_Reset (R62.1), PROC207A_I2C_SPI_Connector (R156.1 R176.1)
DCA_LP_SPIA_CLK: PROC207A_Analog_MUX_SPI (U28.2), PROC207A_DCA1000_Connector_Reset (R41.1), PROC207A_I2C_SPI_Connector (J2.3 R210.1)
DCA_LP_SPIA_CS: PROC207A_Analog_MUX_SPI (U28.1), PROC207A_DCA1000_Connector_Reset (R39.1), PROC207A_I2C_SPI_Connector (J2.4 R173.1 R177.2)
DCA_LP_SPIA_MISO: PROC207A_Analog_MUX_SPI (U28.23), PROC207A_DCA1000_Connector_Reset (R53.2), PROC207A_I2C_SPI_Connector (J2.5 R221.2)
DCA_LP_SPIA_MOSI: PROC207A_Analog_MUX_SPI (U28.21), PROC207A_DCA1000_Connector_Reset (R52.1), PROC207A_I2C_SPI_Connector (J2.6 R201.2)
DCA_LP_UARTA_RX: PROC207A_Analog_Mux_SOP_Ctrl (U16.3), PROC207A_DCA1000_Connector_Reset (R152.2), PROC207A_I2C_SPI_Connector (J9.2 R198.1 R212.1)
DCA_LP_UARTA_TX: PROC207A_Analog_Mux_SOP_Ctrl (U16.1), PROC207A_DCA1000_Connector_Reset (R153.2), PROC207A_I2C_SPI_Connector (J9.1 R180.1 R182.1)
DCA_TCK: PROC207A_Analog_Mux_SOP_Ctrl (U4.16), PROC207A_DCA1000_Connector_Reset (R38.2)
DCA_TDI: PROC207A_Analog_Mux_SOP_Ctrl (U4.3), PROC207A_DCA1000_Connector_Reset (R37.1)
DCA_TDO: PROC207A_Analog_Mux_SOP_Ctrl (U4.9), PROC207A_DCA1000_Connector_Reset (R34.2)
DCA_TMS: PROC207A_Analog_Mux_SOP_Ctrl (U4.12), PROC207A_DCA1000_Connector_Reset (R40.2)
FTDI_DCA_LP_RS232_RX: PROC207A_Analog_Mux_SOP_Ctrl (U12.2), PROC207A_MUX_CAN_FD (U18.3)
FTDI_DCA_LP_RS232_TX: PROC207A_Analog_Mux_SOP_Ctrl (U12.14), PROC207A_MUX_CAN_FD (U18.15)
FTDI_HOST_INTR_1: PROC207A_Analog_MUX_SPI (U28.18), PROC207A_FTDI (R216.2 R217.2)
FTDI_RS232_RX: PROC207A_Analog_Mux_SOP_Ctrl (U12.1), PROC207A_FTDI (R120.2)
FTDI_RS232_TX: PROC207A_Analog_Mux_SOP_Ctrl (U12.13), PROC207A_FTDI (R121.2)
FTDI_SOP0: PROC207A_Analog_Mux_SOP_Ctrl (R13.1 R43.2 R235.1), PROC207A_FTDI (R249.2)
FTDI_SOP1: PROC207A_Analog_Mux_SOP_Ctrl (R16.1 R67.2 R244.1), PROC207A_FTDI (R248.2)
FTDI_SPI_CLK: PROC207A_Analog_MUX_SPI (U28.11), PROC207A_FTDI (R186.2)
FTDI_SPI_CS: PROC207A_Analog_MUX_SPI (U28.13), PROC207A_FTDI (R99.1 R209.2)
FTDI_SPI_MISO: PROC207A_Analog_MUX_SPI (U28.15), PROC207A_FTDI (R189.2)
FTDI_SPI_MOSI: PROC207A_Analog_MUX_SPI (U28.17), PROC207A_FTDI (R187.2)
FTDI_UARTA_RX: PROC207A_Analog_Mux_SOP_Ctrl (U16.4), PROC207A_FTDI (R118.2)
FTDI_UARTA_TX: PROC207A_Analog_Mux_SOP_Ctrl (U16.2), PROC207A_FTDI (R119.2)
HARDWARE_TRIGGER: PROC207A_Chip (J15.2), PROC207A_I2C_SPI_Connector (R254.1)
HOST_CLK_REQ_SPIB_MISO: PROC207A_Chip (R270.2), PROC207A_Analog_MUX_SPI (U30.7)
I2C_SCL: PROC207A_PMIC (R89.1), PROC207A_Temp_Current_sensors_EPROM (7 pins), PROC207A_Analog_MUX_SPI (U30.16), PROC207A_XDS110_Interface (R199.1 S5.2), PROC207A_FTDI (R96.2), PROC207A_DCA1000_Connector_Reset (R60.1), PROC207A_I2C_SPI_Connector (J1.1 R164.1 R224.1)
I2C_SCL_SPIB_CLK: PROC207A_Chip (U1.T21), PROC207A_Analog_MUX_SPI (U30.2)
I2C_SDA: PROC207A_PMIC (R90.1), PROC207A_Temp_Current_sensors_EPROM (7 pins), PROC207A_Analog_MUX_SPI (U30.3), PROC207A_XDS110_Interface (R197.1 S5.1), PROC207A_FTDI (R100.2 R102.2), PROC207A_DCA1000_Connector_Reset (R59.1), PROC207A_I2C_SPI_Connector (J1.2 R166.1 R238.1)
I2C_SDA_SPIB_MOSI: PROC207A_Chip (U1.R20), PROC207A_Analog_MUX_SPI (U30.5)
LIN_PHY_EN_CTRL: PROC207A_Analog_Mux_SOP_Ctrl (S4.2), PROC207A_CAN_LIN_PHY_Interface (R88.1)
LIN_PHY_RX: PROC207A_Analog_MUX_SPI (U24.1), PROC207A_CAN_LIN_PHY_Interface (R18.1 R22.1)
LIN_PHY_RX_UARTB_TX: PROC207A_Chip (U1.AA17), PROC207A_Analog_MUX_SPI (U24.9)
LIN_PHY_TX: PROC207A_Analog_MUX_SPI (U24.3), PROC207A_CAN_LIN_PHY_Interface (R19.1)
LIN_PHY_TX_UARTB_RX: PROC207A_Chip (U1.Y18), PROC207A_Analog_MUX_SPI (U24.6)
MCU_SOP0: PROC207A_Analog_Mux_SOP_Ctrl (R235.2), PROC207A_I2C_SPI_Connector (J12.19)
MCU_SOP1: PROC207A_Analog_Mux_SOP_Ctrl (R244.2), PROC207A_I2C_SPI_Connector (J12.17)
MUX_CTRL_FTDI_DCA_SPIA: PROC207A_Analog_Mux_SOP_Ctrl (S4.3), PROC207A_Analog_MUX_SPI (R12.2 U28.14 U28.24)
MUX_CTRL_LIN_UARTB: PROC207A_Analog_Mux_SOP_Ctrl (S4.5), PROC207A_Analog_MUX_SPI (R253.1 U24.7 U24.8)
MUX_CTRL_SPIB_I2C_SYS_RST_HOST_CLK_REQ: PROC207A_Analog_Mux_SOP_Ctrl (S4.6), PROC207A_Analog_MUX_SPI (R271.1 U30.15)
MUX_CTRL_UARTA_CAN_FD: PROC207A_Analog_Mux_SOP_Ctrl (S1.4), PROC207A_MUX_CAN_FD (R128.1 U18.8)
MUX_CTRL_XDS_FTDI_DCA_LP_RS232: PROC207A_Analog_Mux_SOP_Ctrl (S1.2), PROC207A_MUX_CAN_FD (R127.1 U18.16)
PGOOD: PROC207A_USB_PWR_DC_Jack_Switch (R179.1), PROC207A_PMIC (R91.1 R92.2 R241.1), PROC207A_DCA1000_Connector_Reset (R58.1), PROC207A_I2C_SPI_Connector (R211.2)
PMIC_CAN_STB_CTRL: PROC207A_PMIC (R85.1), PROC207A_MUX_CAN_FD (R131.1), PROC207A_CAN_LIN_PHY_Interface (R273.1)
PMIC_CLKOUT_SOP1: PROC207A_Chip (U1.E21), PROC207A_Analog_Mux_SOP_Ctrl (R15.1 R206.1), PROC207A_I2C_SPI_Connector (R240.2)
PMIC_RADAR_nINT: PROC207A_PMIC (R245.1), PROC207A_Chip (R257.1 U1.T20)
QSPI_D0: PROC207A_Chip (U1.C20), PROC207A_Decoupling_caps- QSPI Flash (R45.2)
QSPI_D1: PROC207A_Chip (U1.B21), PROC207A_Decoupling_caps- QSPI Flash (R46.1)
QSPI_D2: PROC207A_Chip (U1.A19), PROC207A_Decoupling_caps- QSPI Flash (R44.1 R47.1)
QSPI_D3: PROC207A_Chip (U1.A20), PROC207A_Decoupling_caps- QSPI Flash (R49.1 R51.2)
QSPI_nCS: PROC207A_Chip (U1.C21), PROC207A_Decoupling_caps- QSPI Flash (R50.2 U2.1)
QSPI_SCLK: PROC207A_Chip (U1.D20), PROC207A_Decoupling_caps- QSPI Flash (R48.2)
RADAR_LVDS_0M: PROC207A_Chip (U1.J21), PROC207A_DCA1000_Connector_Reset (R230.2)
RADAR_LVDS_0P: PROC207A_Chip (U1.J20), PROC207A_DCA1000_Connector_Reset (R229.2)
RADAR_LVDS_1M: PROC207A_Chip (U1.P21), PROC207A_DCA1000_Connector_Reset (R228.2)
RADAR_LVDS_1P: PROC207A_Chip (U1.P20), PROC207A_DCA1000_Connector_Reset (R227.2)
RADAR_LVDS_CLKM: PROC207A_Chip (U1.L21), PROC207A_DCA1000_Connector_Reset (R226.2)
RADAR_LVDS_CLKP: PROC207A_Chip (U1.K20), PROC207A_DCA1000_Connector_Reset (R225.2)
RADAR_LVDS_FRCLKM: PROC207A_Chip (U1.M21), PROC207A_DCA1000_Connector_Reset (R220.2)
RADAR_LVDS_FRCLKP: PROC207A_Chip (U1.N20), PROC207A_DCA1000_Connector_Reset (R219.2)
RADAR_nERROR_OUT: PROC207A_PMIC (R288.1 R289.2 U15.13), PROC207A_Chip (R247.1 U1.AA20), PROC207A_DCA1000_Connector_Reset (D13.1)
RADAR_NRST: PROC207A_Chip (C134.2 R250.1 U1.Y7), PROC207A_DCA1000_Connector_Reset (R171.2 U17.4)
RADAR_NRST_1: PROC207A_PMIC (D4.2), PROC207A_DCA1000_Connector_Reset (R63.1 R123.1 U17.1), PROC207A_I2C_SPI_Connector (R183.2)
RADAR_NRST_2: PROC207A_FTDI (R243.2), PROC207A_DCA1000_Connector_Reset (5 pins)
RADAR_USER_LED_GPIO_6: PROC207A_Chip (R269.2 U1.AA19), PROC207A_FTDI (R242.2), PROC207A_DCA1000_Connector_Reset (R263.2 R264.2), PROC207A_I2C_SPI_Connector (R222.1)
RADAR_USER_SW_GPIO_2: PROC207A_Chip (U1.H20), PROC207A_DCA1000_Connector_Reset (R66.2 R214.2), PROC207A_I2C_SPI_Connector (R175.1)
SPIB_CLK: PROC207A_Analog_MUX_SPI (U30.1), PROC207A_I2C_SPI_Connector (R285.2)
SPIB_CS0_N: PROC207A_Analog_MUX_SPI (U30.11), PROC207A_I2C_SPI_Connector (J14.4)
SPIB_MISO: PROC207A_Analog_MUX_SPI (U30.8), PROC207A_I2C_SPI_Connector (J14.5)
SPIB_MOSI: PROC207A_Analog_MUX_SPI (U30.4), PROC207A_I2C_SPI_Connector (R286.2)
SYS_RST_OUT: PROC207A_Analog_MUX_SPI (U30.12), PROC207A_DCA1000_Connector_Reset (D9.1 R65.2)
SYS_RST_OUT_SPIB_CS0_N: PROC207A_Chip (R146.1 R268.2), PROC207A_Analog_MUX_SPI (U30.10)
UARTB_RX: PROC207A_Analog_MUX_SPI (R275.1 U24.4), PROC207A_I2C_SPI_Connector (J13.2)
UARTB_TX: PROC207A_Analog_MUX_SPI (R274.1 U24.2), PROC207A_I2C_SPI_Connector (J13.1)
XDS_DCA_LP_FTDI_UARTA_RX: PROC207A_Analog_Mux_SOP_Ctrl (U12.6), PROC207A_MUX_CAN_FD (R147.2 U18.7)
XDS_DCA_LP_FTDI_UARTA_TX: PROC207A_Analog_Mux_SOP_Ctrl (U12.10), PROC207A_MUX_CAN_FD (R149.2 U18.11)
XDS_DCA_TCK: PROC207A_Chip (U1.Y14), PROC207A_Analog_Mux_SOP_Ctrl (U4.2)
XDS_DCA_TDI: PROC207A_Chip (U1.Y17), PROC207A_Analog_Mux_SOP_Ctrl (U4.5)
XDS_DCA_TDO_SOP0: PROC207A_Chip (R93.1), PROC207A_Analog_Mux_SOP_Ctrl (R203.1 U4.7)
XDS_DCA_TMS: PROC207A_Chip (U1.Y16), PROC207A_Analog_Mux_SOP_Ctrl (U4.10)
XDS_FTDI_DCA_RS232_RX: PROC207A_Chip (R255.1 U1.V20), PROC207A_MUX_CAN_FD (U18.2)
XDS_FTDI_DCA_RS232_TX: PROC207A_Chip (R256.1 U1.U20), PROC207A_MUX_CAN_FD (U18.14)
XDS_NRST: PROC207A_XDS110_Interface (R126.2), PROC207A_DCA1000_Connector_Reset (R138.1 U17.3)
XDS_RS232_RX: PROC207A_XDS110_Interface (R24.2 R188.1), PROC207A_MUX_CAN_FD (U18.1)
XDS_RS232_TX: PROC207A_XDS110_Interface (R26.2 R181.1), PROC207A_MUX_CAN_FD (U18.13)
XDS_SOP0: PROC207A_Analog_Mux_SOP_Ctrl (R43.1), PROC207A_XDS110_Interface (U21.42)
XDS_SOP1: PROC207A_Analog_Mux_SOP_Ctrl (R67.1), PROC207A_XDS110_Interface (U21.43)
XDS_TCK: PROC207A_Analog_Mux_SOP_Ctrl (U4.1), PROC207A_XDS110_Interface (R122.2)
XDS_TDI: PROC207A_Analog_Mux_SOP_Ctrl (U4.4), PROC207A_XDS110_Interface (R125.2)
XDS_TDO: PROC207A_Analog_Mux_SOP_Ctrl (U4.8), PROC207A_XDS110_Interface (U21.37), PROC207A_I2C_SPI_Connector (R232.2)
XDS_TMS: PROC207A_Analog_Mux_SOP_Ctrl (U4.11), PROC207A_XDS110_Interface (R124.2)
XDS_UARTA_RX: PROC207A_Analog_Mux_SOP_Ctrl (U12.7), PROC207A_XDS110_Interface (R24.1 R290.1)
XDS_UARTA_TX: PROC207A_Analog_Mux_SOP_Ctrl (U12.11), PROC207A_XDS110_Interface (R26.1 R190.1)
XDSET_1_DM: PROC207A_USB_PWR_DC_Jack_Switch (J5.2 U9.4), PROC207A_XDS110_Interface (U21.93)
XDSET_1_DP: PROC207A_USB_PWR_DC_Jack_Switch (J5.3 U9.5), PROC207A_XDS110_Interface (U21.94)
XDSET_1_ID: PROC207A_USB_PWR_DC_Jack_Switch (J5.4 U9.2), PROC207A_XDS110_Interface (R170.2)

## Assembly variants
01_AWR: not fitted C70 C71 C80 C81 C89 C90 FID1 FID2 FID3 FID4 FID5 FID6 J9 J11 J12 J13 J14 R2 R14 R15 R24 R26 R30 R32 R54 R59 R60 R65 R73 R76 R82 R83 R84 R85 R92 R96 R100 R102 R107 R113 R114 R116 R131 R135 R150 R152 R153 R154 R155 R156 R157 R161 R163 R164 R166 R173 R180 R197 R198 R199 R235 R242 R244 R247 R254 R266 R273 R276 R278 R279; alternate parts U1 -> CMP-0122984-4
